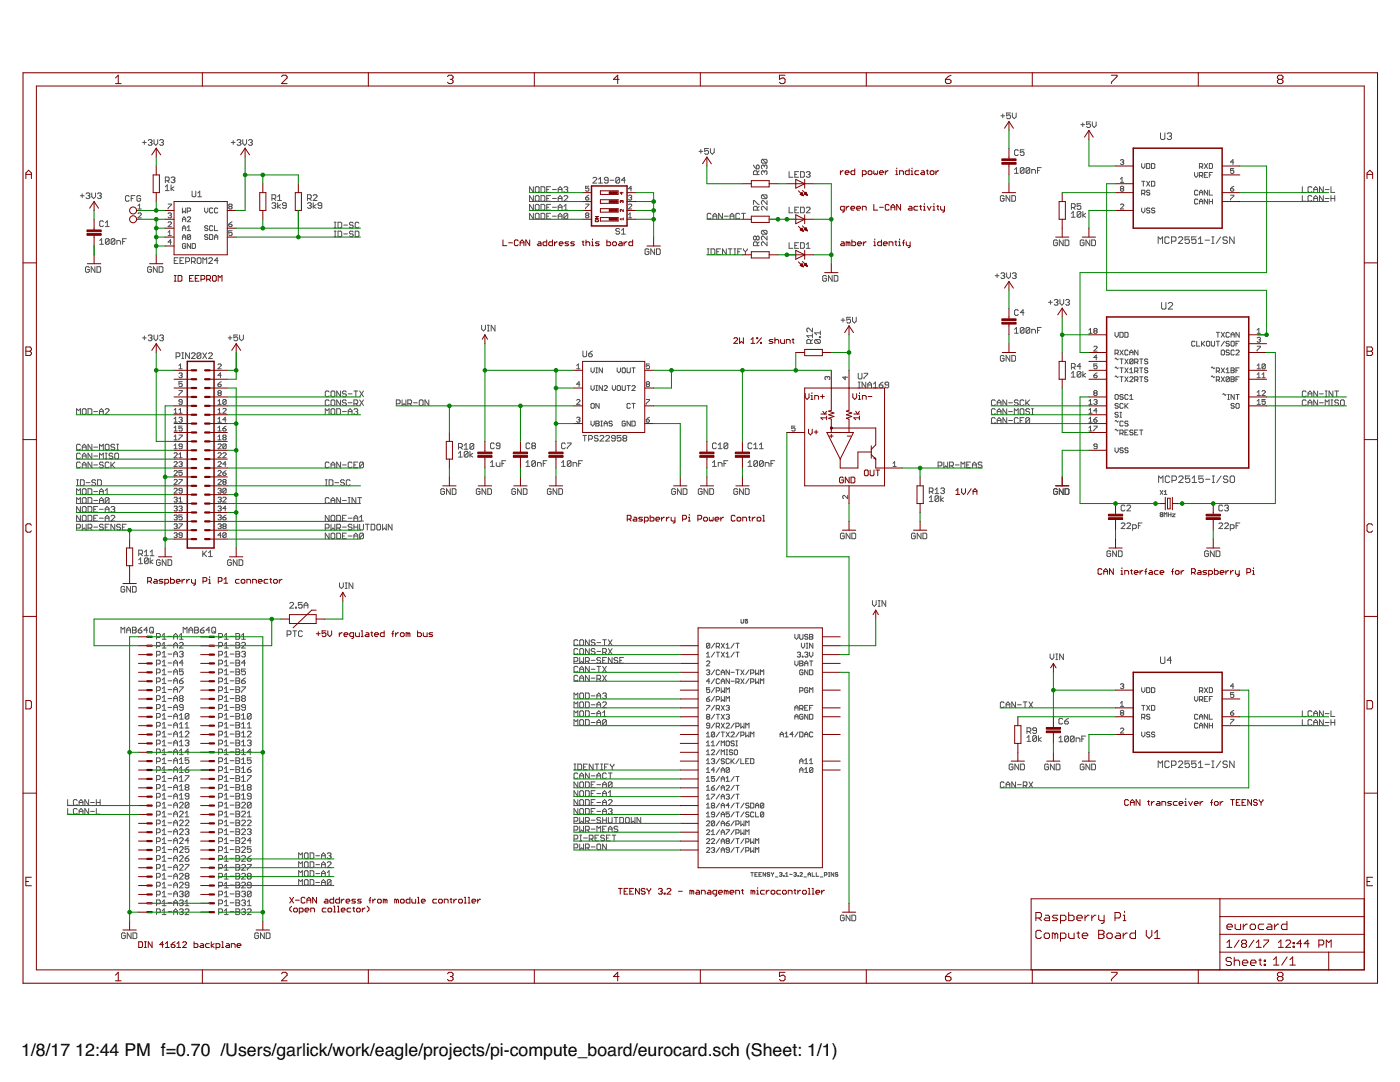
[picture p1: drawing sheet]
<svg xmlns="http://www.w3.org/2000/svg" width="279mm" height="216mm" viewBox="0 0 279 216" stroke-linecap="round" stroke-linejoin="round" font-family="sans-serif">
<defs><g id="words">
<g font-size="3.5">
<text x="4.2" y="210.7">1/8/17</text>
<text x="15" y="210.7">12:44 PM f=0.70 /Users/garlick/work/eagle/projects/pi-compute_board/eurocard.sch (Sheet: 1/1)</text>
</g>
</g></defs>
<g fill="none" stroke="#505050" stroke-width=".2">
<path d="M16 39.1h.8M16.4 38.7v.7M17.2 38.7l.2-.2h.3l.2 .2-.2 .4M17.5 39.1h.2M17.7 39.1l.2 .1-.2 .4h-.3l-.2-.2M18.3 38.5v.7l.4 .4 .4-.4v-.7M19.5 38.7l.1-.2h.4l.2 .2-.2 .4M19.8 39.1h.2M20 39.1l.2 .1-.2 .4h-.4l-.1-.2M25.8 39.2l-.2-.2h-.4l-.2 .2v.8l.2 .2h.4l.2-.2M26.2 39.6h.3M26.9 39h-.7v1.2"/>
<path d="M28.1 39.2l-.2-.2h-.4l-.2 .2v.8l.2 .2h.4l.2-.2v-.4h-.4M28.4 28.4h.8M28.8 28v.8M29.6 28l.2-.1h.3l.2 .1-.2 .4M30 28.4h.1M30.1 28.4l.2 .2-.2 .4h-.3l-.2-.2M30.7 27.9v.7l.4 .4 .4-.4v-.7M31.9 28l.1-.1h.4l.2 .1-.2 .4M32.2 28.4h.2M32.4 28.4l.2 .2-.2 .4h-.4l-.1-.2M33 37.3l.4-.4v1.1M33 38h.8"/>
<path d="M33 36.1h.6l.2-.2v-.4l-.2-.2h-.6v1.1M33.4 36.1l.4 .3M34.1 36.9v1.1M34.1 35.5l.2-.2h.4l.2 .2-.2 .4M34.5 35.9h.2M34.7 37.3l-.6 .4 .6 .3M34.7 35.9l.2 .2-.2 .3h-.4l-.2-.1M38.3 38.1v1l.2 .2h.4l.2-.2v-1M39.5 39.3h.7M39.5 38.5l.4-.4v1.2M46.2 28.4h.7M46.5 28v.8"/>
<path d="M47.3 28l.2-.1h.4l.2 .1-.2 .4M47.7 28.4h.2M47.9 28.4l.2 .2-.2 .4h-.4l-.2-.2M48.5 27.9v.7l.3 .4 .4-.4v-.7M49.6 28l.2-.1h.4l.2 .1-.2 .4M50 28.4h.2M50.2 28.4l.2 .2-.2 .4h-.4l-.2-.2M54.3 39.6h.5l.2-.2v-.3l-.2-.2h-.5v1.1M54.7 39.6l.3 .4M55.4 39.2l.4-.3v1.1M61.4 39.6h.5l.2-.2v-.3l-.2-.2h-.5v1.1M61.7 39.6l.4 .4"/>
<path d="M62.5 39.1l.2-.2h.4l.2 .2v.1l-.8 .8h.8M106.4 37.3v1.1l-.7-1.1v1.1M106.4 39v1.2l-.7-1.2v1.2M107 39h.4l.2 .2v.8l-.2 .2h-.4l-.2-.2v-.8zM107 37.3h.4l.2 .1v.8l-.2 .2h-.4l-.2-.2v-.8zM108 39h.5l.2 .2v.8l-.2 .2h-.5zM108 37.3h.5l.2 .1v.8l-.2 .2h-.5zM109.1 39.6h.4M109.1 37.8h.4M109.9 39h-.8v1.2h.8M109.9 37.3h-.8v1.1h.8M110.3 39.6h.7"/>
<path d="M110.3 37.8h.7M111.4 39.6h.8M111.4 37.8h.8M111.4 38.4v-.8l.4-.3 .4 .3v.8M112.5 39.2l.2-.2h.4l.2 .2v.2l-.8 .8h.8M112.5 37.4l.2-.1h.4l.2 .1-.2 .4M112.9 37.8h.2M113.1 37.8l.2 .2-.2 .4h-.4l-.2-.2M116.9 39.4h.4l.2 .4-.2 .1h-.3l-.1-.1zM117.5 37.2h-.6v.5l.4-.2 .2 .2v.3l-.2 .1-.4-.1M117.5 38.9l-.6 .5M118.3 35.6l.2-.2h.4l.2 .2v.2l-.8 .7h.8"/>
<path d="M119.5 35.8l.3-.4v1.1M119.5 36.5h.7M121.4 36h-.6l-.2-.2 .2-.4h.4l.2 .2v.7l-.2 .2h-.4l-.2-.2M121.8 36h.7M123.7 35.6v.7l-.2 .2h-.4l-.2-.2M123.7 35.6l-.2-.2h-.4l-.2 .2v.7M123.7 35.6l-.8 .7M124.8 36h-.8l.6-.6v1.1M125.4 39.1l.2-.2h.3l.2 .2-.2 .3M125.8 39.4h.1M125.9 39.4l.2 .2-.2 .3h-.3l-.2-.1M126.1 37.7h-.7l.5-.5v.9"/>
<path d="M139.5 30.2h.8M139.9 29.8v.8M141.4 29.6h-.8v.6l.4-.2 .4 .2v.4l-.2 .2h-.4l-.2-.2M141.8 29.6v.8l.4 .4 .3-.4v-.8M150.4 32.9l.5 .8M150.9 33.1l.2-.2 .4 .2v.4l-.2 .2h-.4zM151.1 34.8v-.5l-.2-.2h-.3l-.2 .2v.5h1.1M151.5 34.1l-.4 .4M152.1 31.8l-.1 .2v.4l.1 .2h.8M152.1 38.9l-.1 .2v.4l.1 .1h.8M152.1 31.8h.8l.2 .2v.4l-.2 .2M152.1 38.9h.8l.2 .2v.4l-.2 .1"/>
<path d="M152.1 31.8l.8 .8M152.1 38.9l.8 .7M152.5 33.1l.2-.2 .4 .2v.4l-.2 .2M152.5 34.3l-.2-.2-.3 .2v.3l.1 .2M152.5 33.1l-.2-.2-.3 .2v.4l.1 .2M152.5 34.3l.2-.2 .4 .2v.3l-.2 .2M152.5 33.1v.2M152.5 34.3v.2M157.5 34.2v1.2h.7M158.6 34.8h.4M159.4 34.2h-.8v1.2h.8M159.8 34.2h.5l.2 .2v.8l-.2 .2h-.5z"/>
<path d="M160.9 34.4l.2-.2h.4l.2 .2-.2 .4M161.3 34.8h.2M161.5 34.8l.2 .2-.2 .4h-.4l-.2-.2M199.7 23.1h.8M200.1 22.7v.8M200.4 39.2l-.2-.2h-.4l-.2 .2v.8l.2 .2h.4l.2-.2v-.4h-.4M201.5 39v1.2l-.7-1.2v1.2M201.7 22.5h-.8v.6l.4-.2 .4 .2v.4l-.2 .2h-.4l-.2-.2M201.9 39h.6l.2 .2v.8l-.2 .2h-.6zM202 22.5v.8l.4 .4 .4-.4v-.8M202.5 33.8l.4-.4v1.2M202.5 34.6h.7"/>
<path d="M203.2 30.1l-.2-.2h-.3l-.2 .2v.7l.2 .2h.3l.2-.2M204.4 29.9h-.8v.6l.4-.2 .4 .2v.3l-.2 .2h-.4l-.2-.2M204.4 33.6l-.2-.2h-.4l-.2 .2v.8M204.4 33.6v.8l-.2 .2h-.4l-.2-.2M204.4 33.6l-.8 .8M205.5 33.6l-.2-.2h-.3l-.2 .2v.8M205.5 33.6v.8l-.2 .2h-.3l-.2-.2M205.5 33.6l-.7 .8M205.9 34.6v-.8h.6l.2 .2v.6M207.1 34h.3M207.8 33.4h-.7v1.2M215.7 24.9h.8"/>
<path d="M216.1 24.5v.8M217.6 24.3h-.7v.6l.3-.2 .4 .2v.4l-.2 .1h-.4l-.1-.1M218 24.3v.8l.4 .3 .4-.3v-.8M223.6 35.7l.3-.3v1M223.6 32l.2-.1h.3l.2 .1-.2 .3M223.6 36.4h.7M223.8 37.7l-.2-.2 .2-.3h.3l.2 .1-.2 .4M223.8 37.7l-.2 .1 .2 .3 .5-.1-.2-.3M223.8 37.7h.3M223.9 32.3h.2M224.1 32.3l.2 .2-.2 .3h-.3l-.2-.1M227.8 32.6v.7l.4 .3 .3-.3v-.7"/>
<path d="M227.8 38.6h.5l.2-.2-.2-.4h-.5v.9M227.8 36.2h.7M228.2 36.2v.9M228.2 38.6l.3 .3M228.8 32.6h.5l.2 .2v.6l-.2 .2h-.5zM228.8 36.2l.7 .9M229.5 38.1l-.2-.1h-.3l-.2 .1 .2 .3h.3l.2 .2-.2 .3h-.3l-.2-.1M229.5 36.2l-.7 .9M229.8 32.6h.5l.2 .2v.6l-.2 .2h-.5zM229.8 36.2h.5l.2 .1v.7l-.2 .1h-.5zM231.6 26.5v1.1l.2 .2h.5l.2-.2v-1.1M232.9 26.7l.3-.2h.4l.2 .2-.2 .5"/>
<path d="M233.4 27.2h.2M233.6 27.2l.2 .2-.2 .4h-.4l-.3-.2M238.4 34.4v.7l.3 .3 .4-.3v-.7M239.1 39.9l-.2-.2-.5 .2v.6l.1 .2h.4l.2-.2M239.1 38.1l-.2-.1h-.4l-.1 .1v.7l.1 .1h.4l.2-.1M239.4 33.3h.5l.1-.2v-.3l-.1-.2h-.5v1M239.4 38.4h.6M239.4 35.1h.5l.1-.2v-.3l-.1-.2h-.5v1M239.4 38.9v-.6l.3-.3 .3 .3v.6M239.7 33.3l.3 .3M239.7 35.1l.3 .3M240.3 32.6l.7 1"/>
<path d="M240.3 34.9h.4M241 34.4h-.7v1h.7M241 32.6l-.7 1M241 38v.9l-.7-.9v.9M241 39.7v1l-.7-1v1M241.3 32.6h.5l.2 .2v.6l-.2 .2h-.5zM241.3 38v.9h.7M241.3 39.7v1M241.3 34.9h.4M242 34.4h-.7v1M242 39.7v1M245.6 37.7h.5l.1 .3-.5 .1-.1-.1z"/>
<path d="M245.6 38.9h.6l-.6 1M246.2 33.6h-.6v.5l.5-.1 .1 .1v.3l-.1 .2h-.4l-.1-.2M246.2 32.3h-.6l.5-.4v.9M246.2 37.2l-.6 .5M259.9 39v1.2h.8M259.9 37.3v1.1h.8M261.8 39.2l-.2-.2h-.4l-.2 .2v.8l.2 .2h.4l.2-.2M261.8 37.4l-.2-.1h-.4l-.2 .1v.8l.2 .2h.4l.2-.2M262.2 39.6h.8M262.2 38.4v-.8l.4-.3 .4 .3v.8M262.2 37.8h.8M264.1 37.3v1.1l-.8-1.1v1.1"/>
<path d="M264.1 39v1.2l-.8-1.2v1.2M264.5 39.6h.7M264.5 37.8h.7M265.6 39.6h.8M265.6 37.3v1.1h.8M265.6 39v1.2M266.4 39v1.2M17.8 53.4l-.2-.2h-.3l-.2 .2v.7l.2 .2h.3l.2-.2v-.3h-.4M18.9 53.2v1.1l-.7-1.1v1.1M19.3 53.2h.6l.2 .2v.7l-.2 .2h-.6zM19.9 48l.4-.4v1.1M19.9 48.7h.7"/>
<path d="M20.6 44.3l-.1-.2h-.4l-.2 .2v.7l.2 .2h.4l.1-.2M21 45.2h.8M21 44.4l.4-.3v1.1M21.8 47.8v.8l-.2 .1h-.4l-.2-.1M21.8 47.8l-.2-.2h-.4l-.2 .2v.8M21.8 47.8l-.8 .8M22.9 47.8v.8l-.1 .1h-.4l-.2-.1M22.9 47.8l-.1-.2h-.4l-.2 .2v.8M22.9 47.8l-.7 .8M23.3 48.7v-.7h.6l.2 .2v.5M24.5 48.2h.3M25.2 47.6h-.7v1.1"/>
<path d="M27.5 42.7l.2-.2h.3l.2 .2v.1l-.7 .7h.7M27.5 41.7h.7M27.5 41l.4-.3v1M30.2 53.4l-.2-.2h-.3l-.2 .2v.7l.2 .2h.3l.2-.2v-.3h-.4M31.4 53.2v1.1l-.8-1.1v1.1M31.7 53.2h.6l.2 .2v.7l-.2 .2h-.6zM33.5 40.7h.7l-.7 1M33.5 42.7l.2-.2h.3l.2 .2-.2 .3M33.5 44.4l.2-.1h.3l.2 .1v.2l-.7 .6h.7M33.5 47h.7M33.5 46.4l.4-.4v1M33.9 43h.1"/>
<path d="M34 43l.2 .1-.2 .4h-.3l-.2-.2M34.2 48.3h-.7l.5-.5v1M34.8 52h.4M35.5 51.4h-.7v1.2h.7M35.9 52h.4M36.4 41.5v1l.3-.4 .4 .4v-1M36.4 44.2v-.6l.3-.3 .4 .3v.6M36.4 46v-.6l.3-.4 .4 .4v.6M36.4 47.8v-.7l.3-.3 .4 .3v.7M36.4 45.5h.7M36.4 47.3h.7M36.4 43.8h.7"/>
<path d="M36.7 51.4h-.8v1.2h.8M37.1 52.2h.5l.2-.2v-.4l-.2-.2h-.5v1.2M37.1 48.7l-.2-.1-.5 .1v.7l.2 .2h.3l.2-.2v-.3h-.4M37.4 45.4l.3-.4v1M37.4 42.1h.5l.1-.1v-.3l-.1-.2h-.5v1M37.4 43.4l.1-.1h.4l.1 .1v.2l-.6 .6h.6M37.4 46h.6M38 47l-.1-.2-.5 .2v.6M38 48.6v1l-.6-1v1M38 47v.6l-.1 .2h-.4l-.1-.2M38 47l-.6 .6M38.2 52.2h.6l.2-.2v-.4l-.2-.2h-.6v1.2"/>
<path d="M38.4 48.6h.4l.2 .1v.7l-.2 .2h-.4zM38.6 52.2l.4 .4M39.3 51.6l.2-.2h.4l.2 .2v.8l-.2 .2h-.4l-.2-.2zM40.5 52.6v-1.2l.4 .4 .4-.4v1.2M40.8 41.5v.6l.4 .4 .3-.4v-.6M41.5 45.2l-.2-.2h-.3l-.2 .2 .2 .3h.3l.2 .2-.2 .3h-.3l-.2-.2M41.5 47l-.2-.2-.5 .2 .2 .3 .5 .2-.2 .3h-.3l-.2-.2M41.6 51.6l.2-.2h.4l.2 .2v.2l-.8 .8h.8M41.8 46.8h.5l.2 .2v.6l-.2 .2h-.5zM42.5 41.7l-.2-.2-.5 .2v.6l.2 .2h.3l.2-.2M42.5 45.2l-.2-.2h-.3l-.2 .2v.6l.2 .2h.3l.2-.2M42.8 45v1h.7"/>
<path d="M42.8 47.8v-.7l.3-.3 .4 .3v.7M42.8 47.3h.7M43.5 41.7l-.2-.2-.5 .2v.6l.2 .2h.3l.2-.2M43.5 52h-.7l.5-.6v1.2M45.7 44.7h.4l.2 .4-.5 .1-.1-.1zM45.8 41.2l-.1-.2 .1-.3 .5 .2-.2 .3M45.8 41.2l-.1 .2 .1 .3h.3l.2-.2-.2-.3M45.8 41.2h.3M46.3 46h-.6v.5l.4-.1 .2 .1v.3l-.2 .2h-.3l-.1-.2M46.3 44.3l-.6 .4M54.3 40.6l.2-.2h.3l.2 .2-.2 .4M54.7 41h.1"/>
<path d="M54.8 41l.2 .2-.2 .4h-.3l-.2-.2M55.4 40.4v1.2M55.4 40h.8M56 40.8l-.6 .4 .6 .4M57.1 41h-.5l-.2-.2 .2-.4h.3l.2 .2v.8l-.2 .2h-.3l-.2-.2M61.4 40.6l.2-.2h.3l.2 .2-.2 .4M61.7 41h.2M61.9 41l.2 .2-.2 .4h-.3l-.2-.2M62.5 40.4v1.2M63.1 40.8l-.6 .4 .6 .4M64.2 41h-.6l-.1-.2 .1-.4h.4l.2 .2v.8l-.2 .2h-.4l-.1-.2M66.7 47.2h.4"/>
<path d="M66.7 45.5h.4M66.7 44.3h.4M66.7 46.1h.4M66.9 44.3v1.2M66.9 46.1v1.1M67.5 46.1h.5l.2 .2v.8l-.2 .1h-.5zM67.5 44.3h.5l.2 .2v.8l-.2 .2h-.5zM68.6 44.9h.7M68.6 46.7h.7M70.5 46.3l-.2-.2h-.4l-.2 .2 .2 .4h.4l.2 .2-.2 .3h-.4l-.2-.1M70.5 44.5l-.2-.2h-.4l-.2 .2 .2 .4h.4l.2 .2-.2 .4h-.4l-.2-.2M70.9 46.1h.5l.2 .2v.8l-.2 .1h-.5z"/>
<path d="M71.6 44.5l-.2-.2h-.3l-.2 .2v.8l.2 .2h.3l.2-.2M106.4 40.8v1.1l-.7-1.1v1.1M106.4 42.6v1.1l-.7-1.1v1.1M106.8 42.8l.2-.2h.4l.2 .2v.7l-.2 .2h-.4l-.2-.2zM106.8 41l.2-.2h.4l.2 .2v.7l-.2 .2h-.4l-.2-.2zM108 40.8h.5l.2 .2v.7l-.2 .2h-.5zM108 42.6h.5l.2 .2v.7l-.2 .2h-.5zM109.1 41.4h.4M109.1 43.1h.4M109.9 40.8h-.8v1.1h.8M109.9 42.6h-.8v1.1h.8M110.3 41.4h.7"/>
<path d="M110.3 43.1h.7M111.4 43.7v-.8l.4-.3 .4 .3v.8M111.4 41.4h.8M111.4 40.2v-.8l.4-.4 .4 .4v.8M111.4 41.9v-.7l.4-.4 .4 .4v.7M111.4 43.1h.8M112.5 41.9h.8M112.5 41.2l.4-.4v1.1M113.3 42.8v.7l-.2 .2h-.4l-.2-.2M113.3 42.8l-.2-.2h-.4l-.2 .2v.7M113.3 42.8l-.8 .7M116.9 40.7h.6l-.6 1"/>
<path d="M117 43l-.1 .1 .1 .4h.3l.2-.2-.2-.3M117 43l-.1-.2 .1-.3h.3l.2 .2-.2 .3M117 43h.3M123.7 45.8l-.2-.2h-.4l-.2 .2 .2 .3h.4l.2 .2-.2 .4h-.4l-.2-.2M124 46.7h.8M124 46l.4-.4v1.1M125.4 40.9l.2-.2 .5 .2v.1l-.7 .7h.7M125.4 43.5h.7M125.4 42.8l.4-.3v1M129.5 49.8l-.2-.1h-.4l-.2 .1v.8l.2 .2h.4l.2-.2v-.4h-.4M130.6 49.7v1.1l-.7-1.1v1.1M131 49.7h.6l.2 .1v.8l-.2 .2h-.6z"/>
<path d="M141.1 49.7h.4M141.1 50.8h.4M141.3 49.7v1.1M141.9 49.7h.6l.2 .1v.8l-.2 .2h-.6zM141.9 42.8l-.2-.2h-.4l-.2 .2v.7l.2 .2h.4l.2-.2M142.3 43.7v-.8l.4-.3 .3 .3v.8M142.3 43.1h.7M143 50.2h.4M143.8 49.7h-.8v1.1h.8M144.2 42.6v1.1l-.8-1.1v1.1M144.6 43.1h.7M144.9 49.7v1.1l-.7-1.1v1.1"/>
<path d="M145.3 49.7h.8M145.7 43.1h.8M145.7 43.7v-.8l.4-.3 .4 .3v.8M145.7 49.7v1.1M146.5 49.7h.4M146.5 50.8h.4M146.7 49.7v1.1M147.2 50.2h.4M147.6 42.8l-.2-.2h-.4l-.1 .2v.7l.1 .2h.4l.2-.2M148 49.7h-.8v1.1M148 42.6h.8M148.4 42.6v1.1"/>
<path d="M148.4 49.7v.1l.4 .4M148.8 50.2v.6M149.1 49.7v.1l-.3 .4M150.4 40.8v-.8h.2l.7 .8h.2M150.9 47.3l-.2-.2-.3 .2v.4l.2 .2 .3-.2M150.9 47.3l.2-.2 .4 .2v.4l-.2 .2-.4-.2M150.9 47.3v.4M151.1 49v-.5l-.2-.2h-.3l-.2 .2v.5h1.1M151.1 41.9v-.5l-.2-.2h-.3l-.2 .2v.5h1.1M151.5 48.3l-.4 .3M151.5 41.2l-.4 .4M152.1 46l-.1 .2v.3l.1 .2h.8"/>
<path d="M152.1 46h.8l.2 .2v.3l-.2 .2M152.1 46l.8 .7M153.1 40v.8l-.8-.8h-.2l-.1 .2v.4l.1 .2M153.1 41.2v.7l-.8-.7h-.2l-.1 .2v.3l.1 .2M153.1 47.1v.8l-.8-.8h-.2l-.1 .2v.4l.1 .2M153.1 48.3v.7l-.8-.7h-.2l-.1 .2v.3l.1 .2M157.5 41.3v1.2h.7M157.5 48.4v1.2h.7M158.6 49h.4M158.6 41.9h.4M159.4 48.4h-.8v1.2h.8M159.4 41.3h-.8v1.2h.8"/>
<path d="M159.8 48.4h.5l.2 .2v.8l-.2 .2h-.5zM159.8 41.3h.5l.2 .2v.8l-.2 .2h-.5zM160.9 41.5l.2-.2h.4l.2 .2v.2l-.8 .8h.8M160.9 49.6h.8M160.9 48.8l.4-.4v1.2M164.9 55.2l-.1-.2h-.4l-.2 .2v.7l.2 .2h.4l.1-.2v-.4h-.3M166.1 55v1.1l-.8-1.1v1.1M166.5 55h.5l.2 .2v.7l-.2 .2h-.5zM198.6 55h.8M199 54.6v.8M199.7 54.6l.2-.2h.4l.2 .2-.2 .4M200.1 55h.2"/>
<path d="M200.3 55l.2 .2-.2 .4h-.4l-.2-.2M200.9 54.4v.8l.4 .4 .4-.4v-.8M202 54.6l.2-.2h.4l.2 .2-.2 .4M202.4 55h.2M202.6 55l.2 .2-.2 .4h-.4l-.2-.2M209.6 59.9v.8M210.4 59.9l.2-.1h.3l.2 .1-.2 .4M211 48.1l-.2-.2h-.3l-.2 .2v.7l.2 .2h.3l.2-.2v-.3h-.3M211.5 59.8v.7l.4 .4 .4-.4v-.7M212.2 47.9v1.1l-.8-1.1v1.1M212.6 47.9h.5l.2 .2v.7l-.2 .2h-.5zM212.7 59.9l.2-.1h.3l.2 .1-.2 .4"/>
<path d="M213.8 42.6l.4-.4v1.1M213.8 43.3h.8M213.8 41.4h.6l.2-.2v-.4l-.2-.2h-.6v1.2M214.2 41.4l.4 .4M215.7 40.6h-.7v.6l.3-.2 .4 .2v.4l-.2 .2h-.3l-.2-.2M215.7 42.4l-.2-.2h-.3l-.2 .2v.8M215.7 42.4v.8l-.2 .1h-.3l-.2-.1M215.7 42.4l-.7 .8M216.1 42.2v1.1M216.3 48.1l-.1-.2h-.4l-.2 .2v.7l.2 .2h.4l.1-.2v-.3h-.3M216.7 42.6l-.6 .4 .6 .3M217.5 47.9v1.1l-.8-1.1v1.1"/>
<path d="M217.9 47.9h.5l.2 .2v.7l-.2 .2h-.5zM223.6 40.9l.2-.2 .5 .2v.1l-.7 .7h.7M227.8 41.5v.6l.4 .4 .3-.4v-.6M229.5 41.7l-.2-.2-.5 .2 .2 .3 .5 .1-.2 .4h-.3l-.2-.2M230.5 41.7l-.2-.2-.5 .2 .2 .3 .5 .1-.2 .4h-.3l-.2-.2M231.1 48.6v-1.3l.5 .4 .4-.4v1.3M233.3 47.5l-.2-.2h-.4l-.2 .2v.9l.2 .2h.4l.2-.2M233.8 48.1h.7l.2-.2v-.4l-.2-.2h-.7v1.3M235.2 47.5l.2-.2h.4l.2 .2v.2l-.8 .9h.8M237.4 47.3h-.9v.6l.4-.2h.3l.2 .2v.5l-.2 .2h-.5l-.2-.2M238.7 47.3h-.9v.6l.5-.2 .4 .2v.5l-.2 .2h-.5l-.2-.2M239.2 48.6h.9"/>
<path d="M239.2 47.7l.4-.4v1.3M239.4 40.7v-.7l.3-.3 .3 .3v.7M239.4 40.2h.6M240.5 47.9h.9M241.3 40.2h.7M241.9 47.3h.4M241.9 48.6h.4M242.1 47.3v1.3M243.6 47.3l-.9 1.3M244.9 47.5l-.2-.2h-.4l-.2 .2v.2l.2 .2h.4l.2 .2v.3l-.2 .2h-.4l-.2-.2M246.3 47.3v1.3l-.9-1.3v1.3M262.2 40.2v-.8l.4-.4 .4 .4v.8"/>
<path d="M28.4 67.4h.8M28.8 67v.8M29.6 67l.2-.2h.3l.2 .2-.2 .4M30 67.4h.1M30.1 67.4l.2 .2-.2 .4h-.3l-.2-.2M30.7 66.8v.8l.4 .4 .4-.4v-.8M31.9 67l.1-.2h.4l.2 .2-.2 .4M32.2 67.4h.2M32.4 67.4l.2 .2-.2 .4h-.4l-.1-.2M35.1 71.2h.6l.2-.2v-.4l-.2-.2h-.6v1.1M35.7 72.9l.3-.3v1M35.7 73.6h.7"/>
<path d="M35.7 74.5l.5-.1 .2 .1-.2 .4M35.7 77.9h.7l-.7 1M36 74.9h.2M36.2 74.9l.2 .1-.2 .4h-.3l-.2-.2M36.3 70.4h.4M36.3 71.5h.4M36.4 76.2h-.7v.5l.3-.2 .4 .2v.3l-.2 .2h-.3l-.2-.2M36.5 70.4v1.1M37.8 70.4v1.1l-.8-1.1v1.1M38.2 70.6l.2-.2h.4l.1 .2v.2l-.7 .7h.7M40.1 70.6l-.2-.2h-.4l-.2 .2v.8M40.1 70.6v.8l-.2 .1h-.4l-.2-.1"/>
<path d="M40.1 70.6l-.8 .8M40.5 70.4l.7 1.1M41.2 70.4l-.7 1.1M41.6 70.6l.2-.2h.4l.2 .2v.2l-.8 .7h.8M43.5 72.8l.2-.2h.3l.2 .2-.7 .8h.7M43.5 76.7h.5l.2 .3-.2 .2h-.3l-.2-.2zM43.7 78.4l-.2-.1 .2-.4h.3l.2 .2-.2 .3M43.7 78.4l-.2 .2 .2 .3 .5-.1-.2-.4M43.7 78.4h.3M44.2 74.9h-.7l.5-.5v1M44.2 76.2l-.7 .5M45.1 79.9v.6l-.1 .2h-.4l-.1-.2"/>
<path d="M45.1 79.9l-.1-.2h-.4l-.1 .2v.6M45.1 79.9l-.6 .6M45.5 67.4h.8M45.9 67v.8M47.4 66.8h-.7v.6l.4-.2 .3 .2v.4l-.2 .2h-.3l-.2-.2M47.8 66.8v.8l.4 .4 .4-.4v-.8M65.7 78.2l-.2-.2h-.4l-.2 .2v.8l.2 .2h.4l.2-.2M65.7 80l-.2-.2h-.4l-.2 .2v.7l.2 .2h.4l.2-.2M66.1 78.2l.2-.2h.3l.2 .2v.8l-.2 .2h-.3l-.2-.2zM66.3 79.8h.3l.2 .2v.7l-.2 .2h-.3l-.2-.2v-.7zM68 78v1.2l-.8-1.2v1.2M68 79.8v1.1l-.8-1.1v1.1"/>
<path d="M69.1 80l-.2-.2h-.4l-.2 .2 .2 .4h.4l.2 .2-.2 .3h-.4l-.2-.2M69.1 78.2l-.2-.2h-.4l-.2 .2 .2 .4h.4l.2 .2-.2 .4h-.4l-.2-.2M69.5 78.6h.8M70.6 78h.8M71 78v1.2M71.8 78l.7 1.2M71.8 79.8l.7 1.1M72.5 78l-.7 1.2M72.5 79.8l-.7 1.1M80.2 79.8v1.1l.4-.3 .4 .3v-1.1M83.7 80l.2-.2h.3l.2 .2v.7l-.2 .2h-.3l-.2-.2zM85.6 79.8v1.1l-.8-1.1v1.1"/>
<path d="M96.1 64.9v.8l.4 .3 .4-.3v-.8M97.3 66h.3M97.3 64.9h.3M97.5 64.9v1.1M98.8 64.9v1.1l-.8-1.1v1.1M115.1 73.6h.6M115.1 79.9l.2-.2h.3l.1 .2-.6 .8h.6M115.1 72.9l.3-.3v1M115.7 76.7h-.6l.5-.5v1M116.3 70v1l.2 .2h.4l.2-.2v-1M117.5 70.6h.5l.2 .4-.2 .2h-.4l-.1-.2zM117.9 73.4v.7l.4 .3 .3-.3v-.7"/>
<path d="M117.9 76.9v.7l.4 .3 .3-.3v-.7M118.2 70l-.7 .6M118.9 74.4h.4M118.9 77.9h.4M118.9 73.4h.4M118.9 76.9h.4M119.1 73.4v1M119.1 76.9v1M120.2 73.4v1l-.6-1v1M120.2 76.9v1l-.6-1v1M120.6 77.1l.1-.2h.4l.1 .2v.2l-.6 .6h.6M122.2 76.9v.7l.3 .3 .4-.3v-.7"/>
<path d="M123.2 73.4v.7l.3 .3 .3-.3v-.7M123.3 76.9h.4l.1 .2v.7l-.1 .1-.5-.1v-.7zM124.2 76.9v.9l.1 .1 .5-.1v-.9M124.3 73.4h.4l.1 .2v.6l-.1 .2h-.4l-.1-.2v-.6zM125.1 73.4v.8l.2 .2h.3l.2-.2v-.8M125.1 76.9h.7M125.5 76.9v1M126.1 77.1l.2-.2h.3l.2 .2v.2l-.7 .6h.7M126.1 73.4h.7M126.4 73.4v1M129 79.7h.6l-.6 1M129.1 76.7l-.1-.2 .1-.3h.4l.1 .1-.1 .4"/>
<path d="M129.1 76.7l-.1 .1 .1 .4h.4l.1-.2-.1-.3M129.1 76.7h.4M129.6 72.6h-.6v.5l.3-.2 .3 .2v.3l-.1 .2h-.4l-.1-.2M161.8 68.5v-.6l-.2-.1h-.4l-.2 .1v.6h1.1M162.1 65.5v.7l-.7-.7-.4 .2v.3l.2 .2M162.1 67.8l-.3 .3M162.1 67h-1.1l.4 .4M162.1 66.6v.8M162.8 67.8l-.2 .1v.4l.2 .2h.7M162.8 67.8h.7l.2 .1v.4l-.2 .2M162.8 67.8l.7 .7M163.5 67.2h.2v.2h-.2z"/>
<path d="M163.7 66v.8M163.7 66.4h-1.1l.4 .4M165.1 75.3l-.1-.2-.4 .2v.3l.2 .2M165.1 75.3l.2-.2 .3 .2v.3l-.2 .2M165.1 75.3v.1M167.9 63.9h.7M168.2 63.5v.8M168.7 75.1v.7l-.5-.5h1M169.7 63.3h-.7v.6l.4-.2 .3 .2v.4l-.1 .2h-.4l-.2-.2M170.1 63.3v.8l.4 .4 .4-.4v-.8M171.3 77.4h.4M171.3 76.2h.4"/>
<path d="M171.3 74.5v.9l.2 .2h.4l.1-.2v-.9M171.5 76.2v1.2M172.4 74.5h.8v.2l-.8 .7v.2M172.8 76.2v1.2l-.8-1.2v1.2M173.2 77.4v-.8l.4-.4 .3 .4v.8M173.2 76.8h.7M174.3 77.4h.8M174.3 76.6l.4-.4v1.2M175.5 76.8h.5l.2 .4-.2 .2h-.3l-.2-.2zM176.2 76.2l-.7 .6M177.4 76.8h-.6l-.2-.2 .2-.4h.4l.2 .2v.8l-.2 .2h-.4l-.2-.2M198.6 80l-.2-.2h-.3l-.2 .2v.7l.2 .2h.3l.2-.2"/>
<path d="M200.4 71.1l-.2-.2h-.4l-.2 .2v.8l.2 .2h.4l.2-.2v-.4h-.4M200.9 79.8v1.1l-.7-1.1v1.1M201.5 70.9v1.2l-.7-1.2v1.2M201.9 70.9h.6l.2 .2v.8l-.2 .2h-.6zM202.5 65.7l.4-.4v1.2M202.5 66.5h.7M203.2 80l-.2-.2h-.4l-.2 .4 .2 .2h.4l.2 .3-.2 .2h-.4l-.2-.2M203.2 62l-.2-.2h-.3l-.2 .2v.7l.2 .2h.3l.2-.2M204.3 80l-.1-.2h-.4l-.2 .2v.7l.2 .2h.4l.1-.2M204.4 65.5v.8l-.2 .2h-.4l-.2-.2M204.4 65.5l-.2-.2h-.4l-.2 .2v.8M204.4 65.5l-.8 .8"/>
<path d="M204.4 62.4h-.8l.6-.6v1.1M204.7 79.8v1.1M205.5 79.8l-.8 .8M205.5 65.5v.8l-.2 .2h-.3l-.2-.2M205.5 65.5l-.2-.2h-.3l-.2 .2v.8M205.5 65.5l-.7 .8M205.9 66.5v-.8h.6l.2 .2v.6M207.1 65.9h.3M207.8 65.3h-.7v1.2M209.3 60.3h.7M210.8 60.3h.1M210.9 60.3l.2 .2-.2 .4h-.3l-.2-.2"/>
<path d="M213.1 60.3h.1M213.2 60.3l.2 .2-.2 .4h-.3l-.2-.2M213.8 74.5l.4-.4v1.1M213.8 75.2h.8M213.8 73.3h.6l.2-.2v-.4l-.2-.2h-.6v1.2M214.2 73.3l.4 .4M215.7 74.3v.8l-.2 .1h-.3l-.2-.1M215.7 74.3l-.2-.2h-.3l-.2 .2v.8M215.7 74.3l-.7 .8M215.7 73.1h-.7l.5-.6v1.2M216.1 74.1v1.1M216.7 74.5l-.6 .4 .6 .3"/>
<path d="M217.3 65.8l.3-.3v1M217.3 66.5h.7M218.3 74.9h.5l.1 .3-.1 .2h-.3l-.2-.2zM218.3 79.9l.2-.2h.3l.1 .2-.1 .3M218.3 69.2l.2-.1 .4 .1v.2l-.6 .7h.6M218.5 66l-.2 .2 .2 .3h.3l.1-.2-.1-.3M218.5 78.4l-.2-.1 .2-.4h.3l.1 .2-.1 .3M218.5 78.4l-.2 .2 .2 .3 .4-.1-.1-.4M218.5 78.4h.3M218.5 66l-.2-.2 .2-.3h.3l.1 .2-.1 .3M218.5 66h.3M218.9 71.3h-.6l.5-.5v1"/>
<path d="M218.9 72.6h-.6v.5l.3-.2 .3 .2v.3l-.1 .2h-.3l-.2-.2M218.9 74.4l-.6 .5M222.5 75.2l.2-.2 .3 .3 .2-.1M222.5 66.3v.7l.4 .3 .3-.3v-.7M222.5 70.5h.5l.2-.2v-.3l-.2-.2h-.5v1M222.5 71.6l.2-.1 .3 .3 .2-.2M222.5 73.4l.2-.2 .3 .4 .2-.2M222.7 78.7h.3l.2 .2v.6l-.2 .2h-.3l-.2-.2v-.6zM222.9 70.5l.3 .3M223.5 66.3h.5l.2 .2v.6l-.2 .2h-.5zM223.5 69.8l.7 1M223.5 71.6h.7"/>
<path d="M223.5 73.4h.7M223.5 75.2h.7M223.8 71.6v1M223.8 73.4v1M223.8 75.2v1M224.2 78.9l-.2-.2h-.3l-.2 .2 .2 .3h.3l.2 .2-.2 .3h-.3l-.2-.2M224.2 69.8l-.7 1M224.5 66.3h.5l.1 .2v.6l-.1 .2h-.5zM224.5 71.6l.6 1M224.5 73.4l.6 1M224.5 75.2l.6 1M225.1 70l-.1-.2h-.4l-.1 .2v.7l.1 .1 .5-.1"/>
<path d="M225.1 78.9l-.1-.2h-.4l-.1 .2v.6l.1 .2h.4l.1-.2M225.1 71.6l-.6 1M225.1 73.4l-.6 1M225.1 75.2l-.6 1M225.5 74.4h.6M225.5 75.3l.1-.1 .5 .1v.2l-.6 .7h.6M225.5 70.8v-.6l.3-.4 .3 .4v.6M225.5 70.3h.6M225.5 73.7l.3-.3v1M225.5 79l.3-.3v1M225.5 79.7h.6M226.1 71.8l-.1-.2h-.4l-.1 .2v.7"/>
<path d="M226.1 71.8v.7l-.1 .1-.5-.1M226.1 71.8l-.6 .7M226.4 74.1h.5l.2-.2v-.3l-.2-.2h-.5v1M226.4 72.3h.5l.2-.2v-.3l-.2-.2h-.5v1M226.4 75.8h.5l.2-.1v-.4l-.2-.1h-.5v1M226.8 75.8l.3 .4M226.8 72.3l.3 .3M226.8 74.1l.3 .3M227.1 69.8v1l-.7-1v1M227.4 71.6h.7M227.4 73.4h.7M227.4 75.2h.7"/>
<path d="M227.8 71.6v1M227.8 73.4v1M227.8 75.2v1M229.1 71.8l-.2-.2h-.3l-.2 .2 .2 .3h.3l.2 .2-.2 .3-.5-.1M229.1 73.6l-.2-.2h-.3l-.2 .2 .2 .3h.3l.2 .2-.2 .3h-.3l-.2-.2M229.1 75.3l-.2-.1-.5 .1 .2 .4 .5 .1-.2 .4h-.3l-.2-.2M231.8 60.4v1.1l.2 .2h.5l.2-.2v-1.1M233.2 60.6l.2-.2h.4l.2 .2v.2l-.8 .9h.8M238.5 68.2l-.2-.1-.5 .1v.7l.2 .2h.3l.2-.2M238.8 68.1v1h.7M239.8 68.1v1M240 68.6l.5 .5"/>
<path d="M240.5 68.1l-.7 .6M240.8 68.2l.1-.1 .5 .1v.7l-.1 .2h-.4l-.1-.2zM241.7 68.1v.8l.2 .2h.4l.1-.2v-.8M241.7 73.4l.2-.2 .4 .4 .1-.2M241.7 75.2l.2-.2 .4 .3 .1-.1M242.7 66.3h.7M242.7 74.1h.5l.2-.2-.2-.5h-.5v1M242.7 75.8h.5l.2-.5-.2-.1h-.5v1M242.7 68.1h.7M243.1 66.3v1M243.1 68.1v1M243.1 74.1l.3 .3"/>
<path d="M243.1 75.8l.3 .4M243.7 66.3l.7 1M243.7 73.4l.7 1M243.7 75.2l.7 1M243.9 69.8h.3l.2 .2v.7l-.2 .1-.5-.1v-.7zM244 78.7l.2-.2 .3 .4 .2-.2M244.4 66.3l-.7 1M244.4 68.1l-.7 1M244.4 73.4l-.7 1M244.4 75.2l-.7 1M244.7 73.7l.3-.3v1M244.7 74.4h.6"/>
<path d="M245 78.7h.3M245 79.7h.3M245.2 78.7v1M245.3 66.5l-.1-.2h-.3l-.2 .2v.6l.2 .2h.3l.1-.2M245.3 75.3v.7l-.1 .2h-.3l-.2-.2M245.3 70l-.1-.2h-.3l-.2 .4 .5 .1 .1 .4-.1 .1-.5-.1M245.3 75.3l-.1-.1-.5 .1v.7M245.3 68.2l-.1-.1-.5 .1 .2 .4 .4 .1-.1 .4h-.3l-.2-.2M245.3 75.3l-.6 .7M245.7 75.2h.5l.1 .1-.1 .4 .1 .3-.1 .2h-.5zM245.7 73.4h.5l.1 .2-.1 .3 .1 .3-.1 .2h-.5zM245.7 73.9h.5"/>
<path d="M245.7 75.7h.5M245.7 67.3v-.7l.3-.3 .3 .3v.7M245.7 66.8h.6M245.8 68.1l.5 .1v.7l-.1 .2h-.4l-.1-.2v-.7zM246.3 70l-.1-.2h-.4l-.1 .2v.7l.1 .1 .5-.1M246.3 78.7v1l-.6-1v1M246.7 70l.1-.2h.3l.2 .2v.2l-.6 .6h.6M246.7 73.9h.3M246.7 75.7h.3M246.7 78.7h.6M246.7 68.6h.3M247 78.7v1"/>
<path d="M247.3 66.3v1l-.6-1v1M247.3 68.1h-.6v1M247.3 73.4h-.6v1M247.3 75.2h-.6v1M250.9 66.5h.6M250.9 73.6h.6M250.9 75.4h.6M250.9 78.9h.6M250.9 67.5l.5-.2 .1 .2-.1 .3M250.9 69.1h.6l-.6 1M250.9 65.8l.3-.3v1M250.9 72.9l.3-.3v1"/>
<path d="M250.9 74.7l.3-.3v1M250.9 78.3l.3-.4v1M251.2 67.8h.2M251.4 67.8l.1 .2-.1 .3h-.3l-.2-.2M251.9 75.4h.6M251.9 78.1l.1-.2h.3l.2 .2v.2l-.6 .6h.6M251.9 74.7l.3-.3v1M252.5 72.8v.6l-.2 .2h-.3l-.1-.2M252.5 72.8l-.2-.2h-.3l-.1 .2v.6M252.5 79.7h-.6v.5l.3-.2 .3 .2v.3l-.2 .2h-.3l-.1-.2M252.5 72.8l-.6 .6M260.7 78.2l-.2-.2h-.4l-.2 .2v.8l.2 .2h.4l.2-.2"/>
<path d="M260.7 80l-.2-.2h-.4l-.2 .2v.7l.2 .2h.4l.2-.2M261 79.2v-.8l.4-.4 .4 .4v.8M261 78.6h.8M263 78v1.2l-.8-1.2v1.2M263 79.8v1.1l-.8-1.1v1.1M263.3 78.6h.8M264.5 78h.4M264.5 79.2h.4M264.7 78v1.2M265.6 79.8h.4M265.8 79.8v1.1M266 78v1.2l-.8-1.2v1.2"/>
<path d="M266.4 78h.7M266.8 78v1.2M267.1 80l-.1-.2h-.4l-.2 .4 .2 .2h.4l.1 .3-.1 .2h-.4l-.2-.2M267.7 79.8h.4l.2 .2v.7l-.2 .2h-.4l-.2-.2v-.7zM15.3 82.7v-1.1l.4 .3 .3-.3v1.1M15.3 98.7v-1.2l.4 .4 .3-.4v1.2M15.3 96.9h.4M15.3 95.7h.4M15.5 95.7v1.2M16 88.8l-.1-.2h-.4l-.2 .2v.8l.2 .2h.4l.1-.2M16 95.7h.6l.2 .2v.8l-.2 .2h-.6zM16 92.4l-.1-.2h-.4l-.2 .2v.8l.2 .1h.4l.1-.1"/>
<path d="M16 90.6l-.1-.2h-.4l-.2 .2v.8l.2 .2h.4l.1-.2M16.4 89.8v-.8l.4-.4 .4 .4v.8M16.4 91.6v-.8l.4-.4 .4 .4v.8M16.4 93.3v-.7l.4-.4 .4 .4v.7M16.4 92.8h.8M16.4 89.2h.8M16.4 91h.8M16.6 81.6h.4l.2 .1v.8l-.2 .2h-.4l-.2-.2v-.8zM16.6 97.5h.4l.2 .2v.8l-.2 .2h-.4l-.2-.2v-.8zM16.6 99.3h.4l.2 .2v.7l-.2 .2h-.4l-.2-.2v-.7zM17.2 96.3h.7M17.6 81.6h.5l.2 .1v.8l-.2 .2h-.5z"/>
<path d="M17.6 97.5h.5l.2 .2v.8l-.2 .2h-.5zM17.6 99.3h.5l.2 .2v.7l-.2 .2h-.5zM18.3 88.6v1.2l-.7-1.2v1.2M18.3 90.4v1.2l-.7-1.2v1.2M18.3 92.2v1.1l-.7-1.1v1.1M18.7 98.1h.8M18.7 99.9h.8M18.7 92.8h.8M18.7 82.1h.8M18.7 89.2h.8M18.7 91h.8M19.1 95.9l-.2-.2h-.4l-.2 .2 .2 .4h.4l.2 .2-.2 .4h-.4l-.2-.2"/>
<path d="M19.5 95.7h.5l.2 .2v.8l-.2 .2h-.5zM19.9 98.1h.7M19.9 91.6v-1.2l.3 .4 .4-.4v1.2M19.9 82.7v-.8l.3-.3 .4 .3v.8M19.9 99.9h.7M19.9 89.8v-1.2l.3 .4 .4-.4v1.2M19.9 98.7v-.8l.3-.4 .4 .4v.8M19.9 82.1h.7M20.6 92.4l-.2-.2h-.4l-.1 .4 .1 .2h.4l.2 .4-.2 .1h-.4l-.1-.1M21 98.7h.8M21 81.7l.2-.1h.4l.2 .1v.2l-.8 .8h.8M21 90.4h.4"/>
<path d="M21 91.6h.4M21 97.9l.4-.4v1.2M21.2 88.6h.4l.2 .2v.8l-.2 .2h-.4l-.2-.2v-.8zM21.2 90.4v1.2M21.8 99.5l-.2-.2h-.4l-.2 .2v.7M21.8 99.5v.7l-.2 .2h-.4l-.2-.2M21.8 92.4l-.2-.2h-.4l-.2 .2v.8l.2 .1h.4l.2-.1M21.8 99.5l-.8 .7M22.1 92.2v1.1M22.3 92.8l.6 .5M22.5 90.6l-.2-.2h-.4l-.1 .2 .1 .4h.4l.2 .2-.2 .4h-.4l-.1-.2M22.9 88.8l-.2-.2h-.4l-.2 .2 .2 .4h.4l.2 .2-.2 .4h-.4l-.2-.2"/>
<path d="M22.9 92.2l-.8 .8M23.1 90.4h.4l.2 .2v.8l-.2 .2h-.4l-.2-.2v-.8zM23.3 88.6h.4M23.3 89.8h.4M23.5 88.6v1.2M34.7 81.8l.4-.3v1M34.7 83.6l.4-.4v1M34.7 85.4l.4-.4v1M34.7 87.1l.4-.3v1M34.7 88.9l.4-.3v1M34.7 82.5h.7M34.7 84.2h.7"/>
<path d="M34.7 86h.7M34.7 87.8h.7M34.7 89.6h.7M34.7 90.5l.2-.2h.3l.2 .2v.2l-.7 .6h.7M34.7 92.3l.2-.2h.3l.2 .2v.2l-.7 .6h.7M34.7 94.1l.2-.2h.3l.2 .2-.7 .8h.7M34.7 95.8l.2-.1 .5 .1v.2l-.7 .6h.7M34.7 97.6l.2-.2h.3l.2 .2v.2l-.7 .6h.7M34.7 99.4l.2-.2h.3l.2 .2-.2 .3M35.1 99.7h.1M35.2 99.7l.2 .2-.2 .3-.5-.2M35.7 81.8l.3-.3v1"/>
<path d="M35.7 90.7l.3-.4v1M35.7 99.5l.3-.3v1M35.7 83.4l.2-.2h.3l.2 .2-.2 .4M35.7 86.8h.7l-.7 1M35.7 92.3l.2-.2h.3l.2 .2-.2 .3M35.7 95.7h.7l-.7 .9M35.7 82.5h.7M35.7 91.3h.7M36 83.8h.2M36 92.6h.2M36.2 83.8l.2 .1-.2 .3h-.3l-.2-.1M36.2 92.6l.2 .2-.2 .3-.5-.2"/>
<path d="M36.4 80.2h-.5l-.2-.2 .2-.3h.3l.2 .2v.6l-.2 .2h-.3l-.2-.2M36.4 85h-.7v.5l.5-.1 .2 .1v.4l-.2 .1-.5-.1M36.4 89.1h-.5l-.2-.2 .2-.3 .5 .1v.7l-.2 .2h-.3l-.2-.2M36.4 93.9h-.7v.5l.3-.2 .4 .2v.3l-.2 .2h-.3l-.2-.2M36.4 97.9h-.5l-.2-.1 .2-.4h.3l.2 .2v.7l-.2 .1-.5-.1M43.5 97.6l.2-.2h.3l.2 .2-.2 .3M43.5 88.7l.2-.1 .5 .1v.2l-.7 .7h.7M43.5 90.5l.2-.2h.3l.2 .2v.2l-.7 .6h.7M43.5 92.3l.2-.2h.3l.2 .2v.2l-.7 .6h.7M43.5 94.1l.2-.2h.3l.2 .2-.7 .8h.7M43.5 95.8l.2-.1 .5 .1v.2l-.7 .6h.7M43.5 99.4l.2-.2h.3l.2 .2-.2 .3"/>
<path d="M43.5 80.7h.7M43.5 80l.3-.3v1M43.5 81.8l.3-.3v1M43.5 83.6l.3-.4v1M43.5 85.4l.3-.4v1M43.5 87.1l.3-.3v1M43.5 82.5h.7M43.5 84.2h.7M43.5 86h.7M43.5 87.8h.7M43.8 97.9h.2M43.8 99.7h.2"/>
<path d="M44 97.9l.2 .2-.2 .3-.5-.1M44 99.7l.2 .2-.2 .3-.5-.2M44.5 85.5h.5l.1 .4-.5 .1-.1-.1zM44.5 94.4h.5l.1 .3-.1 .2h-.4l-.1-.2zM44.5 81.6l.1-.1 .5 .1v.2l-.6 .7h.6M44.5 90.5l.1-.2h.4l.1 .2v.2l-.6 .6h.6M44.5 99.4l.1-.2h.4l.1 .2-.6 .8h.6M44.6 96.2l-.1-.2 .1-.3 .5 .1-.1 .4M44.6 87.3l-.1-.2 .1-.3h.4l.1 .2-.1 .3M44.6 87.3l-.1 .2 .1 .3h.4l.1-.2-.1-.3M44.6 96.2l-.1 .1 .1 .3h.4l.1-.1-.1-.3M44.6 87.3h.4"/>
<path d="M44.6 96.2h.4M45.1 88.7l-.1-.1-.5 .1v.7M45.1 97.6l-.1-.2h-.4l-.1 .2v.7M45.1 88.7v.7l-.1 .2h-.4l-.1-.2M45.1 97.6v.7l-.1 .1-.5-.1M45.1 83.8h-.6l.5-.6v1M45.1 92.6h-.6l.5-.5v1M45.1 85l-.6 .5M45.1 88.7l-.6 .7M45.1 93.9l-.6 .5M45.1 97.6l-.6 .7M64.9 82.7v-1.1l.4 .3 .4-.3v1.1"/>
<path d="M64.9 96.9h.4M64.9 95.7h.4M65.1 95.7v1.2M65.7 92.4l-.2-.2h-.4l-.2 .2v.8l.2 .1h.4l.2-.1M65.7 95.7h.6l.1 .2v.8l-.1 .2h-.6zM65.7 99.5l-.2-.2h-.4l-.2 .2v.7l.2 .2h.4l.2-.2M66.1 93.3v-.7l.3-.4 .4 .4v.7M66.1 99.9h.7M66.1 92.8h.7M66.3 81.6h.3l.2 .1v.8l-.2 .2h-.3l-.2-.2v-.8zM66.8 96.3h.8M67.2 81.6h.6l.2 .1v.8l-.2 .2h-.6z"/>
<path d="M68 92.2v1.1l-.8-1.1v1.1M68 99.3v1.1l-.8-1.1v1.1M68.3 99.9h.8M68.3 92.8h.8M68.3 82.1h.8M68.7 95.9l-.2-.2h-.3l-.2 .4 .2 .2h.3l.2 .4-.2 .2h-.3l-.2-.2M69.5 99.3h.4M69.5 82.7v-.8l.4-.3 .4 .3v.8M69.5 80.4h.8M69.5 82.1h.8M69.7 99.3v1.1M69.9 95.9l-.2-.2h-.4l-.2 .2v.8l.2 .2h.4l.2-.2"/>
<path d="M70.3 92.4l-.2-.2h-.4l-.2 .2v.8l.2 .1h.4l.2-.1M70.6 81.7l.2-.1h.4l.2 .1-.2 .4M70.6 92.8h.4M70.6 80.6h.6l.2-.2v-.4l-.2-.2h-.6v1.1M71 99.3v1.1l-.7-1.1v1.1M71 82.1h.2M71 80.6l.4 .3M71.2 82.1l.2 .2-.2 .4h-.4l-.2-.2M71.4 99.3h.8M71.4 92.2h-.8v1.1h.8M71.8 99.3v1.1M72.5 92.4l-.2-.2h-.3l-.2 .2v.8"/>
<path d="M72.5 92.4v.8l-.2 .1h-.3l-.2-.1M72.5 92.4l-.7 .8M79.1 80.6h.6l.2-.2v-.4l-.2-.2h-.6v1.1M81.4 80.6h.6l.1-.2v-.4l-.1-.2h-.6v1.1M81.8 80.6l.3 .3M82.5 80.4h.8M88.7 97.7l-.2-.2h-.3l-.2 .2v.8l.2 .2h.3l.2-.2v-.4h-.4M89.9 97.5v1.2l-.8-1.2v1.2M90.3 97.5h.5l.2 .2v.8l-.2 .2h-.5zM91.5 90.4l.4-.3v1.1M91.5 91.2h.8M91.5 89.3h.6l.2-.2v-.4l-.2-.2h-.6v1.1"/>
<path d="M91.9 89.3l.4 .3M92.6 88.9l.4-.4v1.1M92.6 89.6h.8M93.4 90.3v.7l-.2 .2h-.4l-.2-.2M93.4 90.3l-.2-.2h-.4l-.2 .2v.7M93.4 90.3l-.8 .7M93.8 90.1v1.1M94.4 90.4l-.6 .4 .6 .4M94.6 88.7l-.2-.2h-.4l-.2 .2v.8M94.6 88.7v.8l-.2 .1h-.4l-.2-.1M94.6 88.7l-.8 .8M95.8 97.7l-.2-.2h-.4l-.1 .2v.8l.1 .2h.4l.2-.2v-.4h-.4"/>
<path d="M96.9 97.5v1.2l-.7-1.2v1.2M97.3 97.5h.6l.2 .2v.8l-.2 .2h-.6zM97.9 93.1h.7M97.9 92.3l.4-.4v1.2M98.6 88.6l-.2-.2h-.3l-.2 .2v.7l.2 .2h.3l.2-.2M99 92.3v.6l.2 .2h.6v-.8M99.8 89h-.6l-.2-.2 .2-.4h.4l.2 .2v.7l-.2 .2h-.4l-.2-.2M100.2 92.5h.3M100.9 91.9h-.7v1.2M102.9 97.7l-.2-.2h-.4l-.1 .2v.8l.1 .2h.4l.2-.2v-.4h-.4M104 97.5v1.2l-.7-1.2v1.2M104.4 97.5h.6l.2 .2v.8l-.2 .2h-.6z"/>
<path d="M105 93.1h.7M105 92.3l.3-.4v1.2M105.7 88.6l-.2-.2h-.3l-.2 .2v.7l.2 .2h.3l.2-.2M106.3 89l-.2-.2 .2-.4h.4l.2 .2-.2 .4M106.3 89l-.2 .2 .2 .3h.4l.2-.2-.2-.3M106.3 89h.4M106.9 92.1v.8l-.2 .2h-.4l-.2-.2M106.9 92.1l-.2-.2h-.4l-.2 .2v.8M106.9 92.1l-.8 .8M107.3 93.1v-.8h.5l.2 .2v.6M108.4 92.5h.4M109.2 91.9h-.8v1.2"/>
<path d="M110 97.7l-.2-.2h-.4l-.2 .2v.8l.2 .2h.4l.2-.2v-.4h-.4M111.1 97.5v1.2l-.7-1.2v1.2M111.5 97.5h.6l.2 .2v.8l-.2 .2h-.6zM112.1 92.3l.3-.4v1.2M112.1 93.1h.7M112.8 88.6l-.2-.2h-.4l-.1 .2v.7l.1 .2h.4l.2-.2M113.2 88.4h.8v.2l-.8 .7v.2M114 92.1v.8l-.2 .2h-.4l-.2-.2M114 92.1l-.2-.2h-.4l-.2 .2v.8M114 92.1l-.8 .8M114.4 93.1v-.8h.5l.2 .2v.6M115.1 83.4l.2-.2h.3l.1 .2-.1 .4"/>
<path d="M115.4 83.8h.2M115.5 92.5h.4M115.6 83.8l.1 .1-.1 .3h-.3l-.2-.1M116.2 91.9h-.7v1.2M116.3 86.9h.8M116.7 86.9v1.1M117.5 87.6h.5l.2-.1v-.4l-.2-.2h-.5v1.1M117.9 80.7l.2-.2h.3l.2 .2v.6l-.2 .2h-.3l-.2-.2zM117.9 84v.7l.4 .3 .3-.3v-.7M118.9 84h.5l.2 .2-.2 .3 .2 .4-.2 .1h-.5zM118.9 84.5h.5M119.4 87.1l-.2-.2h-.4l-.2 .4 .2 .2h.4l.2 .3-.2 .2h-.4l-.2-.2"/>
<path d="M119.6 80.5v1l-.7-1v1M119.7 87.1l.2-.2h.4l.2 .2v.2l-.8 .7h.8M119.9 85h.3M119.9 84h.3M120.1 84v1M120.6 84.5h.6M120.6 85v-.6l.3-.4 .3 .4v.6M120.9 87.1l.2-.2h.4l.1 .2v.2l-.7 .7h.7M122.2 84.2l-.2-.2h-.3l-.2 .4 .5 .1 .2 .4-.2 .1-.5-.1M122.8 87.5h-.6l-.2-.2 .2-.4h.4l.2 .2v.7l-.2 .2h-.4l-.2-.2M123.9 86.9h-.7v.6l.3-.2 .4 .2v.3l-.2 .2h-.3l-.2-.2M124.5 87.5l-.2-.2 .2-.4h.4l.2 .2-.2 .4"/>
<path d="M124.5 87.5h.4M124.5 87.5l-.2 .1 .2 .4h.4l.2-.2-.2-.3M124.8 84.2l-.1-.2h-.4l-.1 .2v.7l.1 .1 .5-.1v-.4h-.3M125.8 80.7l-.2-.2h-.3l-.2 .2v.6l.2 .2h.3l.2-.2M125.8 84v1l-.7-1v1M126.1 84h.5l.2 .2v.7l-.2 .1h-.5zM126.1 80.5h.7M126.4 80.5v1M129 83.8h.5l.1 .3-.1 .1h-.4l-.1-.1zM129.6 83.2l-.6 .6M134.8 97.7l-.2-.2h-.4l-.2 .2v.8l.2 .2h.4l.2-.2v-.4h-.4M136 97.5v1.2l-.8-1.2v1.2"/>
<path d="M136.3 97.5h.6l.2 .2v.8l-.2 .2h-.6zM140.1 97.7l-.2-.2h-.3l-.2 .2v.8l.2 .2h.3l.2-.2v-.4h-.4M141.3 97.5v1.2l-.8-1.2v1.2M141.6 97.5h.6l.2 .2v.8l-.2 .2h-.6zM142.2 93.1h.8M142.2 92.3l.4-.4v1.2M143 88.6l-.2-.2h-.4l-.2 .2v.7l.2 .2h.4l.2-.2M143.3 93.1v-.8h.6l.2 .2v.6M143.3 89.5h.8M143.3 88.8l.4-.4v1.1M144.5 92.5h.4M145.2 91.9h-.7v1.2"/>
<path d="M145.2 88.6l-.1-.2h-.4l-.2 .2v.7M145.2 88.6v.7l-.1 .2h-.4l-.2-.2M145.2 88.6l-.7 .7M147.2 97.7l-.2-.2h-.4l-.1 .2v.8l.1 .2h.4l.2-.2v-.4h-.4M148.4 97.5v1.2l-.8-1.2v1.2M148.7 97.5h.6l.2 .2v.8l-.2 .2h-.6zM149.3 93.1h.8M149.3 92.3l.4-.4v1.2M150.1 88.6l-.2-.2h-.4l-.2 .2v.7l.2 .2h.4l.2-.2M150.4 89.5h.8M150.4 88.8l.4-.4v1.1M151.2 92.1v.8l-.2 .2h-.4l-.2-.2"/>
<path d="M151.2 92.1l-.2-.2h-.4l-.2 .2v.8M151.2 92.1l-.8 .8M151.6 88.8l.4-.4v1.1M151.6 89.5h.7M152.3 92.1v.8l-.2 .2h-.3l-.2-.2M152.3 92.1l-.2-.2h-.3l-.2 .2v.8M152.3 92.1l-.7 .8M152.7 93.1v-.8h.6l.2 .2v.6M153.9 92.5h.3M154.6 91.9h-.7v1.2M158.7 85h-.7v.5l.5-.1 .2 .5-.2 .1-.5-.1M169.2 98.8v.7l-.7-.7h-.2l-.1 .2 .1 .5"/>
<path d="M178.2 93.1h.7M178.2 92.5l.3-.4v1M185.5 98.1h.5l.2-.2v-.3l-.2-.2h-.5v1.1M185.5 99.3l.3-.4v1.2M185.8 98.1l.4 .4M186.6 97.7l.4-.3v1.1M186.6 98.5h.7M187.2 93h.6l.2-.2v-.4l-.2-.2h-.6v1.1M187.3 99.1l-.1-.2h-.4l-.2 .2v.8M187.3 99.1v.8l-.1 .2h-.4l-.2-.2M187.3 99.1l-.7 .8M187.7 98.9v1.2"/>
<path d="M187.7 97.6l.2-.2h.4l.2 .2-.2 .3M188.1 97.9h.2M188.3 99.3l-.6 .4 .6 .4M188.3 97.9l.2 .2-.2 .4h-.4l-.2-.2M188.4 92.2v1.1l.3-.3 .4 .3v-1.1M189.5 93h.6l.2-.2v-.4l-.2-.2h-.6v1.1M189.9 93l.4 .3M190.6 92.8h.8M191.8 93.3v-1.1l.4 .4 .4-.4v1.1M192.9 92.8h.4M193.7 92.2h-.8v1.1h.8M194.1 92.8h.7"/>
<path d="M194.1 93.3v-.7l.4-.4 .3 .4v.7M196 92.4l-.2-.2h-.4l-.2 .2 .2 .4h.4l.2 .2-.2 .3h-.4l-.2-.1M198.6 81.7l-.2-.1h-.3l-.2 .1v.8l.2 .2h.3l.2-.2M198.6 83.5l-.2-.2h-.3l-.2 .2v.8l.2 .2h.3l.2-.2M199 80.9v-.7l.4-.4 .4 .4v.7M199 82.7v-.8l.4-.3 .4 .3v.8M199 84.5v-.8l.4-.4 .4 .4v.8M199 80.4h.8M199 83.9h.8M199 82.1h.8M200.9 81.6v1.1l-.7-1.1v1.1M200.9 83.3v1.2l-.7-1.2v1.2"/>
<path d="M201.3 80.4h.8M201.3 83.9h.8M201.3 82.1h.8M202.4 82.7v-1.1l.4 .3 .4-.3v1.1M203.2 83.5l-.2-.2h-.4l-.2 .2v.8l.2 .2h.4l.2-.2M203.6 81.7l.2-.1h.4l.1 .1v.8l-.1 .2h-.4l-.2-.2zM203.6 83.9h.4M204.3 83.3h-.7v1.2h.7M204.9 80.4l.6 .5M205.5 81.7l-.2-.1h-.4l-.2 .3 .2 .2h.4l.2 .4-.2 .2h-.4l-.2-.2M205.5 83.5v.8l-.2 .2h-.4l-.2-.2M205.5 83.5l-.2-.2h-.4l-.2 .2v.8"/>
<path d="M205.5 83.5l-.8 .8M205.9 81.6h.3M205.9 82.7h.3M206.1 81.6v1.1M211 97.7l-.2-.2h-.3l-.2 .2v.8l.2 .2h.3l.2-.2v-.4h-.3M212.2 97.5v1.2l-.8-1.2v1.2M212.6 97.5h.5l.2 .2v.8l-.2 .2h-.5zM217.3 80l.3-.3v1M217.3 81.8l.3-.3v1M217.3 83.6l.3-.4v1M217.3 85.4l.3-.4v1M217.3 80.7h.7"/>
<path d="M217.3 82.5h.7M217.3 84.2h.7M217.3 86h.7M218.3 83.8h.5l.1 .3-.1 .1h-.3l-.2-.1zM218.3 85h.6l-.6 1M218.6 80.2h.2M218.8 80.2l.1 .2-.1 .3h-.3l-.2-.2M218.9 82h-.6l.5-.5v1M218.9 89.1h-.4l-.2-.2 .2-.3 .4 .1v.7l-.1 .2h-.3l-.2-.2M218.9 83.2l-.6 .6M222.5 89.4v.6l.4 .3 .3-.3v-.6M222.5 84l.2-.1 .3 .3 .2-.2"/>
<path d="M222.5 85.8l.2-.2 .3 .4 .2-.2M223.2 82.4l-.2-.1-.5 .1 .2 .4 .5 .1-.2 .3h-.3l-.2-.1M223.2 80.7l-.2-.2h-.3l-.2 .3 .2 .2h.3l.2 .3-.2 .2h-.3l-.2-.2M223.5 83.2h.3M223.5 86.5h.5l.2-.2-.2-.5h-.5v1M223.5 82.3h.3M223.7 82.3v.9M223.8 86.5l.4 .3M224.2 89.5l-.2-.1-.5 .1 .2 .4 .5 .1-.2 .3h-.3l-.2-.1M224.2 84.2l-.2-.2h-.3l-.2 .2v.7l.2 .1 .5-.1M224.2 80.7l-.2-.2h-.3l-.2 .2v.6l.2 .2h.3l.2-.2M224.5 80.5v1"/>
<path d="M224.5 86.3h.3M224.6 81l.5 .5M225.1 84.2l-.1-.2h-.4l-.1 .4 .5 .1 .1 .4-.1 .1-.5-.1M225.1 85.8h-.6v1h.6M225.1 89.5l-.1-.1-.5 .1 .1 .4 .5 .1-.1 .3h-.4l-.1-.1M225.1 80.5l-.6 .7M226.1 86l-.1-.2h-.4l-.1 .2 .1 .3h.4l.1 .2-.1 .3h-.4l-.1-.2M226.4 86.3h.4M227.1 85.8h-.7v1h.7M227.4 85.8h.7M227.8 85.8v1M231.2 96.3v-1.3l.5 .4 .4-.4v1.3"/>
<path d="M231.5 97.9l.6 .8M232.1 97.9l-.6 .8M232.3 98.7h.6M232.3 98.1l.3-.2v.8M233.4 95.2l-.2-.2h-.4l-.2 .2v.9l.2 .2h.4l.2-.2M233.9 95.9h.6l.3-.3v-.4l-.3-.2h-.6v1.3M235.2 95.2l.3-.2h.4l.2 .2v.2l-.9 .9h.9M237.4 95h-.8v.6l.4-.2 .4 .2v.5l-.2 .2h-.4l-.2-.2M237.9 96.3h.9M237.9 95.4l.5-.4v1.3M240.1 95h-.9v.6l.7-.2 .2 .2v.5l-.2 .2h-.4l-.3-.2M240.6 95.6h.9"/>
<path d="M241.9 95h.5M241.9 96.3h.5M242.1 95v1.3M243.7 95l-.9 1.3M245 95.2l-.2-.2h-.4l-.2 .4 .2 .2h.4l.2 .5-.2 .2h-.4l-.2-.2M245.7 95h.4l.3 .2v.9l-.3 .2h-.4l-.2-.2v-.9zM246.3 80.7l-.1-.2h-.4l-.1 .3 .1 .2h.4l.1 .3-.1 .2h-.4l-.1-.2M246.8 80.5h.3l.2 .2v.6l-.2 .2h-.3l-.1-.2v-.6zM250.9 80.7h.6M250.9 80l.3-.3v1M261 80.9v-.7l.4-.4 .4 .4v.7M261 80.4h.8"/>
<path d="M263.3 80.4h.8M264.5 80.9v-1.1l.4 .4 .3-.4v1.1M265.6 80.9h.4M15.3 100.4v-1.1l.4 .4 .3-.4v1.1M15.3 105.4h.6l.1-.2v-.4l-.1-.2h-.6v1.1M16 101.1v1.1l-.7-1.1v1.1M16 102.8v1.2l-.7-1.2v1.2M16.4 104.6v1.1l.4-.3 .4 .3v-1.1M16.6 101.1h.4l.2 .2v.7l-.2 .2h-.4l-.2-.2v-.7zM16.6 102.8h.4l.2 .2v.8l-.2 .2h-.4l-.2-.2v-.8zM17.6 101.1h.5l.2 .2v.7l-.2 .2h-.5zM17.6 102.8h.5l.2 .2v.8l-.2 .2h-.5z"/>
<path d="M17.6 105.4h.5l.2-.2v-.4l-.2-.2h-.5v1.1M17.9 105.4l.4 .3M18.7 101.6h.4M18.7 103.4h.4M18.7 105.2h.8M19.5 101.1h-.8v1.1h.8M19.5 102.8h-.8v1.2h.8M19.9 100.4v-.7l.3-.4 .4 .4v.7M19.9 101.6h.7M19.9 103.4h.7M20.6 104.8l-.2-.2h-.4l-.1 .2 .1 .4h.4l.2 .2-.2 .3h-.4l-.1-.1M21 104v-.8l.4-.4 .4 .4v.8"/>
<path d="M21 102.2v-.7l.4-.4 .4 .4v.7M21 101.6h.8M21 103.4h.8M21 105.2h.4M21.8 104.6h-.8v1.1h.8M22.1 101.3l.2-.2h.4l.2 .2-.2 .3M22.1 103l.2-.2h.4l.2 .2v.2l-.8 .8h.8M22.5 101.6h.2M22.7 101.6l.2 .2-.2 .4h-.4l-.2-.2M22.9 104.6v1.1l-.8-1.1v1.1M24 104.8l-.1-.2h-.4l-.2 .2 .2 .4h.4l.1 .2-.1 .3h-.4l-.2-.1M24.4 105.2h.4"/>
<path d="M24.9 117.2l-.2-.2h-.4l-.1 .2v.8l.1 .2h.4l.2-.2v-.4h-.4M25.2 104.6h-.8v1.1h.8M26 117v1.2l-.7-1.2v1.2M26.4 117h.6l.2 .2v.8l-.2 .2h-.6zM27.7 110.5h.6l.1-.2v-.3l-.1-.2h-.6v1.1M27.7 111.7l.4-.4v1.2M27.7 112.5h.7M28.1 110.5l.3 .4M28.8 110.2l.4-.4v1.1M28.8 110.9h.8M29.6 111.5v.8l-.2 .2h-.4l-.2-.2M29.6 111.5l-.2-.2h-.4l-.2 .2v.8"/>
<path d="M29.6 111.5l-.8 .8M30 110.2l.4-.4v1.1M30 111.3v1.2M30 110.9h.7M30.5 111.7l-.5 .4 .5 .4M32 111.9l-.2-.2h-.4l-.2 .2v.7l.2 .2h.4l.2-.2v-.3h-.4M33.1 111.7v1.1l-.7-1.1v1.1M33.5 111.7h.6l.2 .2v.7l-.2 .2h-.6zM34.7 101.2l.2-.2h.3l.2 .2-.2 .3M34.7 102.9l.5-.1 .2 .1-.2 .4M34.7 104.7l.2-.2h.3l.2 .2-.2 .3M34.7 106.5l.2-.2h.3l.2 .2-.2 .3"/>
<path d="M35.1 101.5h.1M35.1 103.3h.1M35.1 105h.1M35.1 106.8h.1M35.2 105l.2 .2-.2 .3-.5-.2M35.2 103.3l.2 .1-.2 .3h-.3l-.2-.1M35.2 101.5l.2 .1-.2 .4h-.3l-.2-.2M35.2 106.8l.2 .2-.2 .3h-.3l-.2-.2M35.7 101.2l.2-.2h.3l.2 .2-.2 .3M35.7 104.5h.7l-.7 1M35.7 100.2h.7M36 101.5h.2"/>
<path d="M36.2 101.5l.2 .1-.2 .4h-.3l-.2-.2M36.4 102.8h-.7v.5l.3-.2 .4 .2v.3l-.2 .1h-.3l-.2-.1M36.4 106.8h-.5l-.2-.2 .2-.3h.3l.2 .2v.6l-.2 .2h-.3l-.2-.2M40.5 109.9v1.2M40.7 110.5l.5 .6M41.2 109.9l-.7 .8M41.6 111.1h.8M41.6 110.3l.4-.4v1.2M43.5 101.2l.2-.2h.3l.2 .2-.2 .3M43.5 102.9l.5-.1 .2 .1-.2 .4M43.5 104.7l.2-.2h.3l.2 .2-.2 .3M43.8 101.5h.2"/>
<path d="M43.8 103.3h.2M43.8 105h.2M44 105l.2 .2-.2 .3-.5-.2M44 101.5l.2 .1-.2 .4h-.3l-.2-.2M44 103.3l.2 .1-.2 .3h-.3l-.2-.1M44.2 106.8h-.7l.5-.5v1M44.5 103.3h.5l.1 .3-.1 .1h-.4l-.1-.1zM44.6 105l-.1 .2 .1 .3 .5-.2-.1-.3M44.6 105l-.1-.1 .1-.4h.4l.1 .2-.1 .3M44.6 105h.4M45.1 106.5l-.1-.2h-.4l-.1 .2v.6M45.1 106.5v.6l-.1 .2h-.4l-.1-.2"/>
<path d="M45.1 101.5h-.6l.5-.5v1M45.1 102.8l-.6 .5M45.1 106.5l-.6 .6M46.2 111.9l-.2-.2h-.4l-.2 .2v.7l.2 .2h.4l.2-.2v-.3h-.4M47.3 111.7v1.1l-.7-1.1v1.1M47.7 111.7h.6l.2 .2v.7l-.2 .2h-.6zM64.9 105.4h.6l.2-.2v-.4l-.2-.2h-.6v1.1M65.7 102.8v1.2l-.8-1.2v1.2M65.7 106.4v1.1l-.8-1.1v1.1M66.1 100.4v-.7l.3-.4 .4 .4v.7M66.1 104.6v1.1l.3-.3 .4 .3v-1.1M66.3 106.4h.3l.2 .2v.7l-.2 .2h-.3l-.2-.2v-.7z"/>
<path d="M66.3 102.8h.3l.2 .2v.8l-.2 .2h-.3l-.2-.2v-.8zM67.2 106.4h.6l.2 .2v.7l-.2 .2h-.6zM67.2 105.4h.6l.2-.2v-.4l-.2-.2h-.6v1.1M67.2 102.8h.6l.2 .2v.8l-.2 .2h-.6zM67.6 105.4l.4 .3M67.8 116.3v.8l.3 .3 .4-.3v-.8M68.3 107h.4M68.3 103.4h.4M68.3 105.2h.8M68.9 117.4h.4M68.9 116.3h.4M69.1 116.3v1.1"/>
<path d="M69.1 106.4h-.8v1.1h.8M69.1 102.8h-.8v1.2h.8M69.5 107h.8M69.5 100.4h.4M69.5 103.4h.8M70.3 104.8l-.2-.2h-.4l-.2 .2 .2 .4h.4l.2 .2-.2 .3h-.4l-.2-.1M70.4 116.3v1.1l-.7-1.1v1.1M70.6 107h.8M70.6 104v-.8l.4-.4 .4 .4v.8M70.6 107.5v-.7l.4-.4 .4 .4v.7M70.6 104.6v1.1M70.6 103.4h.8"/>
<path d="M70.6 105.2h.8M71.4 104.6v1.1M71.8 104.6v1l.2 .1h.3l.2-.1v-1M71.8 103.2l.4-.4v1.2M71.8 104h.7M72.5 106.6l-.2-.2h-.3l-.2 .2v.7M72.5 106.6v.7l-.2 .2h-.3l-.2-.2M72.5 106.6l-.7 .7M72.9 104.6h.8M73.3 104.6v1.1M74.1 104.6h.5l.2 .2v.8l-.2 .1h-.5zM75.2 104.8l.2-.2h.4l.1 .2v.8l-.1 .1h-.4l-.2-.1z"/>
<path d="M76.3 104.6v1.1l.4-.3 .4 .3v-1.1M78.2 104.6v1.1l-.7-1.1v1.1M168.5 106.6l-.2-.2h-.4l-.2 .2v.7l.2 .2h.4l.2-.2v-.3h-.4M169.6 106.4v1.1l-.7-1.1v1.1M170 106.4h.6l.2 .2v.7l-.2 .2h-.6zM174.1 119.8v.8l.4 .4 .4-.4v-.8M175.3 119.8h.3M175.5 119.8v1.2M176.8 119.8v1.2l-.8-1.2v1.2M182.7 106.6l-.2-.2h-.4l-.2 .2v.7l.2 .2h.4l.2-.2v-.3h-.4M183.8 106.4v1.1l-.8-1.1v1.1M184.2 106.4h.6l.2 .2v.7l-.2 .2h-.6z"/>
<path d="M185.5 100.1h.7M221.7 110.1l-.2-.2h-.4l-.2 .2v.8l.2 .2h.4l.2-.2v-.4h-.4M222.8 109.9v1.2l-.7-1.2v1.2M223.2 109.9h.6l.1 .2v.8l-.1 .2h-.6zM223.8 104.5l.1-.1h.4l.2 .1v.2l-.7 .8h.7M224.5 101l-.2-.2h-.4l-.1 .2v.7l.1 .2h.4l.2-.2M224.9 104.5l.2-.1h.3l.2 .1v.2l-.7 .8h.7M224.9 101l.2-.2h.3l.2 .2v.2l-.7 .7h.7M226 105.5h.6l.2-.2v-.4l-.2-.2h-.6v1.2M227.2 104.9h.3M227.9 104.4h-.7v1.1M231.7 102.7l-.2-.1 .2-.3 .4 .1-.2 .3"/>
<path d="M231.7 102.7l-.2 .1 .2 .3 .4-.1-.2-.3M231.7 102.7h.2M232.3 103.1v-.8l.3 .3 .3-.3v.8M233.2 102.7h.5M233.2 102.3v.8M233.7 102.3v.8M234 102.6h.5l-.5 .5h.5M241.2 110.1l-.2-.2h-.4l-.2 .2v.8l.2 .2h.4l.2-.2v-.4h-.4M242.3 109.9v1.2l-.7-1.2v1.2M242.7 109.9h.6l.2 .2v.8l-.2 .2h-.6zM243.2 104.5l.2-.1h.4l.2 .1v.2l-.8 .8h.8M244 101l-.2-.2h-.4l-.2 .2v.7l.2 .2h.4l.2-.2"/>
<path d="M244.4 104.5l.2-.1h.4l.2 .1v.2l-.8 .8h.8M244.4 101l.2-.2h.4l.2 .2-.2 .4M244.8 101.4h.2M245 101.4l.2 .2-.2 .3h-.4l-.2-.2M245.5 105.5h.6l.2-.2v-.4l-.2-.2h-.6v1.2M246.7 104.9h.4M247.4 104.4h-.7v1.1M24.2 126.3v-1.1l.3 .3 .4-.3v1.1M25.3 126.3v-.8l.4-.3 .3 .3v.8M25.3 125.7h.7M26.4 125.7h.6M26.4 125.2h.6l.2 .1-.2 .4 .2 .4-.2 .2h-.6z"/>
<path d="M27.6 125.7h.5l.2 .4-.2 .2h-.3l-.2-.2zM28.3 125.2l-.7 .5M29.5 125.7h-.8l.6-.5v1.1M30.1 125.2h.3l.2 .1v.8l-.2 .2h-.3l-.2-.2v-.8zM30.2 125.9l.4 .4M31.2 127.2h.6l.2-.2v-.4l-.2-.2h-.6v1.2M31.2 128.9h.6l.2-.1v-.4l-.2-.2h-.6v1.1M31.2 130.7h.6l.2-.2v-.3l-.2-.2h-.6v1.1M31.2 132.5h.6l.2-.2v-.4l-.2-.2h-.6v1.2M31.2 134.3h.6l.2-.2v-.4l-.2-.2h-.6v1.1M31.2 136h.6l.2-.2v-.3l-.2-.2h-.6v1.1M31.2 137.8h.6l.2-.2v-.4l-.2-.1h-.6v1.1"/>
<path d="M31.2 139.6h.6l.2-.2v-.4l-.2-.2h-.6v1.2M32.4 126.8l.4-.4v1.2M32.4 128.6l.4-.4v1.1M32.4 130.3l.4-.3v1.1M32.4 132.1l.4-.4v1.2M32.4 133.9l.4-.4v1.1M32.4 135.7l.4-.4v1.1M32.4 137.4l.4-.3v1.1M32.4 139.2l.4-.4v1.2M32.4 127.6h.7M32.4 129.3h.7M32.4 131.1h.7"/>
<path d="M32.4 132.9h.7M32.4 134.6h.7M32.4 136.4h.7M32.4 138.2h.7M32.4 140h.7M33.5 127h.8M33.5 128.8h.8M33.5 130.5h.8M33.5 132.3h.8M33.5 134.1h.8M33.5 135.8h.8M33.5 137.6h.8"/>
<path d="M33.5 139.4h.8M34.7 129.3v-.7l.4-.4 .3 .4v.7M34.7 127h.7M34.7 127.6v-.8l.4-.4 .3 .4v.8M34.7 131.1v-.8l.4-.3 .3 .3v.8M34.7 132.9v-.8l.4-.4 .3 .4v.8M34.7 134.6v-.7l.4-.4 .3 .4v.7M34.7 136.4v-.7l.4-.4 .3 .4v.7M34.7 138.2v-.8l.4-.3 .3 .3v.8M34.7 140v-.8l.4-.4 .3 .4v.8M34.7 128.8h.7M34.7 130.5h.7"/>
<path d="M34.7 132.3h.7M34.7 134.1h.7M34.7 135.8h.7M34.7 137.6h.7M34.7 139.4h.7M35.8 128.4l.2-.2h.4l.2 .2v.2l-.8 .7h.8M35.8 130.2l.2-.2h.4l.2 .2-.2 .3M35.8 135.8h.6l.2 .4-.2 .2h-.4l-.2-.2zM35.8 137.1h.8v.1l-.8 .8v.2M35.8 126.8l.4-.4v1.2M35.8 127.6h.8M36 139.4l-.2-.2 .2-.4h.4l.2 .2-.2 .4"/>
<path d="M36 139.4l-.2 .2 .2 .4h.4l.2-.2-.2-.4M36 139.4h.4M36.2 130.5h.2M36.4 130.5l.2 .2-.2 .4h-.4l-.2-.2M36.6 126.3v-1.1l.3 .3 .4-.3v1.1M36.6 133.5h-.8v.6l.6-.2 .2 .2v.4l-.2 .1h-.4l-.2-.1M36.6 132.3h-.8l.6-.6v1.2M36.6 135.3l-.8 .5M37.7 125.7h.8M37.7 126.3v-.8l.4-.3 .4 .3v.8M38.8 125.7h.6M38.8 125.2h.6l.2 .1-.2 .4 .2 .4-.2 .2h-.6z"/>
<path d="M40 125.7h.6l.1 .4-.1 .2h-.4l-.2-.2zM40.7 125.2l-.7 .5M41.9 125.7h-.8l.6-.5v1.1M42.5 125.2h.3l.2 .1v.8l-.2 .2h-.3l-.2-.2v-.8zM42.7 125.9l.3 .4M43.6 130.7h.6l.2-.2v-.3l-.2-.2h-.6v1.1M43.6 137.8h.6l.2-.2v-.4l-.2-.1h-.6v1.1M43.6 127.2h.6l.2-.2v-.4l-.2-.2h-.6v1.2M43.6 128.9h.6l.2-.1v-.4l-.2-.2h-.6v1.1M43.6 132.5h.6l.2-.2v-.4l-.2-.2h-.6v1.2M43.6 134.3h.6l.2-.2v-.4l-.2-.2h-.6v1.1M43.6 136h.6l.2-.2v-.3l-.2-.2h-.6v1.1"/>
<path d="M43.6 139.6h.6l.2-.2v-.4l-.2-.2h-.6v1.2M44.8 139.2l.4-.4v1.2M44.8 127.6h.8M44.8 129.3h.8M44.8 131.1h.8M44.8 132.9h.8M44.8 134.6h.8M44.8 136.4h.8M44.8 138.2h.8M44.8 126.8l.4-.4v1.2M44.8 140h.8M44.8 128.6l.4-.4v1.1"/>
<path d="M44.8 133.9l.4-.4v1.1M44.8 135.7l.4-.4v1.1M44.8 130.3l.4-.3v1.1M44.8 132.1l.4-.4v1.2M44.8 137.4l.4-.3v1.1M45.9 127h.8M45.9 128.8h.8M45.9 130.5h.8M45.9 132.3h.8M45.9 134.1h.8M45.9 135.8h.8M45.9 137.6h.8"/>
<path d="M45.9 139.4h.8M47.1 130h.5l.2 .2-.2 .3 .2 .4-.2 .2h-.5zM47.1 126.4h.5l.2 .2-.2 .4 .2 .4-.2 .2h-.5zM47.1 127h.5M47.1 128.2h.5l.2 .2-.2 .4 .2 .3-.2 .2h-.5zM47.1 128.8h.5M47.1 130.5h.5M47.1 131.7h.5l.2 .2-.2 .4 .2 .4-.2 .2h-.5zM47.1 132.3h.5M47.1 133.5h.5l.2 .2-.2 .4 .2 .4-.2 .1h-.5zM47.1 134.1h.5M47.1 135.3h.5l.2 .2-.2 .3 .2 .4-.2 .2h-.5z"/>
<path d="M47.1 135.8h.5M47.1 137.1h.5l.2 .1-.2 .4 .2 .4-.2 .2h-.5zM47.1 137.6h.5M47.1 138.8h.5l.2 .2-.2 .4 .2 .4-.2 .2h-.5zM47.1 139.4h.5M48.2 126.8l.4-.4v1.2M48.2 135.8h.6l.2 .4-.2 .2h-.4l-.2-.2zM48.2 127.6h.8M48.2 128.4l.2-.2h.4l.2 .2v.2l-.8 .7h.8M48.2 130.2l.2-.2h.4l.2 .2-.2 .3M48.2 137.1h.8v.1l-.8 .8v.2M48.4 139.4l-.2-.2 .2-.4h.4l.2 .2-.2 .4"/>
<path d="M48.4 139.4l-.2 .2 .2 .4h.4l.2-.2-.2-.4M48.4 139.4h.4M48.6 130.5h.2M48.8 130.5l.2 .2-.2 .4h-.4l-.2-.2M49 133.5h-.8v.6l.4-.2 .4 .2v.4l-.2 .1h-.4l-.2-.1M49 132.3h-.8l.6-.6v1.2M49 135.3l-.8 .5M57.3 126.6h.6l.2-.2v-.3l-.2-.2h-.6v1.1M57.8 120.4l.2-.2h.4l.2 .2v.2l-.8 .7h.8M58.4 125.9h.8M58.8 125.9v1.1M59 121.2h.2v.1h-.2z"/>
<path d="M60.3 120.2h-.8v.6l.4-.2 .4 .2v.4l-.2 .1h-.4l-.2-.1M60.3 126.1l-.1-.2h-.4l-.2 .2v.7l.2 .2h.4l.1-.2M60.7 121.3v-.7l.4-.4 .3 .4v.7M60.7 120.8h.7M114.6 132h.5l.2-.2v-.4l-.2-.2h-.5v1.1M114.6 139.4v-1.1l.3 .4 .4-.4v1.1M115.3 134.9l-.2-.2h-.4l-.1 .2v.8l.1 .2h.4l.2-.2M115.3 129.6l-.2-.2h-.4l-.1 .2v.8l.1 .2h.4l.2-.2M115.3 127.8l-.2-.1h-.4l-.1 .1v.8l.1 .2h.4l.2-.2M115.3 133.2l-.2-.2h-.4l-.1 .2v.7l.1 .2h.4l.2-.2M115.7 138.5l.2-.2h.4l.2 .2v.7l-.2 .2h-.4l-.2-.2zM115.7 129.6l.2-.2h.4l.2 .2v.8l-.2 .2h-.4l-.2-.2z"/>
<path d="M115.7 127.8l.2-.1h.4l.2 .1v.8l-.2 .2h-.4l-.2-.2zM115.7 135.9v-.8l.4-.4 .4 .4v.8M115.7 131.2v1.1l.4-.3 .4 .3v-1.1M115.7 134.1v-.8l.4-.3 .4 .3v.8M115.7 133.5h.8M115.7 135.3h.8M116.8 138.3h.6l.2 .2v.7l-.2 .2h-.6zM116.8 132h.6l.2-.2v-.4l-.2-.2h-.6v1.1M117.2 132l.4 .3M117.6 127.7v1.1l-.8-1.1v1.1M117.6 129.4v1.2l-.8-1.2v1.2M117.6 133v1.1l-.8-1.1v1.1"/>
<path d="M117.6 134.7v1.2l-.8-1.2v1.2M118 138.9h.7M118 131.8h.7M118 133.5h.7M118 135.3h.7M118.7 127.8l-.1-.1h-.4l-.2 .3 .2 .2h.4l.1 .4-.1 .2h-.4l-.2-.2M118.7 129.6l-.1-.2h-.4l-.2 .4 .2 .2h.4l.1 .4-.1 .2h-.4l-.2-.2M119.1 135.5h.6l.2-.2v-.4l-.2-.2h-.6v1.2M119.1 139.4v-.7l.4-.4 .4 .4v.7M119.1 130h.8M119.1 128.2h.8M119.1 138.9h.8"/>
<path d="M119.1 133h.8M119.5 133v1.1M119.5 135.5l.4 .4M119.9 131.4l-.2-.2h-.4l-.2 .2 .2 .4h.4l.2 .2-.2 .3h-.4l-.2-.2M120.3 127.7h.7M120.3 130.2h.5l.2-.2v-.4l-.2-.2h-.5v1.2M120.3 138.5l.2-.2h.3l.2 .2-.2 .4M120.3 131.8h.3M120.3 133l.7 1.1M120.3 134.7l.7 1.2M120.6 127.7v1.1M120.6 130.2l.4 .4"/>
<path d="M120.6 138.9h.2M120.8 138.9l.2 .1-.2 .4h-.3l-.2-.2M121 131.2h-.7v1.1h.7M121 133l-.7 1.1M121 134.7l-.7 1.2M121.4 127.7l.8 1.1M121.4 129.4l.8 1.2M122.2 131.2v1.1l-.8-1.1v1.1M122.2 127.7l-.8 1.1M122.2 129.4l-.8 1.2M123.3 131.4l-.2-.2h-.4l-.1 .2 .1 .4h.4l.2 .2-.2 .3h-.4l-.1-.2M123.7 131.8h.4"/>
<path d="M124.4 131.2h-.7v1.1h.7M141 139.5h.5l.1 .3-.4 .2-.2-.2zM141 132.1l.2-.2h.3l.1 .2v.1l-.6 .7h.6M141 133.8l.2-.1h.3l.1 .1-.1 .4M141 130.5l.3-.4v1M141 131.1h.6M141.3 134.2h.2M141.5 134.2l.1 .1-.1 .3h-.3l-.2-.1M141.6 128.5v.7l-.1 .1h-.3l-.2-.1M141.6 137.2h-.6v.5l.3-.2 .3 .2v.3l-.1 .2h-.3l-.2-.2M141.6 128.5l-.1-.1-.5 .1v.7M141.6 139l-.6 .5"/>
<path d="M141.6 135.9h-.6l.5-.5v1M141.6 128.5l-.6 .7M142.6 139l-.6 1M142.6 137.2l-.6 1M142.6 135.4l-.6 1M142.6 133.7l-.6 .9M142.6 130.1l-.6 1M142.6 128.4l-.6 .9M142.9 139.6h.5l.2-.1v-.4l-.2-.1h-.5v1M142.9 137.9h.5l.2-.2v-.3l-.2-.2h-.5v1M142.9 129h.5l.2-.2v-.3l-.2-.1h-.5v.9M142.9 130.1h.7"/>
<path d="M143.3 130.1v1M143.3 129l.3 .3M143.6 133.8l-.2-.1h-.3l-.2 .1v.7l.2 .1h.3l.2-.1M143.6 135.6l-.2-.2-.5 .2v.6l.2 .2h.3l.2-.2M143.9 134.6v-.6l.4-.3 .3 .3v.6M143.9 136.4v-.6l.4-.4 .3 .4v.6M143.9 137.2v1l.4-.3 .3 .3v-1M143.9 139v1l.4-.4 .3 .4v-1M143.9 135.9h.7M143.9 134.2h.7M143.9 130.1l.7 1M143.9 128.4l.7 .9"/>
<path d="M144.6 130.1l-.7 1M144.6 128.4l-.7 .9M144.9 128.7l.3-.3v.9M144.9 129.3h.7M144.9 138.2v-1l.3 .3 .4-.3v1M144.9 140v-1l.3 .3 .4-.3v1M144.9 131.1h.7M144.9 130.5l.3-.4v1M145.6 133.7v.9l-.7-.9v.9M145.6 135.4v1l-.7-1v1M145.9 135.9h.6M145.9 134.2h.6"/>
<path d="M146.5 130.1l-.6 1M146.5 128.4l-.6 .9M146.9 136.1h.5l.1-.5-.1-.2h-.5v1M146.9 133.7h.6M146.9 130.1h.6M146.9 128.4h.6M147.2 128.4v.9M147.2 130.1v1M147.2 133.7v.9M147.2 136.1l.3 .3M147.8 135.4l.7 1M147.8 133.7l.7 .9"/>
<path d="M147.9 123.6v.6l.1 .1 .4-.1v-.6M148.5 135.4l-.7 1M148.5 133.7l-.7 .9M149.2 123.6h-.5v.4l.2-.2 .3 .2-.1 .3-.4-.1M149.5 135.4l-.7 1M149.5 133.7l-.7 .9M149.8 136.1h.5l.2-.2v-.3l-.2-.2h-.5v1M149.8 134.3h.5l.2-.1v-.4l-.2-.1h-.5v.9M150.8 133.7v.9l.3-.3 .3 .3v-.9M150.8 135.4v1l.3-.3 .3 .3v-1M151.8 134.6v-.9l.3 .3 .3-.3v.9M151.8 136.4v-1l.3 .4 .3-.4v1"/>
<path d="M158.6 126.6v.6l.4 .4 .3-.4v-.6M158.6 131.9v.6l.4 .4 .3-.4v-.6M159.1 130.3l.5-.2 .2 .2-.2 .3M159.4 130.6h.2M159.6 131.9h.5l.2 .2-.2 .3 .2 .3-.2 .2h-.5zM159.6 126.6v.8l.2 .2h.3l.2-.2v-.8M159.6 130.6l.2 .2-.2 .3h-.3l-.2-.2M159.6 137.9h.5l.2-.2v-.3l-.2-.2h-.5v1M159.6 132.4h.5M159.9 128.4v.6l.4 .3 .3-.3v-.6M160.1 130.9h.2v.2h-.2zM160.3 133.8l-.2-.1h-.3l-.2 .1v.7l.2 .1h.3l.2-.1v-.3h-.4"/>
<path d="M160.6 130.3l.5-.2 .1 .2-.1 .3M160.6 132.9v-.7l.3-.3 .3 .3v.7M160.6 132.4h.6M160.9 129.3h.3M160.9 128.4h.3M160.9 130.6h.2M161.1 130.6l.1 .2-.1 .3h-.4l-.1-.2M161.1 128.4v.9M161.2 137.4l-.1-.2-.5 .2v.6l.1 .2h.4l.1-.2v-.3h-.3M161.2 126.7l-.1-.1h-.4l-.1 .1 .1 .4h.4l.1 .1-.1 .4h-.4l-.1-.2M161.2 133.7v.9l-.6-.9v.9M161.6 126.6h.5l.1 .1-.1 .4 .1 .3-.1 .2h-.5z"/>
<path d="M161.6 133.7h.5l.1 .1v.7l-.1 .1h-.5zM161.6 131.9h.6M161.6 130.1v.7l.3 .3 .3-.3v-.7M161.6 138.2v-1l.3 .3 .3-.3v1M161.6 127.1h.5M161.9 131.9v1M162.2 128.4v.9l-.6-.9v.9M175.3 121h.3M209.6 130.5v.7l.4 .4 .3-.4v-.7M210.7 131.6h.4M210.7 130.5h.4M210.9 130.5v1.1"/>
<path d="M212.2 130.5v1.1l-.7-1.1v1.1M223.6 136.6l.5-.2 .2 .2-.2 .3M223.9 136.9h.2M224.1 136.9l.2 .2-.2 .3h-.3l-.2-.2M227.8 137.2v.7l.4 .3 .3-.3v-.7M228.8 137.2h.5l.2 .2v.6l-.2 .2h-.5zM229.8 137.2h.5l.2 .2v.6l-.2 .2h-.5zM231.6 131.1v1.1l.2 .2h.5l.2-.2v-1.1M233.8 131.7h-.9l.7-.6v1.3M238.4 139v.6l.3 .4 .4-.4v-.6M239.4 137.9h.5l.1-.2v-.3l-.1-.2h-.5v1M239.4 139.6h.5l.1-.1v-.4l-.1-.1h-.5v1"/>
<path d="M239.7 137.9l.3 .3M239.7 139.6l.3 .4M240.3 137.2l.7 1M240.3 139.5h.4M241 139h-.7v1h.7M241 137.2l-.7 1M241.3 137.2h.5l.2 .2v.6l-.2 .2h-.5zM241.3 139.5h.4M242 139h-.7v1M246.2 136.9h-.6l.5-.5v1M246.2 138.2h-.6v.5l.3-.2 .3 .2v.3l-.1 .2-.5-.2M13.5 159.6v1.1h.8"/>
<path d="M15.4 159.7l-.2-.1h-.4l-.2 .1v.8l.2 .2h.4l.2-.2M17.7 159.6v1.1l-.8-1.1v1.1M19.2 159.6v1.1M20 159.6v1.1M31.2 141.4h.6l.2-.2v-.4l-.2-.2h-.6v1.1M31.2 143.1h.6l.2-.2v-.3l-.2-.2h-.6v1.1M31.2 144.9h.6l.2-.2v-.4l-.2-.2h-.6v1.2M31.2 146.7h.6l.2-.2v-.4l-.2-.2h-.6v1.1M31.2 148.4h.6l.2-.1v-.4l-.2-.2h-.6v1.1M31.2 150.2h.6l.2-.2v-.4l-.2-.1h-.6v1.1M31.2 152h.6l.2-.2v-.4l-.2-.2h-.6v1.2M31.2 153.8h.6l.2-.2v-.4l-.2-.2h-.6v1.1"/>
<path d="M31.2 155.5h.6l.2-.2v-.3l-.2-.2h-.6v1.1M31.2 157.3h.6l.2-.2v-.4l-.2-.2h-.6v1.2M31.2 159.1h.6l.2-.2v-.4l-.2-.2h-.6v1.1M32.4 151.6l.4-.4v1.2M32.4 158.7l.4-.4v1.1M32.4 141l.4-.4v1.1M32.4 142.7l.4-.3v1.1M32.4 144.5l.4-.4v1.2M32.4 146.3l.4-.4v1.1M32.4 148.1l.4-.4v1.1M32.4 149.8l.4-.3v1.1M32.4 153.4l.4-.4v1.1"/>
<path d="M32.4 155.2l.4-.4v1.1M32.4 156.9l.4-.4v1.2M32.4 141.7h.7M32.4 143.5h.7M32.4 145.3h.7M32.4 147h.7M32.4 148.8h.7M32.4 150.6h.7M32.4 152.4h.7M32.4 154.1h.7M32.4 155.9h.7M32.4 157.7h.7"/>
<path d="M32.4 159.4h.7M33.5 141.2h.8M33.5 142.9h.8M33.5 144.7h.8M33.5 146.5h.8M33.5 148.3h.8M33.5 150h.8M33.5 151.8h.8M33.5 153.6h.8M33.5 155.3h.8M33.5 157.1h.8M33.5 158.9h.8"/>
<path d="M34.7 150.6v-.8l.4-.3 .3 .3v.8M34.7 152.4v-.8l.4-.4 .3 .4v.8M34.7 159.4v-.7l.4-.4 .3 .4v.7M34.7 141.7v-.7l.4-.4 .3 .4v.7M34.7 143.5v-.8l.4-.3 .3 .3v.8M34.7 145.3v-.8l.4-.4 .3 .4v.8M34.7 147v-.7l.4-.4 .3 .4v.7M34.7 148.8v-.7l.4-.4 .3 .4v.7M34.7 154.1v-.7l.4-.4 .3 .4v.7M34.7 155.9v-.7l.4-.4 .3 .4v.7M34.7 157.7v-.8l.4-.4 .3 .4v.8M34.7 141.2h.7"/>
<path d="M34.7 142.9h.7M34.7 144.7h.7M34.7 146.5h.7M34.7 148.3h.7M34.7 150h.7M34.7 151.8h.7M34.7 153.6h.7M34.7 155.3h.7M34.7 157.1h.7M34.7 158.9h.7M35.8 149.8l.4-.3v1.1M35.8 142.7l.4-.3v1.1"/>
<path d="M35.8 144.5l.4-.4v1.2M35.8 146.3l.4-.4v1.1M35.8 148.1l.4-.4v1.1M35.8 151.6l.4-.4v1.2M35.8 153.4l.4-.4v1.1M35.8 155.2l.4-.4v1.1M35.8 156.9l.4-.4v1.2M35.8 158.7l.4-.4v1.1M35.8 143.5h.8M35.8 145.3h.8M35.8 147h.8M35.8 148.8h.8"/>
<path d="M35.8 150.6h.8M35.8 152.4h.8M35.8 154.1h.8M35.8 155.9h.8M35.8 157.7h.8M35.8 159.4h.8M36.6 141.2h-.6l-.2-.2 .2-.4h.4l.2 .2v.7l-.2 .2h-.4l-.2-.2M37 144.5l.3-.4v1.2M37 146.1l.1-.2h.4l.2 .2v.2l-.7 .7h.7M37 147.9l.1-.2h.4l.2 .2-.2 .4M37 153.6h.5l.2 .3-.2 .2h-.4l-.1-.2zM37 154.8h.7v.2l-.7 .7v.2"/>
<path d="M37 145.3h.7M37.1 157.1l-.1-.2 .1-.4h.4l.2 .2-.2 .4M37.1 157.1l-.1 .2 .1 .4h.4l.2-.2-.2-.4M37.1 157.1h.4M37.3 148.3h.2M37.5 148.3l.2 .1-.2 .4h-.4l-.1-.2M37.7 142.6v.7l-.2 .2h-.4l-.1-.2M37.7 151.2h-.7v.6l.5-.2 .2 .2v.4l-.2 .2h-.4l-.1-.2M37.7 158.9h-.6l-.1-.2 .1-.4h.4l.2 .2v.8l-.2 .1h-.4l-.1-.1M37.7 142.6l-.2-.2h-.4l-.1 .2v.7M37.7 142.6l-.7 .7M37.7 150h-.7l.5-.5v1.1"/>
<path d="M37.7 153l-.7 .6M43.6 155.5h.6l.2-.2v-.3l-.2-.2h-.6v1.1M43.6 150.2h.6l.2-.2v-.4l-.2-.1h-.6v1.1M43.6 141.4h.6l.2-.2v-.4l-.2-.2h-.6v1.1M43.6 143.1h.6l.2-.2v-.3l-.2-.2h-.6v1.1M43.6 144.9h.6l.2-.2v-.4l-.2-.2h-.6v1.2M43.6 157.3h.6l.2-.2v-.4l-.2-.2h-.6v1.2M43.6 146.7h.6l.2-.2v-.4l-.2-.2h-.6v1.1M43.6 148.4h.6l.2-.1v-.4l-.2-.2h-.6v1.1M43.6 152h.6l.2-.2v-.4l-.2-.2h-.6v1.2M43.6 159.1h.6l.2-.2v-.4l-.2-.2h-.6v1.1M43.6 153.8h.6l.2-.2v-.4l-.2-.2h-.6v1.1"/>
<path d="M44.8 146.3l.4-.4v1.1M44.8 153.4l.4-.4v1.1M44.8 141.7h.8M44.8 143.5h.8M44.8 145.3h.8M44.8 147h.8M44.8 148.8h.8M44.8 141l.4-.4v1.1M44.8 150.6h.8M44.8 152.4h.8M44.8 154.1h.8M44.8 142.7l.4-.3v1.1"/>
<path d="M44.8 155.9h.8M44.8 157.7h.8M44.8 149.8l.4-.3v1.1M44.8 159.4h.8M44.8 148.1l.4-.4v1.1M44.8 151.6l.4-.4v1.2M44.8 156.9l.4-.4v1.2M44.8 158.7l.4-.4v1.1M44.8 155.2l.4-.4v1.1M44.8 144.5l.4-.4v1.2M45.9 141.2h.8M45.9 142.9h.8"/>
<path d="M45.9 144.7h.8M45.9 146.5h.8M45.9 148.3h.8M45.9 150h.8M45.9 151.8h.8M45.9 153.6h.8M45.9 155.3h.8M45.9 157.1h.8M45.9 158.9h.8M47.1 142.4h.5l.2 .2-.2 .3 .2 .4-.2 .2h-.5zM47.1 140.6h.5l.2 .2-.2 .4 .2 .3-.2 .2h-.5zM47.1 141.2h.5"/>
<path d="M47.1 142.9h.5M47.1 144.1h.5l.2 .2-.2 .4 .2 .4-.2 .2h-.5zM47.1 144.7h.5M47.1 145.9h.5l.2 .2-.2 .4 .2 .4-.2 .1h-.5zM47.1 146.5h.5M47.1 147.7h.5l.2 .2-.2 .4 .2 .3-.2 .2h-.5zM47.1 148.3h.5M47.1 149.5h.5l.2 .1-.2 .4 .2 .4-.2 .2h-.5zM47.1 150h.5M47.1 151.2h.5l.2 .2-.2 .4 .2 .4-.2 .2h-.5zM47.1 151.8h.5M47.1 153h.5l.2 .2-.2 .4 .2 .3-.2 .2h-.5z"/>
<path d="M47.1 153.6h.5M47.1 154.8h.5l.2 .2-.2 .3 .2 .4-.2 .2h-.5zM47.1 155.3h.5M47.1 156.5h.5l.2 .2-.2 .4 .2 .4-.2 .2h-.5zM47.1 157.1h.5M47.1 158.3h.5l.2 .2-.2 .4 .2 .4-.2 .1h-.5zM47.1 158.9h.5M48.2 142.7l.4-.3v1.1M48.2 144.5l.4-.4v1.2M48.2 146.3l.4-.4v1.1M48.2 148.1l.4-.4v1.1M48.2 149.8l.4-.3v1.1"/>
<path d="M48.2 151.6l.4-.4v1.2M48.2 153.4l.4-.4v1.1M48.2 155.2l.4-.4v1.1M48.2 156.9l.4-.4v1.2M48.2 158.7l.4-.4v1.1M48.2 143.5h.8M48.2 145.3h.8M48.2 147h.8M48.2 148.8h.8M48.2 150.6h.8M48.2 152.4h.8M48.2 154.1h.8"/>
<path d="M48.2 155.9h.8M48.2 157.7h.8M48.2 159.4h.8M49 141.2h-.6l-.2-.2 .2-.4h.4l.2 .2v.7l-.2 .2h-.4l-.2-.2M49.4 147.9l.2-.2h.3l.2 .2-.2 .4M49.4 145.3h.7M49.4 146.1l.2-.2h.3l.2 .2v.2l-.7 .7h.7M49.4 153.6h.5l.2 .3-.2 .2h-.3l-.2-.2zM49.4 154.8h.7v.2l-.7 .7v.2M49.4 144.5l.3-.4v1.2M49.6 157.1l-.2-.2 .2-.4h.3l.2 .2-.2 .4M49.6 157.1l-.2 .2 .2 .4h.3l.2-.2-.2-.4"/>
<path d="M49.6 157.1h.3M49.7 148.3h.2M49.9 148.3l.2 .1-.2 .4h-.3l-.2-.2M50.1 142.6l-.2-.2h-.3l-.2 .2v.7M50.1 142.6v.7l-.2 .2h-.3l-.2-.2M50.1 158.9h-.5l-.2-.2 .2-.4h.3l.2 .2v.8l-.2 .1h-.3l-.2-.1M50.1 150h-.7l.5-.5v1.1M50.1 151.2h-.7v.6l.3-.2 .4 .2v.4l-.2 .2h-.3l-.2-.2M50.1 142.6l-.7 .7M50.1 153l-.7 .6M114.6 144.7v-1.1l.3 .4 .4-.4v1.1M114.6 141.2v-1.1l.3 .3 .4-.3v1.1"/>
<path d="M114.6 152.5h.3M114.6 153.6h.3M114.6 143v-1.2l.3 .4 .4-.4v1.2M114.7 152.5v1.1M115.3 152.5h.6l.2 .2v.7l-.2 .2h-.6zM115.3 154.4l-.2-.2h-.4l-.1 .2v.8l.1 .2h.4l.2-.2M115.3 156v1.1l-.7-1.1v1.1M115.3 157.8v1.1l-.7-1.1v1.1M115.3 159.6v1.1l-.7-1.1v1.1M115.7 156.2l.2-.2h.4l.2 .2v.8l-.2 .1h-.4l-.2-.1zM115.7 155.4v-.8l.4-.4 .4 .4v.8M115.7 140.3l.2-.2h.4l.2 .2v.7l-.2 .2h-.4l-.2-.2z"/>
<path d="M115.7 159.7l.2-.1h.4l.2 .1v.8l-.2 .2h-.4l-.2-.2zM115.7 143.8l.2-.2h.4l.2 .2v.7l-.2 .2h-.4l-.2-.2zM115.7 142l.2-.2h.4l.2 .2v.8l-.2 .2h-.4l-.2-.2zM115.7 154.8h.8M115.9 157.8h.4l.2 .2v.7l-.2 .2h-.4l-.2-.2v-.7zM116.5 153h.3M116.8 141.8h.6l.2 .2v.8l-.2 .2h-.6zM116.8 156h.6l.2 .2v.8l-.2 .1h-.6zM116.8 159.6h.6l.2 .1v.8l-.2 .2h-.6zM116.8 140.1h.6l.2 .2v.7l-.2 .2h-.6zM116.8 143.6h.6l.2 .2v.7l-.2 .2h-.6zM116.8 157.8h.6l.2 .2v.7l-.2 .2h-.6z"/>
<path d="M117.2 152.5h-.7v1.1h.7M117.6 154.2v1.2l-.8-1.2v1.2M118 156.6h.4M118 144.2h.7M118 142.4h.7M118 158.3h.4M118 140.6h.7M118 154.8h.7M118.4 152.5v1.1l-.8-1.1v1.1M118.7 152.5h.8M118.7 159.6h-.7v1.1h.7M118.7 156h-.7v1.1h.7"/>
<path d="M118.7 157.8h-.7v1.1h.7M119.1 141.2v-.8l.4-.3 .4 .3v.8M119.1 143v-.8l.4-.4 .4 .4v.8M119.1 144.7v-.7l.4-.4 .4 .4v.7M119.1 155.4v-.8l.4-.4 .4 .4v.8M119.1 156.6h.8M119.1 144.2h.8M119.1 142.4h.8M119.1 152.5v1.1M119.1 158.3h.8M119.1 140.6h.8M119.1 154.8h.8"/>
<path d="M119.9 152.5h.4M119.9 153.6h.4M120.1 152.5v1.1M120.3 143h.7M120.3 156.6h.7M120.3 142.2l.3-.4v1.2M120.3 157.1v-.7l.3-.4 .4 .4v.7M120.3 158.9v-.7l.3-.4 .4 .4v.7M120.3 140.3l.2-.2h.3l.2 .2v.1l-.7 .8h.7M120.3 158.3h.7M120.6 153h.4M121 154.4l-.2-.2h-.3l-.2 .2v.8l.2 .2h.3l.2-.2"/>
<path d="M121 143.8v.7l-.2 .2h-.3l-.2-.2M121 143.8l-.2-.2h-.3l-.2 .2v.7M121 143.8l-.7 .7M121.4 152.5h-.8v1.1M121.4 159.7l.2-.1h.4l.2 .1v.2l-.8 .8h.8M121.4 158.9h.8M121.4 158.2l.4-.4v1.1M121.4 154.2h.8M121.8 152.5v.2l.4 .3M121.8 154.2v1.2M122.2 156.2l-.2-.2h-.4l-.2 .2v.8M122.2 156.2v.8l-.2 .1h-.4l-.2-.1"/>
<path d="M122.2 156.2l-.8 .8M122.2 153v.6M122.5 152.5v.2l-.3 .3M141 140.8h.6l-.6 .9M141 147h.6M141 148.8h.6M141 150.6h.6M141 152.4h.6M141 154.1h.6M141 155.9h.6M141 159.4h.6M141 149.9l.3-.3v1"/>
<path d="M141 146.4l.3-.3v.9M141 148.2l.3-.4v1M141 151.7l.3-.3v1M141 153.5l.3-.3v.9M141 155.3l.3-.4v1M141 157l.3-.3v1M141 158.8l.3-.3v.9M141 157.7h.6M141.2 143l-.2-.1 .2-.4 .4 .2-.1 .3M141.2 143l-.2 .2 .2 .3h.3l.1-.2-.1-.3M141.2 143h.3M141.6 144.8h-.4l-.2-.2 .2-.3h.3l.1 .2v.6l-.1 .2h-.3l-.2-.2"/>
<path d="M142 151.6l.1-.2h.4l.1 .2-.1 .3M142 148.8h.6M142 149.8l.1-.2 .5 .2v.1l-.6 .7h.6M142 157.2h.5l.1 .3-.1 .2h-.4l-.1-.2zM142 158.5h.6l-.6 .9M142 148.2l.3-.4v1M142.3 151.9h.2M142.5 151.9l.1 .1-.1 .4h-.4l-.1-.2M142.6 154.9h-.6v.5l.3-.1 .3 .1v.3l-.1 .2h-.4l-.1-.2M142.6 156.7l-.6 .5M142.6 146.2v.7l-.1 .1-.5-.1M142.6 146.2l-.1-.1h-.4l-.1 .1v.7"/>
<path d="M142.6 146.2l-.6 .7M142.6 144.3l-.6 1M142.6 142.5l-.6 1M142.6 140.8l-.6 .9M142.6 153.6h-.6l.5-.4v.9M142.9 141.4h.5l.2-.2v-.3l-.2-.1h-.5v.9M142.9 142.5h.7M142.9 144.9h.5l.2-.1v-.3l-.2-.2h-.5v1M143.3 144.9l.3 .4M143.3 142.5v1M143.3 141.4l.3 .3M143.6 149.6l-.7 1"/>
<path d="M143.6 147.8l-.7 1M143.6 146.1l-.7 .9M143.6 158.5l-.7 .9M143.6 156.7l-.7 1M143.6 154.9l-.7 1M143.6 153.2l-.7 .9M143.6 151.4l-.7 1M143.9 155.9v-.6l.4-.4 .3 .4v.6M143.9 148.8v-1l.4 .4 .3-.4v1M143.9 150.6v-1l.4 .3 .3-.3v1M143.9 146.1h.7M143.9 154.1v-.6l.4-.3 .3 .3v.6"/>
<path d="M143.9 157.7v-.7l.4-.3 .3 .3v.7M143.9 159.4v-.6l.4-.3 .3 .3v.6M143.9 144.3l.7 1M143.9 142.5l.7 1M143.9 140.8l.7 .9M143.9 159h.7M143.9 157.2h.7M143.9 155.4h.7M143.9 153.6h.7M144.3 146.1v.9M144.6 151.6l-.2-.2h-.3l-.2 .2 .2 .3h.3l.2 .1-.2 .4h-.3l-.2-.2M144.6 144.3l-.7 1"/>
<path d="M144.6 142.5l-.7 1M144.6 140.8l-.7 .9M144.9 144.5l.2-.2h.3l.2 .2v.1l-.7 .7h.7M144.9 148l.2-.2h.3l.2 .2v.7l-.2 .1h-.3l-.2-.1zM144.9 150.6h.3M144.9 155.9h.7M144.9 140.9l.2-.1h.3l.2 .1-.2 .3M144.9 142.7l.5-.2 .2 .2-.2 .3M144.9 149.6h.3M144.9 156.9l.2-.2 .5 .2v.1l-.7 .7h.7M144.9 158.6l.2-.1h.3l.2 .1-.2 .4M144.9 146.1l.7 .9"/>
<path d="M144.9 155.3l.3-.4v1M145.1 149.6v1M145.2 143h.2M145.2 141.2h.2M145.2 159h.2M145.4 141.2l.2 .2-.2 .3h-.3l-.2-.1M145.4 143l.2 .2-.2 .3h-.3l-.2-.2M145.4 159l.2 .1-.2 .3-.5-.1M145.6 153.3l-.2-.1h-.3l-.2 .1v.7M145.6 151.6l-.2-.2h-.3l-.2 .2v.6l.2 .2h.3l.2-.2M145.6 153.3v.7l-.2 .1-.5-.1M145.6 146.1l-.7 .9"/>
<path d="M145.6 153.3l-.7 .7M145.9 146.2l.1-.1h.4l.1 .1v.2l-.6 .6h.6M145.9 151.4v1M146 151.9l.5 .5M146.2 149.8l-.5-.2-.1 .3 .1 .2h.3l.2 .3-.2 .2h-.3l-.1-.2M146.5 149.8l.2-.2 .5 .2v.6l-.2 .2h-.3l-.2-.2zM146.5 148l-.1-.2h-.4l-.1 .2 .1 .3h.4l.1 .2-.1 .3h-.4l-.1-.1M146.5 144.3l-.6 1M146.5 158.5l-.6 .9M146.5 156.7l-.6 1M146.5 154.9l-.6 1M146.5 151.4l-.6 .6"/>
<path d="M146.9 148.8h.3M146.9 144.9h.5l.1-.1-.1-.5h-.5v1M146.9 147.8h.3M146.9 158.5h.6M146.9 156.7h.6M146.9 154.9h.6M147 147.8v1M147.2 154.9v1M147.2 156.7v1M147.2 158.5v.9M147.5 146.1l-.6 .9M147.5 151.4l-.6 1"/>
<path d="M147.8 151.4v1h.7M147.8 146.7h.5l.2-.1-.2-.5h-.5v.9M147.8 144.3v1l.4-.4 .3 .4v-1M148.8 151.9h.3M148.8 145.3v-1l.3 .3 .4-.3v1M148.8 146.1v.9l.3-.3 .4 .3v-.9M149.5 151.4h-.7v1h.7M149.8 151.4h.5l.2 .2v.6l-.2 .2h-.5zM149.8 147v-.9l.3 .3 .4-.3v.9M155.7 146.6h.6M155.7 147v-.6l.3-.3 .3 .3v.6M156.7 146.4l.3-.3v.9"/>
<path d="M156.7 147h.6M158.3 146.6h-.7l.5-.5v.9M158.6 141.7v-.6l.4-.3 .3 .3v.6M158.6 143.5v-.6l.4-.4 .3 .4v.6M158.6 143h.7M158.6 141.2h.7M159.3 146.1l-.7 .9M159.6 151.9h.7M159.6 146.1h.5l.2 .1v.7l-.2 .1h-.5zM159.6 141.4h.5l.2-.2v-.3l-.2-.1h-.5v.9M159.6 152.4v-.7l.3-.3 .4 .3v.7M159.6 154.1v-.6l.3-.3 .4 .3v.6"/>
<path d="M159.6 153.6h.7M159.9 141.4l.4 .3M160.3 142.7l-.2-.2-.5 .2v.6l.2 .2h.3l.2-.2v-.3h-.4M160.6 152.4h.6M160.6 154.1h.6M160.6 146.6h.6M160.6 141.2h.3M160.6 147v-.6l.3-.3 .3 .3v.6M160.6 153.5l.3-.3v.9M160.6 151.7l.3-.3v1M161.2 140.8h-.6v.9h.6M161.2 142.5v1l-.6-1v1"/>
<path d="M161.6 142.5h.5l.1 .2v.6l-.1 .2h-.5zM161.6 152.4h.6M161.6 141.2h.3M161.6 151.7l.3-.3v1M162.2 153.3l-.1-.1h-.4l-.1 .1v.7M162.2 146.2l-.1-.1h-.4l-.1 .1v.7l.1 .1 .5-.1M162.2 153.3v.7l-.1 .1-.5-.1M162.2 140.8h-.6v.9M162.2 153.3l-.6 .7M200.4 140.3l-.2-.2h-.4l-.2 .2v.7l.2 .2h.4l.2-.2M200.4 156.2l-.2-.2h-.4l-.2 .2v.8l.2 .1h.4l.2-.1M200.8 141.2v-.8l.4-.3 .3 .3v.8"/>
<path d="M200.8 157.1v-.7l.4-.4 .3 .4v.7M200.8 156.6h.7M200.8 140.6h.7M202.2 152.7l-.2-.2h-.4l-.2 .2v.7l.2 .2h.4l.2-.2v-.4h-.4M202.7 140.1v1.1l-.8-1.1v1.1M202.7 156v1.1l-.8-1.1v1.1M203.1 156.6h.7M203.1 140.6h.7M203.3 152.5v1.1l-.8-1.1v1.1M203.7 152.5h.6l.1 .2v.7l-.1 .2h-.6zM204.2 156.8h.6l.2-.2v-.4l-.2-.2h-.6v1.1M204.2 140.1h.8"/>
<path d="M204.6 140.1v1.1M204.6 156.8l.4 .3M205 147.2l.3-.4v1.1M205 147.9h.7M205 146h.5l.2-.2v-.4l-.2-.2h-.5v1.1M205.3 146l.4 .3M205.4 140.1l.7 1.1M205.4 156l.7 1.1M206.1 140.1l-.7 1.1M206.1 156l-.7 1.1M206.9 147v.7l-.2 .2h-.4l-.2-.2M206.9 145.8h-.6l-.2-.2 .2-.4h.4l.2 .2v.8l-.2 .1h-.4l-.2-.1"/>
<path d="M206.9 147l-.2-.2h-.4l-.2 .2v.7M206.9 147l-.8 .7M207.2 146.8v1.1M207.8 147.2l-.6 .4 .6 .3M209.3 152.7l-.2-.2h-.4l-.2 .2v.7l.2 .2h.4l.2-.2v-.4h-.4M210.4 152.5v1.1l-.8-1.1v1.1M210.8 152.5h.5l.2 .2v.7l-.2 .2h-.5zM211.3 147.3l.4-.4v1.1M211.3 148h.8M212.1 143.5l-.2-.2h-.4l-.2 .2v.8l.2 .2h.4l.2-.2M212.5 143.9h.5l.2 .4-.2 .2h-.3l-.2-.2zM213.2 147.1v.7l-.2 .2h-.3l-.2-.2"/>
<path d="M213.2 147.1l-.2-.2h-.3l-.2 .2v.7M213.2 147.1l-.7 .7M213.2 143.3l-.7 .6M214.4 147.1v.7l-.2 .2h-.4l-.2-.2M214.4 147.1l-.2-.2h-.4l-.2 .2v.7M214.4 147.1l-.8 .7M214.8 148v-.7h.5l.2 .1v.6M215.9 147.4h.4M216.3 152.7l-.1-.2h-.4l-.2 .2v.7l.2 .2h.4l.1-.2v-.4h-.3M216.7 146.9h-.8v1.1M217.5 152.5v1.1l-.8-1.1v1.1M217.9 152.5h.5l.2 .2v.7l-.2 .2h-.5z"/>
<path d="M223.6 140.3l.3-.3v.9M223.6 145.5l.2-.2h.3l.2 .2v.1l-.7 .7h.7M223.6 140.9h.7M223.8 142.2l-.2-.1 .2-.3h.3l.2 .1-.2 .3M223.8 142.2l-.2 .2 .2 .3h.3l.2-.1-.2-.4M223.8 142.2h.3M227.8 143.2h.5l.2-.5-.2-.2h-.5v1M227.8 146.1v.6l.4 .3 .3-.3v-.6M227.8 140.8h.7M228.2 140.8v.9M228.2 143.2l.3 .3M228.8 140.8l.7 .9"/>
<path d="M229.5 142.7l-.2-.2-.5 .2 .2 .3 .5 .2-.2 .3h-.3l-.2-.2M229.5 146.2l-.2-.1h-.3l-.2 .3 .5 .2 .2 .3-.2 .1-.5-.1M229.5 140.8l-.7 .9M229.8 140.8h.5l.2 .1v.7l-.2 .1h-.5zM230.5 146.2l-.2-.1h-.3l-.2 .3 .5 .2 .2 .3-.2 .1-.5-.1M231.1 153.2v-1.4l.5 .5 .4-.5v1.4M233.3 152.1l-.2-.3h-.4l-.2 .3v.8l.2 .3h.4l.2-.3M233.8 152.7h.7l.2-.2v-.4l-.2-.3h-.7v1.4M235.2 152.1l.2-.3h.4l.2 .3v.2l-.8 .9h.8M237.4 151.8h-.9v.7l.7-.2 .2 .2v.4l-.2 .3h-.5l-.2-.3M238.7 151.8h-.9v.7l.5-.2h.2l.2 .2v.4l-.2 .3h-.5l-.2-.3M239.1 142.7l-.2-.2-.5 .2v.6l.1 .2h.4l.2-.2"/>
<path d="M239.1 144.5l-.2-.2h-.4l-.1 .2v.6l.1 .2h.4l.2-.2M239.2 152.3l.4-.5v1.4M239.2 153.2h.9M239.4 143.5v-.6l.3-.4 .3 .4v.6M239.4 145.3v-.7l.3-.3 .3 .3v.7M239.4 143h.6M239.4 144.8h.6M240.5 152.5h.9M241 142.5v1l-.7-1v1M241 144.3v1l-.7-1v1M241.3 142.5v1h.7M241.3 144.3v1"/>
<path d="M241.3 144.8h.7M241.9 151.8h.4M241.9 153.2h.4M242 144.3v1M242.1 151.8v1.4M243.6 151.8l-.9 1.4M244.9 152.1l-.2-.3h-.4l-.2 .3 .2 .4h.4l.2 .2-.2 .5h-.4l-.2-.3M245.6 142.2h.5l.1 .4-.1 .1h-.4l-.1-.1zM245.6 143.5h.6l-.6 1M246.2 141.8l-.6 .4M246.3 151.8v1.4l-.9-1.4v1.4M259.9 141.8v1.2h.8"/>
<path d="M259.9 143.6v1.1h.8M261.8 142l-.2-.2h-.4l-.2 .2v.8l.2 .2h.4l.2-.2M261.8 143.8l-.2-.2h-.4l-.2 .2v.7l.2 .2h.4l.2-.2M262.2 143v-.8l.4-.4 .4 .4v.8M262.2 144.7v-.7l.4-.4 .4 .4v.7M262.2 144.2h.8M262.2 142.4h.8M264.1 141.8v1.2l-.8-1.2v1.2M264.1 143.6v1.1l-.8-1.1v1.1M264.5 144.2h.7M264.5 142.4h.7M265.6 141.8v1.2h.8"/>
<path d="M265.6 143.6v1.1M265.6 144.2h.8M266.4 143.6v1.1M13.5 161.3v1.2h.8M15.4 161.5l-.2-.2h-.4l-.2 .2v.8l.2 .2h.4l.2-.2M15.8 160.7v-.8l.4-.3 .4 .3v.8M15.8 160.1h.8M15.8 162.5v-.8l.4-.4 .4 .4v.8M15.8 161.9h.8M17.7 161.3v1.2l-.8-1.2v1.2M18.1 160.1h.7M18.1 161.9h.7"/>
<path d="M19.2 160.1h.8M19.2 161.3v1.2h.8M31.2 160.8h.6l.2-.1v-.4l-.2-.2h-.6v1.1M31.2 162.6h.6l.2-.2v-.3l-.2-.2h-.6v1.1M31.2 164.4h.6l.2-.2v-.4l-.2-.2h-.6v1.2M31.2 166.2h.6l.2-.2v-.4l-.2-.2h-.6v1.1M31.2 167.9h.6l.2-.2v-.3l-.2-.2h-.6v1.1M31.2 169.7h.6l.2-.2v-.4l-.2-.1h-.6v1.1M31.2 171.5h.6l.2-.2v-.4l-.2-.2h-.6v1.2M31.2 173.2h.6l.2-.1v-.4l-.2-.2h-.6v1.1M31.2 175h.6l.2-.2v-.3l-.2-.2h-.6v1.1M31.2 176.8h.6l.2-.2v-.4l-.2-.2h-.6v1.2"/>
<path d="M31.2 178.6h.6l.2-.2v-.4l-.2-.2h-.6v1.1M32.4 165.8l.4-.4v1.1M32.4 160.5l.4-.4v1.1M32.4 162.2l.4-.3v1.1M32.4 164l.4-.4v1.2M32.4 167.6l.4-.4v1.1M32.4 169.3l.4-.3v1.1M32.4 171.1l.4-.4v1.2M32.4 172.9l.4-.4v1.1M32.4 174.6l.4-.3v1.1M32.4 176.4l.4-.4v1.2M32.4 178.2l.4-.4v1.1"/>
<path d="M32.4 180l.4-.4v1.1M32.4 161.2h.7M32.4 163h.7M32.4 164.8h.7M32.4 166.5h.7M32.4 168.3h.7M32.4 170.1h.7M32.4 171.9h.7M32.4 173.6h.7M32.4 175.4h.7M32.4 177.2h.7M32.4 178.9h.7"/>
<path d="M33.5 160.7h.8M33.5 162.4h.8M33.5 164.2h.8M33.5 166h.8M33.5 167.7h.8M33.5 169.5h.8M33.5 171.3h.8M33.5 173.1h.8M33.5 174.8h.8M33.5 176.6h.8M33.5 178.4h.8M34.7 161.2v-.7l.4-.4 .3 .4v.7"/>
<path d="M34.7 163v-.8l.4-.3 .3 .3v.8M34.7 164.8v-.8l.4-.4 .3 .4v.8M34.7 166.5v-.7l.4-.4 .3 .4v.7M34.7 168.3v-.7l.4-.4 .3 .4v.7M34.7 170.1v-.8l.4-.3 .3 .3v.8M34.7 171.9v-.8l.4-.4 .3 .4v.8M34.7 173.6v-.7l.4-.4 .3 .4v.7M34.7 175.4v-.8l.4-.3 .3 .3v.8M34.7 177.2v-.8l.4-.4 .3 .4v.8M34.7 178.9v-.7l.4-.4 .3 .4v.7M34.7 160.7h.7M34.7 162.4h.7"/>
<path d="M34.7 164.2h.7M34.7 166h.7M34.7 167.7h.7M34.7 169.5h.7M34.7 171.3h.7M34.7 173.1h.7M34.7 174.8h.7M34.7 176.6h.7M34.7 178.4h.7M35.8 160.3l.2-.2h.4l.2 .2v.2l-.8 .7h.8M35.8 162.1l.2-.2h.4l.2 .2v.1l-.8 .8h.8M35.8 163.8l.2-.2h.4l.2 .2v.2l-.8 .8h.8"/>
<path d="M35.8 165.6l.2-.2h.4l.2 .2v.2l-.8 .7h.8M35.8 167.4l.2-.2h.4l.2 .2v.2l-.8 .7h.8M35.8 169.1l.2-.1h.4l.2 .1v.2l-.8 .8h.8M35.8 170.9l.2-.2h.4l.2 .2v.2l-.8 .8h.8M35.8 172.7l.2-.2h.4l.2 .2v.2l-.8 .7h.8M35.8 174.5l.2-.2h.4l.2 .2v.1l-.8 .8h.8M35.8 176.2l.2-.2h.4l.2 .2v.2l-.8 .8h.8M35.8 178l.2-.2h.4l.2 .2-.2 .4M35.8 179.8l.2-.2h.4l.2 .2-.2 .3M36.2 178.4h.2M36.4 178.4l.2 .2-.2 .3h-.4l-.2-.1M37 162.2l.3-.3v1.1"/>
<path d="M37 180l.3-.4v1.1M37 163.8l.1-.2h.4l.2 .2v.2l-.7 .8h.7M37 165.6l.1-.2h.4l.2 .2-.2 .4M37 171.3h.5l.2 .4-.2 .2h-.4l-.1-.2zM37 172.5h.7v.2l-.7 .7v.2M37 163h.7M37.1 174.8l-.1-.2 .1-.3h.4l.2 .2-.2 .3M37.1 174.8l-.1 .2 .1 .4h.4l.2-.2-.2-.4M37.1 174.8h.4M37.3 166h.2M37.5 166l.2 .2-.2 .3h-.4l-.1-.2M37.7 160.3v.7l-.2 .2h-.4l-.1-.2"/>
<path d="M37.7 169h-.7v.5l.5-.2 .2 .2v.4l-.2 .2h-.4l-.1-.2M37.7 176.6h-.6l-.1-.2 .1-.4h.4l.2 .2v.8l-.2 .2h-.4l-.1-.2M37.7 178v.8l-.2 .1h-.4l-.1-.1M37.7 160.3l-.2-.2h-.4l-.1 .2v.7M37.7 178l-.2-.2h-.4l-.1 .2v.8M37.7 167.7h-.7l.5-.5v1.1M37.7 160.3l-.7 .7M37.7 170.7l-.7 .6M37.7 178l-.7 .8M43.6 167.9h.6l.2-.2v-.3l-.2-.2h-.6v1.1M43.6 162.6h.6l.2-.2v-.3l-.2-.2h-.6v1.1M43.6 160.8h.6l.2-.1v-.4l-.2-.2h-.6v1.1"/>
<path d="M43.6 164.4h.6l.2-.2v-.4l-.2-.2h-.6v1.2M43.6 166.2h.6l.2-.2v-.4l-.2-.2h-.6v1.1M43.6 169.7h.6l.2-.2v-.4l-.2-.1h-.6v1.1M43.6 171.5h.6l.2-.2v-.4l-.2-.2h-.6v1.2M43.6 173.2h.6l.2-.1v-.4l-.2-.2h-.6v1.1M43.6 175h.6l.2-.2v-.3l-.2-.2h-.6v1.1M43.6 176.8h.6l.2-.2v-.4l-.2-.2h-.6v1.2M43.6 178.6h.6l.2-.2v-.4l-.2-.2h-.6v1.1M44.8 165.8l.4-.4v1.1M44.8 161.2h.8M44.8 163h.8M44.8 164.8h.8"/>
<path d="M44.8 166.5h.8M44.8 168.3h.8M44.8 170.1h.8M44.8 171.9h.8M44.8 160.5l.4-.4v1.1M44.8 173.6h.8M44.8 162.2l.4-.3v1.1M44.8 175.4h.8M44.8 167.6l.4-.4v1.1M44.8 164l.4-.4v1.2M44.8 177.2h.8M44.8 178.9h.8"/>
<path d="M44.8 169.3l.4-.3v1.1M44.8 171.1l.4-.4v1.2M44.8 172.9l.4-.4v1.1M44.8 174.6l.4-.3v1.1M44.8 176.4l.4-.4v1.2M44.8 178.2l.4-.4v1.1M44.8 180l.4-.4v1.1M45.9 160.7h.8M45.9 162.4h.8M45.9 164.2h.8M45.9 166h.8M45.9 167.7h.8"/>
<path d="M45.9 169.5h.8M45.9 171.3h.8M45.9 173.1h.8M45.9 174.8h.8M45.9 176.6h.8M45.9 178.4h.8M47.1 179.6h.5l.2 .2-.2 .3 .2 .4-.2 .2h-.5zM47.1 161.9h.5l.2 .2-.2 .3 .2 .4-.2 .2h-.5zM47.1 163.6h.5l.2 .2-.2 .4 .2 .4-.2 .2h-.5zM47.1 160.1h.5l.2 .2-.2 .4 .2 .3-.2 .2h-.5zM47.1 160.7h.5M47.1 170.7h.5l.2 .2-.2 .4 .2 .4-.2 .2h-.5z"/>
<path d="M47.1 162.4h.5M47.1 164.2h.5M47.1 165.4h.5l.2 .2-.2 .4 .2 .3-.2 .2h-.5zM47.1 166h.5M47.1 167.2h.5l.2 .2-.2 .3 .2 .4-.2 .2h-.5zM47.1 167.7h.5M47.1 169h.5l.2 .1-.2 .4 .2 .4-.2 .2h-.5zM47.1 169.5h.5M47.1 171.3h.5M47.1 172.5h.5l.2 .2-.2 .4 .2 .3-.2 .2h-.5zM47.1 173.1h.5M47.1 174.3h.5l.2 .2-.2 .3 .2 .4-.2 .2h-.5z"/>
<path d="M47.1 174.8h.5M47.1 176h.5l.2 .2-.2 .4 .2 .4-.2 .2h-.5zM47.1 176.6h.5M47.1 177.8h.5l.2 .2-.2 .4 .2 .4-.2 .1h-.5zM47.1 178.4h.5M48.2 160.3l.2-.2h.4l.2 .2v.2l-.8 .7h.8M48.2 172.7l.2-.2h.4l.2 .2v.2l-.8 .7h.8M48.2 162.1l.2-.2h.4l.2 .2v.1l-.8 .8h.8M48.2 174.5l.2-.2h.4l.2 .2v.1l-.8 .8h.8M48.2 163.8l.2-.2h.4l.2 .2v.2l-.8 .8h.8M48.2 176.2l.2-.2h.4l.2 .2v.2l-.8 .8h.8M48.2 165.6l.2-.2h.4l.2 .2v.2l-.8 .7h.8"/>
<path d="M48.2 178l.2-.2h.4l.2 .2-.2 .4M48.2 167.4l.2-.2h.4l.2 .2v.2l-.8 .7h.8M48.2 179.8l.2-.2h.4l.2 .2-.2 .3M48.2 169.1l.2-.1h.4l.2 .1v.2l-.8 .8h.8M48.2 170.9l.2-.2h.4l.2 .2v.2l-.8 .8h.8M48.6 178.4h.2M48.8 178.4l.2 .2-.2 .3h-.4l-.2-.1M49.4 163h.7M49.4 163.8l.2-.2h.3l.2 .2v.2l-.7 .8h.7M49.4 165.6l.2-.2h.3l.2 .2-.2 .4M49.4 171.3h.5l.2 .4-.2 .2h-.3l-.2-.2zM49.4 172.5h.7v.2l-.7 .7v.2"/>
<path d="M49.4 162.2l.3-.3v1.1M49.4 180l.3-.4v1.1M49.6 174.8l-.2-.2 .2-.3h.3l.2 .2-.2 .3M49.6 174.8l-.2 .2 .2 .4h.3l.2-.2-.2-.4M49.6 174.8h.3M49.7 166h.2M49.9 166l.2 .2-.2 .3h-.3l-.2-.2M50.1 160.3l-.2-.2h-.3l-.2 .2v.7M50.1 160.3v.7l-.2 .2h-.3l-.2-.2M50.1 176.6h-.5l-.2-.2 .2-.4h.3l.2 .2v.8l-.2 .2h-.3l-.2-.2M50.1 178l-.2-.2h-.3l-.2 .2v.8M50.1 178v.8l-.2 .1h-.3l-.2-.1"/>
<path d="M50.1 167.7h-.7l.5-.5v1.1M50.1 169h-.7v.5l.3-.2 .4 .2v.4l-.2 .2h-.3l-.2-.2M50.1 160.3l-.7 .7M50.1 170.7l-.7 .6M50.1 178l-.7 .8M59.6 171.3v-1.1l.4 .4 .3-.4v1.1M59.6 176.6v-1.1l.4 .4 .3-.4v1.1M59.6 173.1v-1.1l.4 .3 .3-.3v1.1M59.6 174.9v-1.2l.4 .4 .3-.4v1.2M60.7 173.9l.2-.2h.4l.2 .2v.8l-.2 .2h-.4l-.2-.2zM60.7 172.1l.2-.1h.4l.2 .1v.8l-.2 .2h-.4l-.2-.2zM60.7 170.4l.2-.2h.4l.2 .2v.7l-.2 .2h-.4l-.2-.2z"/>
<path d="M60.9 175.5h.4l.2 .2v.7l-.2 .2h-.4l-.2-.2v-.7zM61.9 173.7h.5l.2 .2v.8l-.2 .2h-.5zM61.9 172h.5l.2 .1v.8l-.2 .2h-.5zM61.9 175.5h.5l.2 .2v.7l-.2 .2h-.5zM61.9 170.2h.5l.2 .2v.7l-.2 .2h-.5zM63 170.8h.8M63 174.3h.8M63 176.1h.8M63 172.5h.8M64.2 171.3v-.7l.3-.4 .4 .4v.7M64.2 170.8h.7M64.2 173.1v-.8l.3-.3 .4 .3v.8"/>
<path d="M64.2 174.9v-.8l.3-.4 .4 .4v.8M64.2 176.6v-.7l.3-.4 .4 .4v.7M64.2 174.3h.7M64.2 176.1h.7M64.2 172.5h.7M65.3 174.9h.8M65.3 172.1l.2-.1h.4l.2 .1v.2l-.8 .8h.8M65.3 174.1l.4-.4v1.2M65.3 170.4l.2-.2h.4l.2 .2-.2 .4M65.7 170.8h.2M65.9 170.8l.2 .1-.2 .4h-.4l-.2-.2M66.1 175.7v.7l-.2 .2h-.4l-.2-.2"/>
<path d="M66.1 175.7l-.2-.2h-.4l-.2 .2v.7M66.1 175.7l-.8 .7M114.6 163.9h.5l.2-.2v-.4l-.2-.2h-.5v1.1M114.6 165.6h.5l.2-.2v-.3l-.2-.2h-.5v1.1M114.6 167.4h.5l.2-.2v-.4l-.2-.2h-.5v1.2M114.6 169.2h.5l.2-.2v-.4l-.2-.2h-.5v1.1M115.3 161.3v1.2l-.7-1.2v1.2M115.7 161.5l.2-.2h.4l.2 .2v.8l-.2 .2h-.4l-.2-.2zM115.7 163.1v1.1l.4-.3 .4 .3v-1.1M115.7 164.9v1.1l.4-.4 .4 .4v-1.1M115.7 168.4v1.1l.4-.3 .4 .3v-1.1M115.7 166.6h.4"/>
<path d="M115.7 167.8h.4M115.9 166.6v1.2M116.5 167.2h.7M116.8 161.3h.6l.2 .2v.8l-.2 .2h-.6zM116.8 163.9h.6l.2-.2v-.4l-.2-.2h-.6v1.1M116.8 165.6h.6l.2-.2v-.3l-.2-.2h-.6v1.1M116.8 169.2h.6l.2-.2v-.4l-.2-.2h-.6v1.1M117.2 163.9l.4 .3M117.2 169.2l.4 .3M117.2 165.6l.4 .4M117.6 167.4h.6l.2-.2v-.4l-.2-.2h-.6v1.2M118 160.1h.4"/>
<path d="M118 163.7h.7M118 161.9h.4M118 169h.7M118 167.4l.4 .4M118 165.4h.7M118.7 161.3h-.7v1.2h.7M118.7 167.2h.4M119.1 166v-1.1l.4 .3 .4-.3v1.1M119.1 168.6l.2-.2h.4l.2 .2v.8l-.2 .1h-.4l-.2-.1zM119.1 160.1h.8M119.1 161.9h.8M119.5 166.6h-.8v1.2h.8"/>
<path d="M119.9 163.3l-.2-.2h-.4l-.2 .2 .2 .4h.4l.2 .2-.2 .3h-.4l-.2-.2M120.3 160.1h.7M120.3 163.7h.7M120.3 161.9h.7M120.3 160.7v-.8l.3-.3 .4 .3v.8M120.3 162.5v-.8l.3-.4 .4 .4v.8M120.3 163.1v1.1M120.3 165.4h.3M120.6 166.8l-.1-.2h-.4l-.2 .2 .2 .4h.4l.1 .2-.1 .4h-.4l-.2-.2M121 164.9h-.7v1.1h.7M121 168.4v1.1l-.7-1.1v1.1M121 163.1v1.1"/>
<path d="M121 167.2h.4M121.4 163.1v.9l.2 .2h.4l.2-.2v-.9M121.4 166v-.8l.4-.3 .4 .3v.8M121.4 161.5l.2-.2h.4l.2 .2-.2 .4M121.4 165.4h.8M121.8 166.6h-.8v1.2h.8M121.8 161.9h.2M122 161.9l.2 .2-.2 .4h-.4l-.2-.2M122.2 166.6h.7M122.6 166.6v1.2M122.6 163.1h.7M122.9 163.1v1.1"/>
<path d="M123.3 165.1l-.2-.2h-.4l-.1 .2 .1 .3h.4l.2 .2-.2 .4h-.4l-.1-.2M123.7 163.1h.5l.2 .2v.7l-.2 .2h-.5zM124.8 163.3l.2-.2h.4l.2 .2v.7l-.2 .2h-.4l-.2-.2zM126 163.1v1.1l.3-.3 .4 .3v-1.1M127.9 163.1v1.1l-.8-1.1v1.1M141 164l.2-.2 .4 .2v.1l-.6 .7h.6M141 165.7l.2-.1h.3l.1 .1v.2l-.6 .6h.6M141 167.5l.2-.2h.3l.1 .2-.6 .8h.6M141 169.3l.2-.2h.3l.1 .2-.6 .8h.6M141 162.3l.3-.3v1M141 161.2h.6M141 163h.6"/>
<path d="M141 160.6l.3-.3v.9M142 169.3l.1-.2h.4l.1 .2-.1 .3M142 166.5h.6M142 167.5l.1-.2h.4l.1 .2-.6 .8h.6M142 165.9l.3-.3v.9M142.1 160.7l-.1-.1 .1-.3h.4l.1 .1-.1 .3M142.1 160.7l-.1 .2 .1 .3 .5-.1-.1-.4M142.1 160.7h.4M142.3 169.6h.2M142.5 169.6l.1 .2-.1 .3h-.4l-.1-.2M142.6 162.5h-.5l-.1-.2 .1-.3h.4l.1 .2v.6l-.1 .2h-.4l-.1-.2M142.6 164v.6l-.1 .2h-.4l-.1-.2"/>
<path d="M142.6 164l-.1-.2-.5 .2v.6M142.6 164l-.6 .6M143.6 169.1l-.7 1M143.6 167.3l-.7 1M143.6 165.6l-.7 .9M143.6 163.8l-.7 1M143.6 162l-.7 1M143.6 160.3l-.7 .9M143.9 164.8v-.7l.4-.3 .3 .3v.7M143.9 161.2v-.6l.4-.3 .3 .3v.6M143.9 163v-.7l.4-.3 .3 .3v.7M143.9 166.5v-.6l.4-.3 .3 .3v.6"/>
<path d="M143.9 168.3v-.6l.4-.4 .3 .4v.6M143.9 170.1v-.7l.4-.3 .3 .3v.7M143.9 169.6h.7M143.9 167.8h.7M143.9 166.1h.7M143.9 164.3h.7M143.9 162.5h.7M143.9 160.7h.7M144.9 164.3h.5l.2 .3-.2 .2h-.3l-.2-.2zM144.9 165.6h.7l-.7 .9M145.1 167.8l-.2-.1 .2-.4h.3l.2 .2-.2 .3M145.1 167.8l-.2 .2 .2 .3 .5-.1-.2-.4"/>
<path d="M145.1 167.8h.3M145.6 169.6h-.5l-.2-.2 .2-.3h.3l.2 .2v.6l-.2 .2h-.3l-.2-.2M145.6 162h-.7v.5l.3-.2 .4 .2v.3l-.2 .2h-.3l-.2-.2M145.6 163.8l-.7 .5M145.6 160.7h-.7l.5-.4v.9M146.5 169.1l-.6 1M146.5 167.3l-.6 1M146.5 165.6l-.6 .9M146.5 163.8l-.6 1M146.5 162l-.6 1M146.5 160.3l-.6 .9M146.9 164.4h.5l.1-.4-.1-.2h-.5v1"/>
<path d="M146.9 166.2h.5l.1-.1-.1-.5h-.5v.9M146.9 169.1h.6M146.9 167.3h.6M146.9 162h.6M146.9 160.3h.6M147.2 160.3v.9M147.2 162v1M147.2 167.3v1M147.2 169.1v1M147.8 163.8v1l.4-.4 .3 .4v-1M147.8 165.6v.9l.4-.3 .3 .3v-.9M148.5 169.1l-.7 1"/>
<path d="M148.5 167.3l-.7 1M148.5 162l-.7 1M148.5 160.3l-.7 .9M148.8 164.8v-1l.3 .3 .4-.3v1M148.8 166.5v-.9l.3 .3 .4-.3v.9M148.8 168h.5l.2-.2v-.3l-.2-.2h-.5v1M148.8 169.8h.5l.2-.2v-.3l-.2-.2h-.5v1M149.5 160.4l-.2-.1h-.3l-.2 .3 .2 .1h.3l.2 .4-.2 .1-.5-.1M149.5 162.2l-.2-.2h-.3l-.2 .2 .2 .3h.3l.2 .2-.2 .3h-.3l-.2-.2M149.8 169.1v1l.3-.3 .4 .3v-1M149.8 160.3h.5l.2 .1v.7l-.2 .1h-.5zM149.8 167.3v1l.3-.3 .4 .3v-1"/>
<path d="M149.8 174.1h.5M150.1 174.1v.8M150.5 162.2l-.2-.2h-.3l-.2 .2v.6l.2 .2h.3l.2-.2M150.7 174.5h.2M150.8 162v1h.6M150.8 161.2v-.6l.3-.3 .3 .3v.6M150.8 168.3v-1l.3 .4 .3-.4v1M150.8 170.1v-1l.3 .3 .3-.3v1M150.8 160.7h.6M151.2 174.1h-.5v.8h.5M151.5 174.5h.2M152 174.1h-.5v.8h.5"/>
<path d="M152.4 160.4l-.1-.1h-.4l-.1 .1v.7M152.4 162.2l-.1-.2h-.4l-.1 .2v.6M152.4 160.4v.7l-.1 .1-.5-.1M152.4 162.2v.6l-.1 .2h-.4l-.1-.2M152.4 162.2l-.6 .6M152.4 160.4l-.6 .7M152.8 174.1v.8l-.5-.8v.8M153.6 174.2l-.1-.1-.4 .1 .1 .3 .4 .1-.1 .3-.4-.2M153.9 174.1l.3 .4M154.2 174.5v.4M154.4 174.1l-.2 .4M154.7 175h.5"/>
<path d="M155.6 174.2l.3-.1 .2 .1-.2 .3M155.8 174.5h.1M155.9 174.5l.2 .1-.2 .3-.3-.2M156.4 174.7l.1 .2zM156.8 174.9h.5M156.8 174.3l.2-.2v.8M157.6 174.5h.5M158.4 174.2l.4-.1 .1 .1-.1 .3M158.7 174.5h.1M158.8 174.5l.1 .1-.1 .3-.4-.2M159.2 174.7l.1 .2zM159.6 174.2l.2-.1 .3 .1-.5 .7h.5"/>
<path d="M160.4 175h.6M161.3 174.5h.5M161.3 174.9v-.6l.2-.2 .3 .2v.6M162.1 174.1v.8h.5M162.9 174.1v.8h.5M163.7 175h.5M164.5 174.6h.4l.1-.4-.5-.1v.8M165.4 174.1h.2M165.4 174.9h.2M165.5 174.1v.8M166.4 174.1v.8l-.5-.8v.8M167.2 174.2l-.1-.1-.4 .1 .1 .3 .4 .1-.1 .3-.4-.2"/>
<path d="M25 186.3l-.2-.2h-.4l-.1 .2v.8l.1 .2h.4l.2-.2v-.4h-.4M26.2 186.1v1.2l-.8-1.2v1.2M26.5 186.1h.6l.2 .2v.8l-.2 .2h-.6zM31.2 180.3h.6l.2-.2v-.3l-.2-.2h-.6v1.1M31.2 182.1h.6l.2-.2v-.4l-.2-.1h-.6v1.1M32.4 181.7l.4-.3v1.1M32.4 180.7h.7M32.4 182.5h.7M33.5 180.1h.8M33.5 181.9h.8M34.7 180.7v-.7l.4-.4 .3 .4v.7M34.7 182.5v-.8l.4-.3 .3 .3v.8"/>
<path d="M34.7 180.1h.7M34.7 181.9h.7M35.8 181.5l.2-.1h.4l.2 .1-.2 .4M36.2 180.1h.2M36.2 181.9h.2M36.4 180.1l.2 .2-.2 .4h-.4l-.2-.2M36.4 181.9l.2 .2-.2 .4h-.4l-.2-.2M37 181.5l.1-.1h.4l.2 .1v.2l-.7 .8h.7M37 180.7h.7M43.6 180.3h.6l.2-.2v-.3l-.2-.2h-.6v1.1M43.6 182.1h.6l.2-.2v-.4l-.2-.1h-.6v1.1M44.8 180.7h.8"/>
<path d="M44.8 182.5h.8M44.8 181.7l.4-.3v1.1M45.9 180.1h.8M45.9 181.9h.8M47.1 181.4h.5l.2 .1-.2 .4 .2 .4-.2 .2h-.5zM47.1 180.1h.5M47.1 181.9h.5M48.2 181.5l.2-.1h.4l.2 .1-.2 .4M48.6 180.1h.2M48.6 181.9h.2M48.8 180.1l.2 .2-.2 .4h-.4l-.2-.2M48.8 181.9l.2 .2-.2 .4h-.4l-.2-.2"/>
<path d="M49.4 180.7h.7M49.4 181.5l.2-.1h.3l.2 .1v.2l-.7 .8h.7M51.6 186.3l-.2-.2h-.4l-.2 .2v.8l.2 .2h.4l.2-.2v-.4h-.4M52.7 186.1v1.2l-.7-1.2v1.2M53.1 186.1h.6l.2 .2v.8l-.2 .2h-.6zM168.5 182.8l-.2-.2h-.4l-.2 .2v.7l.2 .2h.4l.2-.2v-.3h-.4M169.6 182.6v1.1l-.7-1.1v1.1M170 182.6h.6l.2 .2v.7l-.2 .2h-.6z"/>
</g>
<g fill="none" stroke="#800000" stroke-width=".2">
<path d="M7.3 17.2h265v176.3h-265zM23.1 15.6l.5-.6v1.7M23.1 16.7h1.1M40.4 14.5v2.7M56.2 15.3l.3-.3h.5l.3 .3v.3l-1.1 1.1h1.1M73.5 14.5v2.7M89.3 15.3l.3-.3h.5l.3 .3v.3l-.3 .2M89.9 15.8h.2M90.1 15.8l.3 .3v.3l-.3 .3h-.5l-.3-.3M106.6 14.5v2.7M123.5 15.8h-1.1l.9-.8v1.7M139.8 14.5v2.7"/>
<path d="M156.7 15h-1.1v.8l.5-.2h.3l.3 .2v.6l-.3 .3h-.6l-.2-.3M172.9 14.5v2.7M188.7 15.8h.8l.3 .3v.3l-.3 .3h-.5l-.3-.3zM189.8 15l-.6 .3-.5 .5M206 14.5v2.7M221.8 15h1.1v.3l-1.1 1.1v.3M239.1 14.5v2.7M255.2 15.8l-.3-.2v-.3l.3-.3h.6l.3 .3v.3l-.3 .2M255.2 15.8l-.3 .3v.3l.3 .3h.6l.3-.3v-.3l-.3-.3M255.2 15.8h.6M5.2 35.6v-1.1l.5-.5 .6 .5v1.1M5.2 34.8h1.1"/>
<path d="M30.6 34.9h1.2v3.5h-1.2zM31.2 29.6v1.7M31.2 33.1v1.8M31.2 38.4v1.8M31.2 29.6l.9 1.3M31.2 29.6l-.9 1.3M48.9 29.6v1.7M48.9 29.6l.9 1.3M48.9 29.6l-.9 1.3M51.8 38.4h1.3v3.6h-1.3zM52.5 36.7v1.7M58.9 38.4h1.3v3.6h-1.3z"/>
<path d="M59.5 36.7v1.7M116.3 38.4h1.7M119.8 38.1h3.6v.7h-3.6zM119.8 39.9h3.6v.7h-3.6zM124.1 38.4v.4l-.3-.3h.6M125.1 38.4h1.8M141.1 31.3l.9 1.4M141.1 31.3l-.9 1.4M141.1 31.3v1.8M148.2 36.7h1.7M149.9 36h3.6v1.3h-3.6zM153.5 36.7h1.8"/>
<path d="M157 36.7h5.3M158.8 35.8l1.8 .9-1.8 .8zM159.3 38.1l1 1M159.7 38.8l.4-.4 .2 .7zM159.7 38.8h.5M159.8 38.7h.4M159.8 38.9h.4M159.9 38.6h.2M159.9 38.5h.2M160 38.9h.3M160 38.5h.1M160.1 38l1 1"/>
<path d="M160.2 39h.1M160.5 38.7h.5M160.5 38.7l.6 .3M160.5 38.7l.3-.3 .3 .6M160.6 38.6h.4M160.6 35.8v1.7M160.7 38.8h.3M160.7 38.5h.2M160.8 38.4h.1M160.8 38.9h.3M161 38.9h.1M167.7 34.1v.7"/>
<path d="M168.3 34.1h-.2l-.4 .4M168.7 34.5h.7l-.2-.4h-.3l-.2 .2v.3l.2 .2h.3M170.6 33.7v1.1h-.6l-.2-.2v-.3l.2-.2h.6M172.1 34.8h.6l.2-.2v-.3l-.2-.2h-.6v1.1M173.4 34.1h.4l.2 .2v.3l-.2 .2h-.4l-.2-.2v-.3zM174.4 34.1v.5l.2 .2 .2-.2 .2 .2 .2-.2v-.5M175.5 34.5h.8l-.2-.4h-.4l-.2 .2v.3l.2 .2h.4M176.7 34.1v.7M177.2 34.1h-.1l-.4 .4M178.8 34.1h.2v.7M178.8 34.8h.4M179 33.5v.2"/>
<path d="M179.5 34.8v-.7h.6l.2 .2v.5M181.4 33.7v1.1h-.5l-.2-.2v-.3l.2-.2h.5M181.8 34.1h.2v.7M181.8 34.8h.4M182 33.5v.2M183.3 34.1h-.5l-.2 .2v.3l.2 .2h.5M183.9 34.1h.4l.2 .2v.5h-.6l-.2-.2 .2-.1h.6M184.9 34.1h.4M185.1 33.9v.7l.2 .2M185.8 34.1h.4l.2 .2v.3l-.2 .2h-.4l-.2-.2v-.3zM186.8 34.1v.7M187.3 34.1h-.1l-.4 .4"/>
<path d="M200 38.4h2.7M201.4 24.3v1.7M201.4 29.6v2.1M201.4 32.8v2.1M201.4 36.7v1.7M201.4 24.3l.8 1.3M201.4 24.3l-.9 1.3M212 38.4v1.8M217.3 26v1.8M217.3 26l.9 1.4M217.3 26l-.9 1.4M222.6 38.4h3.6"/>
<path d="M222.6 33.1h3.6M222.6 36.7h3.6M243.9 38.4h3.5M243.9 34.9h3.5M243.9 33.1h3.5M272.8 34.8h1.1M272.8 35.6v-1.1l.6-.5 .5 .5v1.1M4.6 52.5h2.7M17.4 52.6h2.7M18.8 40.2v1.8M18.8 43.8v2.1M18.8 46.9v2.2"/>
<path d="M18.8 50.8v1.8M18.8 40.2l.9 1.4M18.8 40.2l-.9 1.4M27.2 42h.4M27.2 43.8h.4M29.8 52.6h2.7M31.2 50.8v1.8M33 42h1.7M33 49.1h1.7M33 45.5h1.7M33 47.3h1.7M33 43.8h1.7"/>
<path d="M34.7 40.2h10.7v10.6h-10.7zM34.8 56.1h.4M34.8 55h.4M35 55v1.1M35.5 55h.6l.2 .2v.7l-.2 .2h-.6zM37.8 55.5h.4M38.6 55h-.8v1.1h.8M39 55.5h.3M39.7 55h-.7v1.1h.7M40.1 55.7h.6l.2-.2v-.3l-.2-.2h-.6v1.1M41.3 55.7h.5l.2-.2v-.3l-.2-.2h-.5v1.1M41.6 55.7l.4 .4"/>
<path d="M42.4 55.2l.2-.2h.4l.2 .2v.7l-.2 .2h-.4l-.2-.2zM43.5 56.1v-1.1l.4 .4 .4-.4v1.1M45.4 42h1.7M45.4 45.5h1.7M45.4 47.3h1.7M52.5 42v1.8M59.5 42v1.8M100.4 47.9v1.1h.7M101.5 48.5h.8M103.4 48.1l-.2-.2h-.4l-.1 .2v.7l.1 .2h.4l.2-.2M103.8 48.5h.8M103.8 49v-.7l.4-.4 .4 .4v.7"/>
<path d="M105.7 47.9v1.1l-.8-1.1v1.1M107.4 48.3h.4l.2 .2v.5h-.6l-.2-.2 .2-.2h.6M109.1 47.9v1.1h-.5l-.2-.2v-.3l.2-.2h.5M110.3 47.9v1.1h-.6l-.2-.2v-.3l.2-.2h.6M110.7 48.3v.7M111.2 48.3l-.5 .3M111.6 48.6h.8l-.2-.3h-.4l-.2 .2v.3l.2 .2h.4M113.5 48.3h-.6l-.1 .2 .7 .3-.2 .2h-.5M114.6 48.3h-.5l-.2 .2 .7 .3-.2 .2h-.5M116.2 48.3h.3M116.3 40.2h1.7M116.3 42h1.7"/>
<path d="M116.3 43.8h1.7M116.4 48.1v.7l.1 .2M116.9 48.5l.2-.2h.4l.2 .2v.5M116.9 47.9v1.1M118.1 48.3h.2v.7M118.1 49h.3M118.3 47.7v.2M118.8 43.9l.5-.1 .1 .4h-.5zM118.8 43.2h.6l-.6 .4h.6M119.6 48.3h-.6l-.2 .2 .8 .3-.2 .2h-.6M119.8 41.6h3.6v.7h-3.6zM119.8 43.4h3.6v.7h-3.6z"/>
<path d="M121.1 47.9v1.1h.6l.2-.2v-.3l-.2-.2h-.6M122.4 48.3h.4l.2 .2v.3l-.2 .2h-.4l-.1-.2v-.3zM123.6 48.3h.4l.2 .2v.5h-.6l-.2-.2 .2-.2h.6M124.1 40.1l-.1-.1-.2 .1 .1 .3M124.1 40.1l.1-.1 .2 .1-.1 .3M124.1 40.1v.1M124.4 41.8v.4l-.5-.4v.4M124.4 43.7h-.6l.2 .2M124.4 43.5v.4M124.5 48.3v.7M125.1 48.3h-.2l-.4 .3M125.1 40.2h1.8"/>
<path d="M125.1 42h1.8M125.1 43.8h1.8M126.3 47.9v1.1h-.6l-.2-.2v-.3l.2-.2h.6M129.1 49.1h2.7M130.5 47.3v1.8M148.2 50.8h1.7M148.2 43.8h1.7M149.9 43.1h3.6v1.3h-3.6zM149.9 50.2h3.6v1.3h-3.6zM153.5 50.8h1.8M153.5 43.8h1.8M157 50.8h5.3"/>
<path d="M157 43.8h5.3M158.8 50l1.8 .8-1.8 .9zM158.8 42.9l1.8 .9-1.8 .8zM159.3 52.3l1 .9M159.3 45.2l1 .9M159.7 53l.4-.4 .2 .6zM159.7 53h.5M159.7 45.9h.5M159.8 52.9h.4M159.8 45.8h.4M159.8 53h.4M159.8 45.9h.4"/>
<path d="M159.9 52.8h.2M159.9 45.7h.2M159.9 45.6h.2M160 52.7h.1M160 53.1h.3M160 46h.3M160 45.6h.1M160.1 45.5l-.4 .4 .6 .2M160.1 45.5l.2 .6M160.1 52.2l1 .9M160.1 45.1l1 1M160.2 53.2h.1"/>
<path d="M160.2 46.1h.1M160.5 52.9h.5M160.5 52.9l.6 .2M160.5 52.9l.3-.4 .3 .6M160.5 45.8h.5M160.5 45.8l.6 .3M160.5 45.8l.3-.4 .3 .7M160.6 52.8h.4M160.6 45.7h.4M160.6 42.9v1.7M160.6 50v1.7M160.7 53h.3"/>
<path d="M160.7 52.7h.2M160.7 45.9h.3M160.7 45.6h.2M160.8 52.6h.1M160.8 45.5h.1M160.8 53h.3M160.8 45.9h.3M161 53.1h.1M161 46h.1M164.6 54.4h2.6M165.9 52.6v1.8M167.9 48.3h.4l.2 .2v.5h-.6l-.2-.2 .2-.2h.6"/>
<path d="M168.5 41.9h-.6l-.2-.2v-.3l.2-.2h.6v.9l-.4 .2M168.9 41.2v.7M169.2 48.5l-.3-.2v.7M169.2 48.5v.5M169.2 48.5l.2-.2 .2 .2v.5M169.4 41.2h-.2l-.3 .4M169.8 41.6h.8l-.2-.4h-.4l-.2 .2v.3l.2 .2h.4M170 47.9v1.1h.6l.2-.2v-.3l-.2-.2h-.6M171 41.6h.7l-.2-.4h-.3l-.2 .2v.3l.2 .2h.3M171.2 48.6h.7l-.2-.3h-.4l-.1 .2v.3l.1 .2h.4M172.1 41.9v-.7h.6l.2 .2v.5M172.3 48.3v.7"/>
<path d="M172.9 48.3h-.2l-.4 .3M174.4 40.8v1.1h.8M174.4 48.3h.2v.7M174.4 49h.4M174.6 47.7v.2M175.5 41.4h.8M175.9 47.9v1.1h-.6l-.1-.2v-.3l.1-.2h.6M176.3 48.6h.8l-.2-.3h-.4l-.2 .2v.3l.2 .2h.4M177.4 41l-.2-.2h-.3l-.2 .2v.7l.2 .2h.3l.2-.2M177.4 49v-.7h.6l.2 .2v.5M177.8 41.4h.8M177.8 41.9v-.7l.4-.4 .4 .4v.7"/>
<path d="M178.6 48.3h.4M178.8 48.1v.7l.2 .2M179.3 48.3h.2v.7M179.3 49h.4M179.5 47.7v.2M179.7 40.8v1.1l-.7-1.1v1.1M180.1 48.5h.4M180.5 47.9l-.2 .2v.9M180.9 48.3v.5l.2 .2h.5M181.4 41.2h.4l.2 .2v.5h-.6l-.1-.2 .1-.1h.6M181.6 48.3v.9l-.3 .2M183.2 41.2h-.6l-.2 .2v.3l.2 .2h.6"/>
<path d="M183.5 41.2h.4M183.7 41v.7l.2 .2M184.3 41.2h.2v.7M184.3 41.9h.4M184.5 40.6v.2M185.1 41.2l.3 .7 .4-.7M186.2 41.2h.2v.7M186.2 41.9h.4M186.4 40.6v.2M187 41.2h.3M187.2 41v.7l.1 .2M187.7 41.2v.5l.2 .2h.6"/>
<path d="M188.5 41.2v.9l-.4 .2M201.4 56.2v1.7M201.4 56.2l.8 1.3M201.4 56.2l-.9 1.3M210.7 47.3h2.6M211.4 40.2h1.2v3.6h-1.2zM212 43.8v3.5M216 47.3h2.6M217.3 45.5v1.8M222.6 42h3.6M243.9 40.2h3.5M272.3 52.5h2.6"/>
<path d="M5.2 69.2h.8l.3 .3v.3l-.3 .3 .3 .3v.2l-.3 .3h-.8zM5.2 70.1h.8M31.2 68.6v1.7M31.2 68.6l.9 1.3M31.2 68.6l-.9 1.3M34.7 73.9h3.6M34.7 75.7h3.6M34.7 77.4h3.6M34.7 79.2h3.6M41.8 73.9h3.6M41.8 75.7h3.6M41.8 77.4h3.6"/>
<path d="M41.8 79.2h3.6M47.1 68.6v1.7M47.1 68.6l.9 1.3M47.1 68.6l-.9 1.3M96.8 66.8v1.8M96.8 66.8l.5 .9M96.8 66.8l-.6 .9M114.5 73.9h1.8M114.5 77.4h1.8M116.3 72.1h12.4v14.2h-12.4zM128.7 73.9h1.8M128.7 77.4h1.8"/>
<path d="M146.5 67.6l.1-.2h.4l.2 .2v.2l-.7 .7h.7M147.6 67.4v1.1l.4-.4 .4 .4v-1.1M149.9 67.8l.4-.4v1.1M149.9 68.5h.7M151 67.4h.2v.2h-.2zM151.8 68.3h.2v.2h-.2zM152 67.4l-1 1.1M154.3 67.8h-.6l-.2 .1 .8 .4-.2 .2h-.6M154.6 67.4v1.1M154.6 67.9l.2-.1h.4l.2 .1v.6M155.8 67.8v.5l.2 .2h.5v-.7M156.9 68.5v-.7h.6l.2 .1v.6"/>
<path d="M158.1 67.8h.4M158.3 67.6v.7l.2 .2M158.8 70.3h1.8M160.6 77.4h15.9v19.5h-15.9zM160.6 69.7h3.5v1.3h-3.5zM160.7 78.5v.8l.4 .4 .4-.4v-.8M161.8 78.9h.2v.8M161.8 79.7h.4M162 78.4v.1M162.6 79.7v-.8h.6l.2 .2v.6M163.7 79.1h.8M164.1 70.3h1.8"/>
<path d="M164.1 78.7v.8M165.9 73.9v8l-.5 .1 1 .4-1 .4 1 .3-1 .4 .5 .2v2.6M169.4 65v1.8M169.4 73.9v8l-.5 .1 1.1 .4-1.1 .4 1.1 .3-1.1 .4 .5 .2v2.6M169.4 65l.9 1.4M169.4 65l-.8 1.4M170.2 78.5v.8l.4 .4 .4-.4v-.8M171.3 78.9h.2v.8M171.3 79.7h.4M171.5 78.4v.1M172.1 79.7v-.8h.6l.2 .2v.6M173.2 79.1h.8"/>
<path d="M200 70.3h2.7M201.4 61.5v2.1M201.4 64.7v2.1M201.4 68.6v1.7M211.4 72.1h1.2v3.6h-1.2zM212 61.5l.9 1.3M212 61.5l-.9 1.3M212 61.5v1.7M212 70.3v1.8M212 75.7v1.7M217.3 73.9h3.6M217.3 75.7h3.6"/>
<path d="M217.3 79.2h3.6M217.3 66.8h3.6M217.3 70.3h3.6M217.3 72.1h3.6M249.2 73.9h3.6M249.2 75.7h3.6M249.2 79.2h3.6M249.2 66.8h3.6M249.2 70.3h3.6M249.2 68.6h3.6M272.8 69.2h.9l.2 .3v.3l-.2 .3 .2 .3v.2l-.2 .3h-.9zM272.8 70.1h.9"/>
<path d="M4.6 87.7h2.7M34.7 81h3.6M34.7 82.8h3.6M34.7 84.5h3.6M34.7 86.3h3.6M34.7 88.1h3.6M34.7 89.9h3.6M34.7 91.6h3.6M34.7 93.4h3.6M34.7 95.2h3.6M34.7 96.9h3.6M34.7 98.7h3.6"/>
<path d="M41.8 81h3.6M41.8 82.8h3.6M41.8 84.5h3.6M41.8 86.3h3.6M41.8 88.1h3.6M41.8 89.9h3.6M41.8 91.6h3.6M41.8 93.4h3.6M41.8 95.2h3.6M41.8 96.9h3.6M41.8 98.7h3.6M88.3 96.9h2.7"/>
<path d="M89.1 88.1h1.2v3.5h-1.2zM89.7 86.3v1.8M89.7 91.6v1.8M89.7 95.2v1.7M95.4 96.9h2.7M96.8 88.1v2.1M96.8 91.3v2.1M96.8 95.2v1.7M102.5 96.9h2.7M103.9 88.1v2.1M103.9 91.3v2.1M103.9 95.2v1.7"/>
<path d="M109.6 96.9h2.7M111 88.1v2.1M111 91.3v2.1M111 95.2v1.7M114.5 81h1.8M114.5 84.5h1.8M128.7 81h1.8M128.7 84.5h1.8M134.4 96.9h2.7M135.8 95.2v1.7M139.8 96.9h2.6M141.1 88.1v2.1"/>
<path d="M141.1 91.3v2.1M141.1 95.2v1.7M146.9 96.9h2.6M148.2 88.1v2.1M148.2 91.3v2.1M148.2 95.2v1.7M157 86.3h3.6M161.4 85.6v.8l.3 .4 .4-.4v-.8M162.5 86.2h.7M162.9 85.8v.8M163.8 82.6h1.2M164.2 82.1l.4 .5 .4-.5"/>
<path d="M165 83.4h-1.2l.4 .4M165 83v.8M165 86.3h5.3l-2.6 5.3zM165.5 87h.8M165.7 85.4h9.1v3.4l-.9 .9M165.7 85.4l.2-.2 .2 .2M165.7 85.4l.2 .2 .2-.2M165.7 85.5h.4M165.8 85.3h.3M165.8 85.6h.2M165.8 85.3h.2M165.9 86.7v.7"/>
<path d="M168.3 95.4l-.2-.2h-.4l-.1 .2v.8l.1 .2h.4l.2-.2v-.4h-.4M169.1 87h.7M169.4 96.9v3.6M169.5 95.2v1.2l-.8-1.2v1.2M169.8 95.2h.6l.2 .2v.8l-.2 .2h-.6zM170.4 82.6h1.1M170.8 82.1l.4 .5 .3-.5M171.5 83.4h-1.1l.4 .4M171.5 83v.8M172.7 93.8h.4l.2 .2v.7l-.2 .2h-.4l-.2-.2v-.7zM173.7 93.8v.9l.1 .2h.4l.2-.2v-.9M173.9 90.2h-2.7v3.2h-3.5v-1.8"/>
<path d="M173.9 90.7l.9 .9M173.9 89v2.4M174.4 91.4l.4 .2M174.6 91.3l.2 .3M174.8 91.6v1.8h5.3M174.8 93.8h.8M175.2 93.8v1.1M183 96.9h1.3v3.6h-1.3zM183.6 95.2v1.7M190.8 97.9l.4-.4v1.2M190.8 98.7h.7M191.9 97.5v.8l.4 .4 .4-.4v-.8"/>
<path d="M193.8 97.5l-.7 1.2M194.2 98.7v-.8l.4-.4 .4 .4v.8M194.2 98.1h.8M210.7 96.9h2.6M212 95.2v1.7M217.3 81h3.6M217.3 82.8h3.6M217.3 84.5h3.6M217.3 86.3h3.6M217.3 89.9h3.6M232.6 99.2v2.5M233 99.4h.5v2.1h-.5z"/>
<path d="M234 99.2v2.5M249.2 81h3.6M272.3 87.7h2.6M6.3 104.8l-.3-.3h-.6l-.2 .3v1.1l.2 .3h.6l.3-.3M24.5 116.4h2.7M25.3 109.3h1.2v3.6h-1.2zM25.9 107.6v1.7M25.9 112.9v3.5M29.5 116h.5l.2-.2v-.4l-.2-.1h-.5v1.1M29.8 116l.4 .4M30.8 115.6h.4l.2 .2v.6h-.6l-.2-.2 .2-.2h.6M31.6 111.1h2.7"/>
<path d="M32.5 115.6h-.6l-.2 .2 .8 .4-.2 .2h-.6M32.9 116.4h.6l.2-.2v-.4l-.2-.2h-.6v1.2M33 109.3v1.8M34 115.3v1.1h.6l.2-.2v-.4l-.2-.2h-.6M34.7 100.5h3.6M34.7 102.3h3.6M34.7 104h3.6M34.7 105.8h3.6M34.7 107.6h3.6M35.2 116h.7l-.1-.4h-.4l-.2 .2v.4l.2 .2h.4M36.3 115.6v.8M36.9 115.6h-.2l-.4 .4"/>
<path d="M37.3 115.6v.8M37.8 115.6h-.1l-.4 .4M38.2 115.6v.6l.2 .2h.6M39 115.6v1l-.4 .2M40.5 116h.6l.2-.2v-.4l-.2-.1h-.6v1.1M41.7 115.6h.1v.8M41.7 116.4h.3M41.8 100.5h3.6M41.8 102.3h3.6M41.8 104h3.6M41.8 105.8h3.6M41.8 107.6h3.6"/>
<path d="M41.8 115.1v.2M43.6 116h.5l.2-.2v-.4l-.2-.1h-.5v1.1M44.7 116.4h.7M44.7 115.6l.4-.3v1.1M45.8 111.1h2.7M47.1 109.3v1.8M47.7 115.6h-.5l-.2 .2v.4l.2 .2h.5M48.3 115.6h.4l.2 .2v.4l-.2 .2h-.4l-.2-.2v-.4zM49.3 116.4v-.8h.5l.2 .2v.6M50.4 116.4v-.8h.6l.2 .2v.6M51.6 116h.7l-.2-.4h-.4l-.1 .2v.4l.1 .2h.4M53.4 115.6h-.5l-.2 .2v.4l.2 .2h.5"/>
<path d="M53.8 115.6h.4M54 115.4v.8l.2 .2M54.8 115.6h.4l.2 .2v.4l-.2 .2h-.4l-.2-.2v-.4zM55.7 115.6v.8M56.3 115.6h-.2l-.4 .4M68.4 118.2l.5 .9M68.4 118.2l-.5 .9M68.4 118.2v1.8M125.2 103.6h.6l.1-.2v-.4l-.1-.2h-.6v1.2M125.6 103.6l.3 .4M126.5 103.2h.4l.2 .2v.6h-.6l-.2-.2 .2-.2h.6M128.2 103.2h-.5l-.2 .2 .7 .4-.2 .2h-.5"/>
<path d="M128.6 104h.6l.2-.2v-.4l-.2-.2h-.6v1.2M129.8 102.8v1.2h.5l.2-.2v-.4l-.2-.2h-.5M130.9 103.6h.8l-.2-.4h-.4l-.2 .2v.4l.2 .2h.4M132 103.2v.8M132.6 103.2h-.2l-.4 .4M133 103.2v.8M133.6 103.2h-.2l-.4 .4M133.9 103.2v.6l.2 .2h.6M134.7 103.2v1l-.4 .2M136.2 103.6h.6l.2-.2v-.4l-.2-.2h-.6v1.2M137.4 103.2h.2v.8M137.4 104h.4"/>
<path d="M137.6 102.6v.2M139.3 103.6h.5l.2-.2v-.4l-.2-.2h-.5v1.2M140.4 103.4l.2-.2h.4l.2 .2v.4l-.2 .2h-.4l-.2-.2zM141.6 103.2v.6l.2 .2 .1-.2 .2 .2 .2-.2v-.6M142.7 103.6h.8l-.2-.4h-.4l-.2 .2v.4l.2 .2h.4M143.8 103.2v.8M144.4 103.2h-.2l-.4 .4M146.7 103l-.2-.2h-.4l-.2 .2v.8l.2 .2h.4l.2-.2M147.1 103.4l.2-.2h.4l.1 .2v.4l-.1 .2h-.4l-.2-.2zM148.2 104v-.8h.6l.2 .2v.6M149.4 103.2h.4M149.6 103v.8l.2 .2"/>
<path d="M150.1 103.2v.8M150.7 103.2h-.2l-.4 .4M151.3 103.2h.4l.1 .2v.4l-.1 .2h-.4l-.2-.2v-.4zM152.2 102.8h.2v1.2M152.2 104h.4M168.1 105.8h2.7M169.4 104v1.8M182.3 105.8h2.7M183.6 100.5v1.8M183.6 104v1.8M219.9 113.7l-.2-.2h-.4l-.2 .2v.7l.2 .2h.4l.2-.2M220.3 114.6v-.7l.4-.4 .3 .4v.7"/>
<path d="M220.3 114h.7M221.3 109.3h2.7M222.2 113.5v1.1l-.8-1.1v1.1M222.6 100.5v2.1M222.6 103.7v2.1M222.6 107.6v1.7M223.7 114.6h.4M223.7 113.9h.2v.7M223.9 113.3v.2M224.5 114.6v-.7h.5l.2 .1v.6M225.6 113.9h.4M225.8 113.7v.7l.2 .2"/>
<path d="M226.4 114.2h.7l-.2-.3h-.3l-.2 .1v.4l.2 .2h.3M227.5 113.9v.7M228.1 113.9h-.2l-.4 .3M228.5 114h.4M228.9 113.5l-.2 .2v.9M229.4 113.9h.4l.2 .1v.6h-.6l-.2-.2 .2-.2h.6M230.6 100.5h2M231.1 113.9h-.5l-.2 .1v.4l.2 .2h.5M231.5 114.2h.8l-.2-.3h-.4l-.2 .1v.4l.2 .2h.4M233.8 114h.4M234 100.5h1.9M234.2 113.5l-.2 .2v.9"/>
<path d="M234.6 114l.2-.1h.3l.2 .1v.4l-.2 .2h-.3l-.2-.2zM235.7 113.9v.7M236.3 113.9h-.2l-.4 .3M237.8 114.2h.6l.1-.2v-.3l-.1-.2h-.6v1.1M238.2 114.2l.3 .4M239.1 113.9h.4l.2 .1v.6h-.6l-.2-.2 .2-.2h.6M240.8 109.3h2.7M240.8 113.9h-.5l-.2 .1 .7 .4-.2 .2h-.5M241.2 114.6h.6l.2-.2v-.4l-.2-.1h-.6v1.1M242.1 100.5v2.1M242.1 103.7v2.1M242.1 107.6v1.7"/>
<path d="M242.4 113.5v1.1h.5l.2-.2v-.4l-.2-.1h-.5M243.5 114.2h.8l-.2-.3h-.4l-.2 .1v.4l.2 .2h.4M244.6 113.9v.7M245.2 113.9h-.2l-.4 .3M245.6 113.9v.7M246.2 113.9h-.2l-.4 .3M246.5 113.9v.5l.2 .2h.6M247.3 113.9v.9l-.4 .2M248.8 114.2h.6l.2-.2v-.3l-.2-.2h-.6v1.1M250 113.9h.2v.7M250 114.6h.4M250.2 113.3v.2"/>
<path d="M273.9 104.8l-.2-.3h-.6l-.3 .3v1.1l.3 .3h.6l.2-.3M4.6 123h2.7M5.2 139.8h.8l.3 .3v1.1l-.3 .3h-.8zM27.6 127.1h1.8M27.6 128.8h1.8M27.6 130.6h1.8M27.6 132.4h1.8M27.6 134.2h1.8M27.6 135.9h1.8M27.6 137.7h1.8M27.6 139.5h1.8M40 127.1h1.8"/>
<path d="M40 128.8h1.8M40 130.6h1.8M40 132.4h1.8M40 134.2h1.8M40 135.9h1.8M40 137.7h1.8M40 139.5h1.8M56 123.5h1.8M57.8 122.6h5.3v1.8h-5.3zM63.1 121.8h-.9l-3.7 3.5M63.1 123.5h1.8M63.1 126.4h.8"/>
<path d="M63.5 126.1v.7M65 125.9h-.7v.5l.6-.1 .1 .1v.4l-.1 .2h-.4l-.2-.2M65.4 125.9v.7l.4 .4 .4-.4v-.7M67.7 126.3v.7M68.3 126.3h-.2l-.4 .3M68.7 126.6h.7l-.2-.3h-.3l-.2 .1v.4l.2 .2h.3M70.6 127h-.6l-.2-.2v-.4l.2-.1h.6v.9l-.4 .2M71 126.3v.5l.1 .2h.6v-.7M72.1 125.9h.2v1.1M72.1 127h.4M73 126.3h.4l.2 .1v.6h-.6l-.1-.2 .1-.2h.6M74 126.3h.4"/>
<path d="M74.2 126.1v.7l.2 .2M74.8 126.6h.7l-.2-.3h-.3l-.2 .1v.4l.2 .2h.3M76.7 125.9v1.1h-.6l-.2-.2v-.4l.2-.1h.6M78.2 126.4h.4M78.6 125.9l-.2 .2v.9M79 126.3v.7M79.5 126.3h-.2l-.3 .3M79.9 126.4l.2-.1h.4l.2 .1v.4l-.2 .2h-.4l-.2-.2zM81.4 126.4l.2-.1 .2 .1v.6M81.4 126.4l-.4-.1v.7M81.4 126.4v.6M83.3 125.9v1.1h.6l.2-.2v-.4l-.2-.1h-.6"/>
<path d="M84.5 126.3v.5l.2 .2h.5v-.7M86.4 126.3h-.6l-.2 .1 .2 .2h.4l.2 .2-.2 .2h-.6M135.8 128.8h3.5M135.8 130.6h3.5M135.8 132.4h3.5M135.8 134.2h3.5M135.8 135.9h3.5M135.8 137.7h3.5M135.8 139.5h3.5M139.3 125.3h24.8v47.8h-24.8zM164.1 127.1h3.6M164.1 128.8h3.6"/>
<path d="M164.1 130.6h3.6M164.1 132.4h3.6M164.1 134.2h3.6M164.1 137.7h3.6M174.8 121.8l.5 .8M174.8 121.8l-.6 .8M174.8 121.8v1.7M210.2 132.4v1.8M210.2 132.4l.6 .9M210.2 132.4l-.5 .9M222.6 137.7h3.6M243.9 137.7h3.5"/>
<path d="M243.9 139.5h3.5M272.3 123h2.6M272.8 139.8h.9l.2 .3v1.1l-.2 .3h-.9zM4.6 158.3h2.7M27.6 141.2h1.8M27.6 143h1.8M27.6 144.8h1.8M27.6 146.6h1.8M27.6 148.3h1.8M27.6 150.1h1.8M27.6 151.9h1.8M27.6 153.6h1.8"/>
<path d="M27.6 155.4h1.8M27.6 157.2h1.8M27.6 159h1.8M40 141.2h1.8M40 143h1.8M40 144.8h1.8M40 146.6h1.8M40 148.3h1.8M40 150.1h1.8M40 151.9h1.8M40 153.6h1.8M40 155.4h1.8"/>
<path d="M40 157.2h1.8M40 159h1.8M135.8 141.2h3.5M135.8 143h3.5M135.8 144.8h3.5M135.8 146.6h3.5M135.8 148.3h3.5M135.8 150.1h3.5M135.8 151.9h3.5M135.8 153.6h3.5M135.8 155.4h3.5M135.8 157.2h3.5"/>
<path d="M135.8 159h3.5M164.1 141.2h3.6M164.1 143h3.6M164.1 146.6h3.6M164.1 151.9h3.6M164.1 153.6h3.6M201.8 151.9h2.6M202.5 144.8h1.3v3.5h-1.3zM203.1 143v1.8M203.1 148.3v3.6M208.9 151.9h2.6M210.2 143v2.1"/>
<path d="M210.2 146.2v2.1M210.2 150.1v1.8M216 151.9h2.6M217.3 150.1v1.8M222.6 141.2h3.6M222.6 143h3.6M222.6 146.6h3.6M225.2 159.7l-.2-.1h-.4l-.1 .1v.8l.1 .2h.4l.2-.2M227.5 159.6v1.1l-.8-1.1v1.1M229 159.9h.4M229.2 159.7v.8l.2 .2M229.8 159.9v.8"/>
<path d="M230.4 159.9h-.2l-.4 .4M230.9 159.9h.4l.2 .2v.6h-.6l-.2-.2 .2-.2h.6M233.8 159.9h-.6l-.2 .2 .8 .4-.2 .2h-.6M234.9 159.9h-.5l-.2 .2v.4l.2 .2h.5M236.5 159.9h.1v.8M236.6 159.4v.2M237.2 159.9l.4 .8 .4-.8M239.5 159.9v.8M240.1 159.9h-.2l-.4 .4M242 159.6l-.2 .1v1M243.5 159.9v.8M243.9 143h3.5"/>
<path d="M243.9 144.8h3.5M244.1 159.9h-.2l-.4 .4M245.6 159.6h.7M246 159.6v1.1M247.5 159.6h-.8v1.1h.8M248.6 159.6h-.7v1.1h.7M249.8 159.6v1.1l-.8-1.1v1.1M250.9 159.7l-.2-.1h-.3l-.2 .1 .2 .4h.3l.2 .2-.2 .4h-.3l-.2-.2M251.3 159.6v.1l.4 .4M252.1 159.6v.1l-.4 .4M272.3 158.3h2.6M5.2 175.9h.5"/>
<path d="M6.3 175h-1.1v1.7h1.1M27.6 176.7h1.8M27.6 160.7h1.8M27.6 162.5h1.8M27.6 164.3h1.8M27.6 166.1h1.8M27.6 167.8h1.8M27.6 169.6h1.8M27.6 171.4h1.8M27.6 173.1h1.8M27.6 174.9h1.8M27.6 178.5h1.8"/>
<path d="M40 176.7h1.8M40 160.7h1.8M40 162.5h1.8M40 164.3h1.8M40 166.1h1.8M40 167.8h1.8M40 169.6h1.8M40 171.4h1.8M40 173.1h1.8M40 174.9h1.8M40 178.5h1.8M57.8 179l.8 1.2"/>
<path d="M58.6 179l-.8 1.2M59 179.6h.7M60.9 179.2l-.2-.2h-.4l-.2 .2v.8l.2 .2h.4l.2-.2M61.3 179.6h.7M63.2 179v1.2l-.8-1.2v1.2M64.9 179.4h.4l.1 .2v.6h-.5l-.2-.2 .2-.2h.5M66.6 179v1.2h-.6l-.2-.2v-.4l.2-.2h.6M67.7 179v1.2h-.5l-.2-.2v-.4l.2-.2h.5M68.1 179.4v.8M68.7 179.4h-.2l-.4 .4M69.1 179.8h.7l-.2-.4h-.3l-.2 .2v.4l.2 .2h.3M71 179.4h-.6l-.2 .2 .2 .2h.4l.2 .2-.2 .2h-.6"/>
<path d="M72.1 179.4h-.6l-.1 .2 .7 .4-.2 .2h-.5M73.6 179.6h.4M74 179l-.2 .2v1M74.4 179.4v.8M75 179.4h-.2l-.4 .4M75.4 179.6l.1-.2h.4l.2 .2v.4l-.2 .2h-.4l-.1-.2zM76.9 179.6l-.4-.2v.8M76.9 179.6v.6M76.9 179.6l.1-.2 .2 .2v.6M79.1 179.6l-.3-.2v.8M79.1 179.6v.6M79.1 179.6l.2-.2 .2 .2v.6"/>
<path d="M80.1 179.4h.4l.2 .2v.4l-.2 .2h-.4l-.2-.2v-.4zM81.8 179v1.2h-.6l-.2-.2v-.4l.2-.2h.6M82.2 179.4v.6l.2 .2h.6v-.8M83.3 179h.2v1.2M84.1 179.8h.8l-.2-.4h-.4l-.2 .2v.4l.2 .2h.4M87.1 179.4h-.5l-.2 .2v.4l.2 .2h.5M87.5 179.6l.2-.2h.4l.2 .2v.4l-.2 .2h-.4l-.2-.2zM89.8 179.4h.4M90 179.2v.8l.2 .2M90.6 179.4v.8M91.1 179.4h-.1l-.4 .4M91.5 179.6l.2-.2h.4l.2 .2v.4l-.2 .2h-.4l-.2-.2z"/>
<path d="M92.7 179h.2v1.2M93.4 179h.2v1.2M94.2 179.8h.8l-.2-.4h-.4l-.2 .2v.4l.2 .2h.4M95.3 179.4v.8M95.9 179.4h-.2l-.4 .4M123.4 177.3h.8M123.8 177.3v1.1M124.6 177.8h.3M125.3 177.3h-.7v1.1h.7M125.7 177.8h.4M126.4 177.3h-.7v1.1h.7M127.6 177.3v1.1l-.8-1.1v1.1"/>
<path d="M128.7 177.5l-.2-.2h-.3l-.2 .4 .2 .1h.3l.2 .4-.2 .2h-.3l-.2-.2M129.1 177.3v.2l.4 .3M129.5 177.8v.6M129.9 177.3v.2l-.4 .3M131.4 177.5l.2-.2h.4l.2 .2-.2 .3M131.8 177.8h.2M132 177.8l.2 .2-.2 .4h-.4l-.2-.2M132.5 178.2h.2v.2h-.2zM133.1 177.5l.2-.2h.4l.2 .2v.2l-.8 .7h.8M135.4 177.8h.8M135.8 160.7h3.5M135.8 162.5h3.5"/>
<path d="M135.8 164.3h3.5M135.8 166.1h3.5M135.8 167.8h3.5M135.8 169.6h3.5M138.1 177.8l-.4-.1v.7M138.1 177.8v.6M138.1 177.8l.2-.1 .2 .1v.6M139 177.7h.4l.2 .1v.6h-.6l-.2-.2 .2-.2h.6M140 178.4v-.7h.5l.2 .1v.6M141.3 177.7h.4l.2 .1v.6h-.6l-.2-.2 .2-.2h.6M143 178.4h-.5l-.2-.2v-.4l.2-.1h.5v.9l-.4 .2M143.4 178h.8l-.2-.3h-.4l-.2 .1v.4l.2 .2h.4"/>
<path d="M144.9 177.8l-.4-.1v.7M144.9 177.8v.6M144.9 177.8l.2-.1 .2 .1v.6M145.7 178h.8l-.2-.3h-.4l-.2 .1v.4l.2 .2h.4M146.8 178.4v-.7h.6l.2 .1v.6M148 177.7h.4M148.2 177.5v.7l.2 .2M150.3 177.8l-.4-.1v.7M150.3 177.8v.6M150.3 177.8l.2-.1 .1 .1v.6M151 178.4h.4M151 177.7h.2v.7"/>
<path d="M151.2 177.1v.2M152.5 177.7h-.5l-.2 .1v.4l.2 .2h.5M152.9 177.7v.7M153.5 177.7h-.2l-.4 .3M153.9 177.8l.2-.1h.4l.1 .1v.4l-.1 .2h-.4l-.2-.2zM155.8 177.7h-.6l-.2 .1v.4l.2 .2h.6M156.2 177.8l.2-.1h.3l.2 .1v.4l-.2 .2h-.3l-.2-.2zM157.3 178.4v-.7h.6l.2 .1v.6M158.5 177.7h.3M158.6 177.5v.7l.2 .2M159.2 177.7v.7M159.8 177.7h-.2l-.4 .3"/>
<path d="M160.2 177.8l.2-.1h.3l.2 .1v.4l-.2 .2h-.3l-.2-.2zM161.3 177.3h.2v1.1M161.3 178.4h.4M162.1 177.3h.2v1.1M162.1 178.4h.4M162.8 178h.8l-.2-.3h-.4l-.2 .1v.4l.2 .2h.4M164 177.7v.7M164.5 177.7h-.1l-.4 .3M225.6 160.7v-.8l.4-.3 .4 .3v.8M225.6 160.1h.8M231.9 160.7v-.8h.6l.1 .2v.6M235.3 160.3h.8l-.2-.4h-.4l-.2 .2v.4l.2 .2h.4"/>
<path d="M236.5 160.7h.3M238.4 160.3h.7l-.2-.4h-.4l-.1 .2v.4l.1 .2h.4M241.6 160.1h.4M242.4 160.1l.1-.2h.4l.2 .2v.4l-.2 .2h-.4l-.1-.2zM243.5 179.3v14.2M246.7 160.1h.4M247.9 160.1h.4M251.7 160.1v.6M272.3 179.3h-66.5v14.2M272.8 175.9h.6M273.9 175h-1.1v1.7h1.1M23.1 194.6l.5-.6v1.7"/>
<path d="M23.1 195.7h1.1M24.5 185.6h2.7M25.9 183.8v1.8M27.6 180.2h1.8M27.6 182h1.8M27.7 187.9h.6l.1 .2v.8l-.1 .2h-.6zM28.8 189.1h.4M28.8 187.9h.4M29 187.9v1.2M30.4 187.9v1.2l-.8-1.2v1.2M32.6 188.5h-.7l.5-.6v1.2M33 189.1h.8"/>
<path d="M33 188.3l.4-.4v1.2M34.2 188.5h.5l.2 .4-.2 .2h-.3l-.2-.2zM34.9 187.9l-.7 .6M35.3 189.1h.8M35.3 188.3l.4-.4v1.2M36.4 188.1l.2-.2h.4l.2 .2v.2l-.8 .8h.8M38.7 187.9v1.2h.6l.2-.2v-.4l-.2-.2h-.6M40 180.2h1.8M40 182h1.8M40.1 188.3h.3l.2 .2v.6h-.5l-.2-.2 .2-.2h.5M40.4 193.5v2.7M41.8 188.3h-.6l-.2 .2v.4l.2 .2h.6"/>
<path d="M42.2 187.9v1.2M42.7 188.3l-.5 .4 .5 .4M43.1 189.1h.6l.2-.2v-.4l-.2-.2h-.6v1.1M44.3 189.1h.3M44.3 187.9h.1v1.2M45.2 188.3h.4l.2 .2v.6h-.6l-.2-.2 .2-.2h.6M46.2 189.1v-.8h.5l.2 .2v.6M47.3 188.7h.8l-.2-.4h-.4l-.2 .2v.4l.2 .2h.4M51.1 185.6h2.7M52.5 183.8v1.8M56.2 194.3l.3-.3h.5l.3 .3v.3l-1.1 1.1h1.1M58.2 180.8l-.4 .4v.4l.4 .4"/>
<path d="M58.6 181.4l.2-.2h.4l.2 .2v.4l-.2 .2h-.4l-.2-.2zM59.7 182h.6l.2-.2v-.4l-.2-.2h-.6v1.1M60.9 181.6h.7l-.2-.4h-.3l-.2 .2v.4l.2 .2h.3M61.3 180.2v-.8l.3-.4 .4 .4v.8M62 182v-.8h.6l.2 .2v.6M65.1 181.2h-.6l-.2 .2v.4l.2 .2h.6M65.6 181.2h.4l.2 .2v.4l-.2 .2h-.4l-.2-.2v-.4zM66.6 182h.4M66.6 180.8h.2v1.2M67.4 182h.3M67.4 180.8h.1v1.2M68.1 181.6h.8l-.2-.4h-.4l-.2 .2v.4l.2 .2h.4"/>
<path d="M70 181.2h-.6l-.1 .2v.4l.1 .2h.6M70.4 181.2h.4M70.6 181v.8l.2 .2M71.2 181.4l.2-.2h.3l.2 .2v.4l-.2 .2h-.3l-.2-.2zM72.3 181.2v.8M72.9 181.2l-.6 .4M73.3 180.8l.3 .4v.4l-.3 .4M73.5 193.5v2.7M83.3 180.2h.4M88.7 180.2v-.8h.5l.2 .2v.6M89.3 194.3l.3-.3h.5l.3 .3v.3l-.3 .3M89.9 194.9h.2"/>
<path d="M90.1 194.9l.3 .2v.3l-.3 .3h-.5l-.3-.3M92.7 180.2h.3M93.4 180.2h.4M106.6 193.5v2.7M123.5 194.9h-1.1l.9-.9v1.7M139.8 193.5v2.7M156.7 194h-1.1v.9l.5-.3h.3l.3 .3v.5l-.3 .3h-.6l-.2-.3M168.1 182h2.7M169.4 180.2v1.8M172.9 193.5v2.7M188.7 194.9h.8l.3 .2v.3l-.3 .3h-.5l-.3-.3zM189.8 194l-.6 .3-.5 .6"/>
<path d="M206 193.5v2.7M206.7 183.2h.9l.2-.3v-.5l-.2-.3h-.9v1.6M207.3 183.2l.5 .5M207.8 185.9l-.2-.3h-.6l-.3 .3v1.1l.3 .3h.6l.2-.3M208.4 186.4l.2-.2h.6l.3 .2v.6l-.3 .3h-.6l-.2-.3zM208.6 182.6h.6l.3 .3v.8h-.9l-.2-.2 .2-.3h.9M210.5 186.4l-.2-.2h-.3v1.1M210.5 186.4v.9M210.5 186.4l.3-.2 .3 .2v.9M211.1 182.6h-.8l-.3 .3 .3 .3h.5l.3 .3-.3 .2h-.8M211.6 183.7h.8l.3-.2v-.6l-.3-.3h-.8v1.7M211.6 187.3h.8l.3-.3v-.6l-.3-.2h-.8v1.6"/>
<path d="M213.3 182.1v1.6h.8l.3-.2v-.6l-.3-.3h-.8M213.3 186.2v.8l.3 .3h.8v-1.1M214.9 183.2h1.1v-.3l-.3-.3h-.5l-.3 .3v.6l.3 .2h.5M214.9 186.2h.6M215.2 185.9v1.1l.3 .3M216 186.7h1.1v-.3l-.3-.2h-.5l-.3 .2v.6l.3 .3h.5M216.5 182.6v1.1M217.4 182.6h-.3l-.6 .6M217.9 182.6v1.1M218.7 182.6h-.3l-.5 .6M219.3 182.6v.9l.2 .2h.8M219.3 185.6h.8l.2 .3v.3l-.2 .2 .2 .3v.3l-.2 .3h-.8z"/>
<path d="M219.3 186.4h.8M220.3 182.6v1.4l-.2 .3h-.3M220.9 186.4l.3-.2h.5l.3 .2v.6l-.3 .3h-.5l-.3-.3zM221.8 194h1.1v.3l-1.1 1.1v.3M222.5 183.2h.8l.3-.3v-.5l-.3-.3h-.8v1.6M222.8 186.2h.5l.3 .2v.9h-.8l-.3-.3 .3-.3h.8M224.2 182.6h.2v1.1M224.2 183.7h.5M224.2 186.2v1.1M224.4 181.8v.3M225 186.2h-.3l-.5 .5M226.6 185.6v1.7h-.8l-.3-.3v-.6l.3-.2h.8"/>
<path d="M228.8 185.6v1.1l.5 .6 .6-.6v-1.1M230.4 187.3h1.1M230.4 186.2l.5-.6v1.7M239.1 193.5v2.7M243.5 186.4h28.8M243.5 190h28.8M243.5 182.9h28.8M244.9 189h.9M244.9 185h1v-.3l-.2-.3h-.6l-.2 .3v.5l.2 .3h.6M244.9 188.1l.4-.5v1.4M245.8 191.3l-.3-.3h-.6l-.2 .3v.3l.2 .3h.6l.3 .2v.3l-.3 .3h-.6l-.2-.3M246.3 191v1.7"/>
<path d="M246.3 191.9l.3-.3h.5l.3 .3v.8M246.5 184.4v.8l.3 .3h.8v-1.1M247.3 187.6l-1 1.4M247.9 192.1h1.1v-.2l-.2-.3h-.6l-.3 .3v.5l.3 .3h.6M248 188.3l-.2 .3v.2l.2 .2h.5l.3-.2v-.2l-.3-.3M248 188.3h.5M248 188.3l-.2-.2v-.3l.2-.2h.5l.3 .2v.3l-.3 .2M248.1 184.4v1.1M248.9 184.4h-.2l-.6 .6M249.6 192.1h1.1v-.2l-.3-.3h-.5l-.3 .3v.5l.3 .3h.5M249.7 184.4h.6l.3 .3v.5l-.3 .3h-.6l-.2-.3v-.5zM250.2 187.6l-.9 1.4"/>
<path d="M250.7 189h1M250.7 188.1l.5-.5v1.4M251.2 191.6h.6M251.5 191.3v1.1l.3 .3M252.2 184.4h-.8l-.3 .3v.5l.3 .3h.8M252.2 187.6h1v.2l-1 1v.2M252.3 191.6h.3v.3h-.3zM252.3 192.4h.3v.3h-.3zM253 184.4h.6l.2 .3v.8h-.8l-.2-.3 .2-.2h.8M254.2 191.5l.5-.6v1.7M254.2 192.6h1M254.4 184.4v1.1"/>
<path d="M255.1 189h1M255.1 188.1l.5-.5v1.4M255.2 184.4h-.3l-.5 .6M255.2 194.9l-.3 .2v.3l.3 .3h.6l.3-.3v-.3l-.3-.2M255.2 194.9l-.3-.3v-.3l.3-.3h.6l.3 .3v.3l-.3 .3M255.2 194.9h.6M256.6 187.8l.2-.2h.5l.3 .2v.3l-1 .9h1M256.8 183.9v1.6h-.8l-.3-.3v-.5l.3-.3h.8M256.9 190.9l-1.1 1.7M257.4 192.6h1.1M257.4 191.5l.6-.6v1.7M258.1 188.8h.2v.2h-.2z"/>
<path d="M258.1 188.1h.2v.2h-.2zM259.8 188.3h-1l.7-.7v1.4M261.3 188.3h-1l.7-.7v1.4M263.2 188.6h.7l.3-.3v-.5l-.3-.2h-.7v1.4M264.7 189v-1.4l.5 .5 .5-.5v1.4M265.2 190v3.5"/>
<circle cx="26.6" cy="43.8" r=".7"/>
<circle cx="26.6" cy="42" r=".7"/>
</g>
<path d="M118 37.1h7.1v8h-7.1zM226.2 29.6h17.7v15.9h-17.7zM37.4 72.1h5.3v37.2h-5.3zM220.9 63.2h28.3v30.2h-28.3zM226.2 134.2h17.7v15.9h-17.7z" fill="none" stroke="#800000" stroke-width=".3"/>
<g fill="none" stroke="#800000" stroke-width=".44">
<path d="M38.3 77.4h.9M38.3 75.7h.9M38.3 73.9h.9M38.3 79.2h.9M40.9 77.4h.9M40.9 75.7h.9M40.9 73.9h.9M40.9 79.2h.9M38.3 81h.9M38.3 86.3h.9M38.3 84.5h.9M38.3 82.8h.9"/>
<path d="M38.3 89.9h.9M38.3 88.1h.9M38.3 95.2h.9M38.3 93.4h.9M38.3 91.6h.9M38.3 98.7h.9M38.3 96.9h.9M40.9 81h.9M40.9 86.3h.9M40.9 84.5h.9M40.9 82.8h.9M40.9 89.9h.9"/>
<path d="M40.9 88.1h.9M40.9 95.2h.9M40.9 93.4h.9M40.9 91.6h.9M40.9 98.7h.9M40.9 96.9h.9M38.3 102.3h.9M38.3 100.5h.9M38.3 104h.9M38.3 105.8h.9M38.3 107.6h.9M40.9 102.3h.9"/>
<path d="M40.9 100.5h.9M40.9 104h.9M40.9 105.8h.9M40.9 107.6h.9M29.4 127.1h.9M29.4 128.8h.9M29.4 130.6h.9M29.4 132.4h.9M29.4 134.2h.9M29.4 135.9h.9M29.4 137.7h.9M29.4 139.5h.9"/>
<path d="M41.8 127.1h.9M41.8 128.8h.9M41.8 130.6h.9M41.8 132.4h.9M41.8 134.2h.9M41.8 135.9h.9M41.8 137.7h.9M41.8 139.5h.9M29.4 141.2h.9M29.4 143h.9M29.4 144.8h.9M29.4 146.6h.9"/>
<path d="M29.4 148.3h.9M29.4 150.1h.9M29.4 151.9h.9M29.4 153.6h.9M29.4 155.4h.9M29.4 157.2h.9M29.4 159h.9M41.8 141.2h.9M41.8 143h.9M41.8 144.8h.9M41.8 146.6h.9M41.8 148.3h.9"/>
<path d="M41.8 150.1h.9M41.8 151.9h.9M41.8 153.6h.9M41.8 155.4h.9M41.8 157.2h.9M41.8 159h.9M29.4 160.7h.9M29.4 162.5h.9M29.4 164.3h.9M29.4 166.1h.9M29.4 167.8h.9M29.4 169.6h.9"/>
<path d="M29.4 171.4h.9M29.4 173.1h.9M29.4 174.9h.9M29.4 176.7h.9M29.4 178.5h.9M41.8 160.7h.9M41.8 162.5h.9M41.8 164.3h.9M41.8 166.1h.9M41.8 167.8h.9M41.8 169.6h.9M41.8 171.4h.9"/>
<path d="M41.8 173.1h.9M41.8 174.9h.9M41.8 176.7h.9M41.8 178.5h.9M29.4 180.2h.9M29.4 182h.9M41.8 180.2h.9M41.8 182h.9"/>
</g>
<path d="M4.6 14.5h270.3v181.7h-270.3z" fill="none" stroke="#800000" stroke-width=".21"/>
<g fill="#800000" stroke="#800000" stroke-width=".2">
<path d="M17.4 46.6h2.8v.3h-2.8z"/>
<path d="M17.4 45.9h2.8v.3h-2.8z"/>
<path d="M221.2 103.3h2.8v.4h-2.8z"/>
<path d="M221.2 102.6h2.8v.4h-2.8z"/>
<path d="M240.7 103.3h2.8v.4h-2.8z"/>
<path d="M240.7 102.6h2.8v.4h-2.8z"/>
<path d="M199.9 64.3h2.9v.4h-2.9z"/>
<path d="M199.9 63.6h2.9v.4h-2.9z"/>
<path d="M199.9 32.4h2.9v.4h-2.9z"/>
<path d="M199.9 31.7h2.9v.3h-2.9z"/>
<path d="M121.6 43.6h1.6v.3h-1.6z"/>
<path d="M121.6 41.8h1.6v.4h-1.6z"/>
<path d="M121.6 40h1.6v.4h-1.6z"/>
<path d="M121.6 38.3h1.6v.3h-1.6z"/>
<path d="M208.8 145.9h2.8v.3h-2.8z"/>
<path d="M208.8 145.2h2.8v.3h-2.8z"/>
<path d="M109.5 90.9h2.9v.3h-2.9z"/>
<path d="M109.5 90.2h2.9v.4h-2.9z"/>
<path d="M102.4 90.9h2.9v.3h-2.9z"/>
<path d="M102.4 90.2h2.9v.4h-2.9z"/>
<path d="M95.4 90.9h2.8v.3h-2.8z"/>
<path d="M95.4 90.2h2.8v.4h-2.8z"/>
<path d="M139.7 90.9h2.8v.3h-2.8z"/>
<path d="M139.7 90.2h2.8v.4h-2.8z"/>
<path d="M146.7 90.9h2.9v.3h-2.9z"/>
<path d="M146.7 90.2h2.9v.4h-2.9z"/>
</g>
<g fill="none" stroke="#008000" stroke-width=".2">
<path d="M31.2 31.3v1.8M48.9 31.3v10.7h-1.8M48.9 34.9h10.6v1.8M52.5 34.9v1.8M105.6 38.4h10.7M126.9 38.4h3.6v8.9M141.1 33.1v3.6h7.1M155.3 36.7h1.7M162.3 36.7h3.6v15.9M201.4 26v3.6M201.4 34.9v1.8M212 38.4h10.6"/>
<path d="M217.3 27.8v5.3h5.3M222.6 36.7h-1.7v21.2h31.9v8.9h-1.8M247.4 38.4h17.8M247.4 33.1h5.4v21.3h-37.3v15.9h1.8M18.8 42v1.8M18.8 49.1v1.7M27.6 43.8h5.4M27.6 42h5.4M31.2 40.2v1.8M31.2 43.8v7M31.2 49.1h1.8M31.2 47.3h1.8"/>
<path d="M31.2 45.5h1.8M47.1 47.3h24.8M47.1 45.5h24.8M52.5 43.8v1.7M59.5 42v5.3M105.6 43.8h10.7M105.6 40.2h10.7M105.6 42h10.7M126.9 43.8h3.6M126.9 40.2h3.6M126.9 42h3.6M141.1 43.8h7.1"/>
<path d="M141.1 50.8h7.1M153.5 43.8h5.3M155.3 50.8h3.5M162.3 43.8h3.6M162.3 50.8h3.6M201.4 57.9v3.6M222.6 42h-5.3v3.5M247.4 40.2h17.8M31.2 70.3v17.8h3.5M31.2 73.9h3.5M45.4 77.4h1.7v31.9M45.4 73.9h1.7"/>
<path d="M45.4 79.2h26.5M47.1 70.3v5.4h-1.7M96.8 68.6v19.5M96.8 73.9h17.7M111 77.4h3.5M111 73.9v14.2M130.5 73.9h35.4M134 73.9v3.5h-3.5M148.2 73.9v14.2M158.8 70.3v3.6M165.9 70.3h3.5M169.4 66.8v7.1"/>
<path d="M201.4 66.8v1.8M212 63.2v7.1M212 77.4v8.9h5.3M212 66.8h5.3M217.3 79.2h-1.8v21.3h16M252.8 70.3h1.7v30.2h-19.5M252.8 79.2h15.9M15.2 89.9h19.5M15.2 98.7h19.5M15.2 96.9h19.5M15.2 93.4h19.5M15.2 82.8h19.5"/>
<path d="M15.2 91.6h19.5M33 95.2h1.7M34.7 81h-1.7v28.3M45.4 81h26.5M45.4 84.5h1.7M45.4 89.9h1.7M45.4 98.7h1.7M45.4 96.9h26.5M45.4 93.4h26.5M45.4 82.8h26.5M79 81h35.5M89.7 81v5.3"/>
<path d="M89.7 93.4v1.8M96.8 93.4v1.8M103.9 81v7.1M103.9 93.4v1.8M111 84.5h3.5M111 93.4v1.8M130.5 81h10.6v7.1M130.5 84.5h5.3v10.7M141.1 93.4v1.8M148.2 93.4v1.8M157 86.3v24.8h12.4v19.5h-1.7M180.1 93.4h15.9"/>
<path d="M183.6 93.4v1.8M197.8 81h19.5M197.8 84.5h19.5M197.8 82.8h19.5M217.3 89.9h-5.3v5.3M252.8 81h15.9M15.2 102.3h19.5M15.2 100.5h19.5M15.2 104h19.5M15.2 105.8h19.5M25.9 105.8v1.8M33 107.6h1.7"/>
<path d="M45.4 107.6h26.5M45.4 102.3h1.7M45.4 100.5h26.5M45.4 104h26.5M45.4 105.8h26.5M68.4 120v3.5h-3.5M169.4 100.5v3.5M183.6 102.3v1.7M222.6 105.8v1.8M242.1 105.8v1.8M27.6 127.1h-1.7v56.7M29.4 127.1h23.1v56.7"/>
<path d="M54.2 123.5v5.3h-24.8M56 123.5h-37.2v5.3h8.8M114.5 134.2h21.3M114.5 128.8h21.3M114.5 130.6h21.3M114.5 139.5h21.3M114.5 132.4h21.3M114.5 135.9h21.3M167.7 134.2h1.7v46M174.8 123.5v5.3h-7.1M210.2 134.2v8.8M210.2 137.7h12.4"/>
<path d="M247.4 137.7h1.8v19.5h-49.6M25.9 150.1h1.7M29.4 150.1h23.1M29.4 153.6h12.4M114.5 144.8h21.3M114.5 143h21.3M114.5 159h21.3M114.5 157.2h21.3M114.5 141.2h21.3M114.5 155.4h21.3M114.5 153.6h21.3M199.6 141.2h23"/>
<path d="M203.1 143h19.5M210.2 148.3v1.8M222.6 146.6h-5.3v3.5M247.4 144.8h17.8M247.4 143h17.8M13.5 160.7h14.1M13.5 162.5h14.1M43.6 171.4h23M43.6 174.9h23M43.6 176.7h23M43.6 173.1h23M114.5 160.7h21.3"/>
<path d="M114.5 162.5h21.3M114.5 164.3h21.3M114.5 169.6h21.3M114.5 167.8h21.3M114.5 166.1h21.3M25.9 182h1.7M29.4 182h12.4M29.4 180.2h12.4M43.6 182h8.9"/>
</g>
<g fill="#008000" stroke="#008000" stroke-width=".2">
<circle cx="31.2" cy="49.1" r=".36"/>
<circle cx="31.2" cy="47.3" r=".36"/>
<circle cx="31.2" cy="45.5" r=".36"/>
<circle cx="31.2" cy="43.8" r=".36"/>
<circle cx="33" cy="95.2" r=".36"/>
<circle cx="33" cy="107.6" r=".36"/>
<circle cx="47.1" cy="84.5" r=".36"/>
<circle cx="47.1" cy="89.9" r=".36"/>
<circle cx="47.1" cy="98.7" r=".36"/>
<circle cx="47.1" cy="102.3" r=".36"/>
<circle cx="52.5" cy="182" r=".36"/>
<circle cx="52.5" cy="150.1" r=".36"/>
<circle cx="25.9" cy="182" r=".36"/>
<circle cx="25.9" cy="150.1" r=".36"/>
<circle cx="130.5" cy="43.8" r=".36"/>
<circle cx="130.5" cy="40.2" r=".36"/>
<circle cx="130.5" cy="42" r=".36"/>
<circle cx="165.9" cy="50.8" r=".36"/>
<circle cx="165.9" cy="43.8" r=".36"/>
<circle cx="48.9" cy="34.9" r=".36"/>
<circle cx="52.5" cy="34.9" r=".36"/>
<circle cx="31.2" cy="73.9" r=".36"/>
<circle cx="212" cy="66.8" r=".36"/>
<circle cx="52.5" cy="45.5" r=".36"/>
<circle cx="31.2" cy="42" r=".36"/>
<circle cx="47.1" cy="73.9" r=".36"/>
<circle cx="169.4" cy="70.3" r=".36"/>
<circle cx="252.8" cy="66.8" r=".36"/>
<circle cx="59.5" cy="47.3" r=".36"/>
<circle cx="25.9" cy="105.8" r=".36"/>
<circle cx="222.6" cy="100.5" r=".36"/>
<circle cx="230.6" cy="100.5" r=".36"/>
<circle cx="242.1" cy="100.5" r=".36"/>
<circle cx="235.9" cy="100.5" r=".36"/>
<circle cx="54.2" cy="123.5" r=".36"/>
<circle cx="157" cy="43.8" r=".36"/>
<circle cx="155.3" cy="43.8" r=".36"/>
<circle cx="157" cy="50.8" r=".36"/>
<circle cx="103.9" cy="81" r=".36"/>
<circle cx="89.7" cy="81" r=".36"/>
<circle cx="210.2" cy="137.7" r=".36"/>
<circle cx="111" cy="73.9" r=".36"/>
<circle cx="111" cy="77.4" r=".36"/>
<circle cx="111" cy="84.5" r=".36"/>
<circle cx="96.8" cy="73.9" r=".36"/>
<circle cx="134" cy="73.9" r=".36"/>
<circle cx="148.2" cy="73.9" r=".36"/>
<circle cx="158.8" cy="73.9" r=".36"/>
<circle cx="183.6" cy="93.4" r=".36"/>
</g>
<use href="#words"/>
</svg>
